VERSION 5.8 ;
BUSBITCHARS "[]" ;
DIVIDERCHAR "/" ;
UNITS
    DATABASE MICRONS 1000 ;
END UNITS

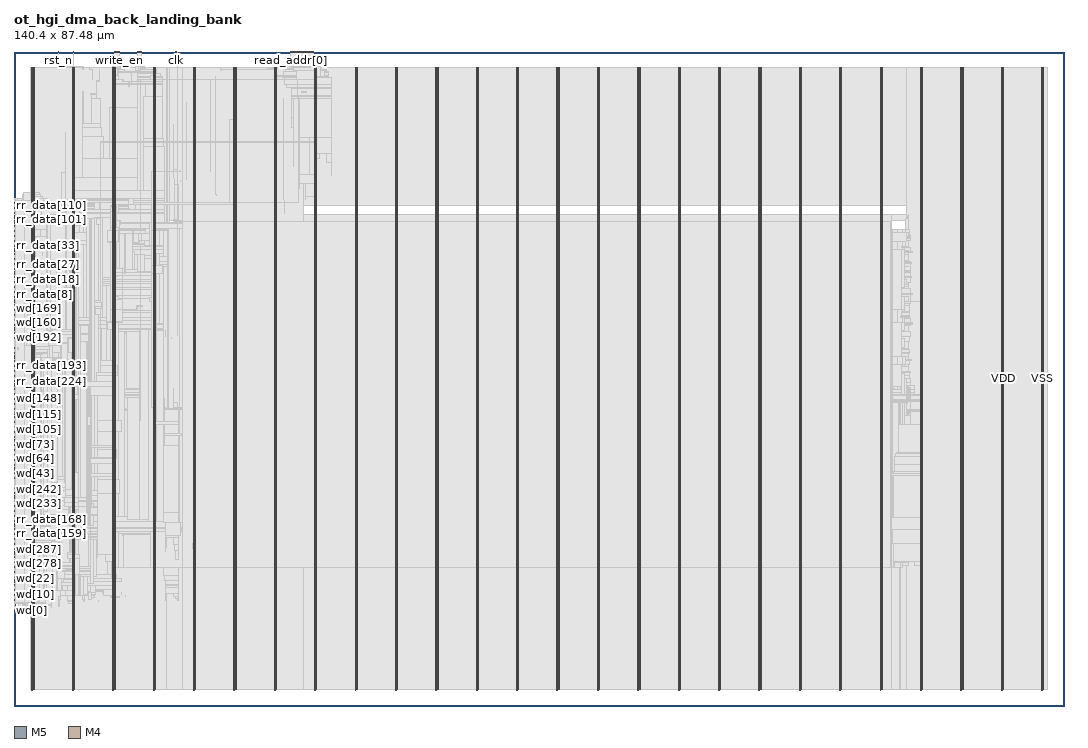
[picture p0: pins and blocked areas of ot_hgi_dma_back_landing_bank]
MACRO ot_hgi_dma_back_landing_bank
  FOREIGN ot_hgi_dma_back_landing_bank 0 0 ;
  CLASS BLOCK ;
  SIZE 140.4 BY 87.48 ;
  PIN clk
    DIRECTION INPUT ;
    USE SIGNAL ;
    PORT
      LAYER M5 ;
        RECT  21.648 87.396 21.672 87.48 ;
    END
  END clk
  PIN output_en
    DIRECTION INPUT ;
    USE SIGNAL ;
    PORT
      LAYER M5 ;
        RECT  40.08 87.396 40.104 87.48 ;
    END
  END output_en
  PIN read_addr[0]
    DIRECTION INPUT ;
    USE SIGNAL ;
    PORT
      LAYER M5 ;
        RECT  37.008 87.396 37.032 87.48 ;
    END
  END read_addr[0]
  PIN read_addr[10]
    DIRECTION INPUT ;
    USE SIGNAL ;
    PORT
      LAYER M5 ;
        RECT  37.968 87.396 37.992 87.48 ;
    END
  END read_addr[10]
  PIN read_addr[11]
    DIRECTION INPUT ;
    USE SIGNAL ;
    PORT
      LAYER M5 ;
        RECT  38.064 87.396 38.088 87.48 ;
    END
  END read_addr[11]
  PIN read_addr[12]
    DIRECTION INPUT ;
    USE SIGNAL ;
    PORT
      LAYER M5 ;
        RECT  38.16 87.396 38.184 87.48 ;
    END
  END read_addr[12]
  PIN read_addr[13]
    DIRECTION INPUT ;
    USE SIGNAL ;
    PORT
      LAYER M5 ;
        RECT  38.256 87.396 38.28 87.48 ;
    END
  END read_addr[13]
  PIN read_addr[14]
    DIRECTION INPUT ;
    USE SIGNAL ;
    PORT
      LAYER M5 ;
        RECT  38.352 87.396 38.376 87.48 ;
    END
  END read_addr[14]
  PIN read_addr[15]
    DIRECTION INPUT ;
    USE SIGNAL ;
    PORT
      LAYER M5 ;
        RECT  38.448 87.396 38.472 87.48 ;
    END
  END read_addr[15]
  PIN read_addr[16]
    DIRECTION INPUT ;
    USE SIGNAL ;
    PORT
      LAYER M5 ;
        RECT  38.544 87.396 38.568 87.48 ;
    END
  END read_addr[16]
  PIN read_addr[17]
    DIRECTION INPUT ;
    USE SIGNAL ;
    PORT
      LAYER M5 ;
        RECT  38.64 87.396 38.664 87.48 ;
    END
  END read_addr[17]
  PIN read_addr[18]
    DIRECTION INPUT ;
    USE SIGNAL ;
    PORT
      LAYER M5 ;
        RECT  38.736 87.396 38.76 87.48 ;
    END
  END read_addr[18]
  PIN read_addr[19]
    DIRECTION INPUT ;
    USE SIGNAL ;
    PORT
      LAYER M5 ;
        RECT  38.832 87.396 38.856 87.48 ;
    END
  END read_addr[19]
  PIN read_addr[1]
    DIRECTION INPUT ;
    USE SIGNAL ;
    PORT
      LAYER M5 ;
        RECT  37.104 87.396 37.128 87.48 ;
    END
  END read_addr[1]
  PIN read_addr[20]
    DIRECTION INPUT ;
    USE SIGNAL ;
    PORT
      LAYER M5 ;
        RECT  38.928 87.396 38.952 87.48 ;
    END
  END read_addr[20]
  PIN read_addr[21]
    DIRECTION INPUT ;
    USE SIGNAL ;
    PORT
      LAYER M5 ;
        RECT  39.024 87.396 39.048 87.48 ;
    END
  END read_addr[21]
  PIN read_addr[22]
    DIRECTION INPUT ;
    USE SIGNAL ;
    PORT
      LAYER M5 ;
        RECT  39.12 87.396 39.144 87.48 ;
    END
  END read_addr[22]
  PIN read_addr[23]
    DIRECTION INPUT ;
    USE SIGNAL ;
    PORT
      LAYER M5 ;
        RECT  39.216 87.396 39.24 87.48 ;
    END
  END read_addr[23]
  PIN read_addr[24]
    DIRECTION INPUT ;
    USE SIGNAL ;
    PORT
      LAYER M5 ;
        RECT  39.312 87.396 39.336 87.48 ;
    END
  END read_addr[24]
  PIN read_addr[25]
    DIRECTION INPUT ;
    USE SIGNAL ;
    PORT
      LAYER M5 ;
        RECT  39.408 87.396 39.432 87.48 ;
    END
  END read_addr[25]
  PIN read_addr[26]
    DIRECTION INPUT ;
    USE SIGNAL ;
    PORT
      LAYER M5 ;
        RECT  39.504 87.396 39.528 87.48 ;
    END
  END read_addr[26]
  PIN read_addr[27]
    DIRECTION INPUT ;
    USE SIGNAL ;
    PORT
      LAYER M5 ;
        RECT  39.6 87.396 39.624 87.48 ;
    END
  END read_addr[27]
  PIN read_addr[28]
    DIRECTION INPUT ;
    USE SIGNAL ;
    PORT
      LAYER M5 ;
        RECT  39.696 87.396 39.72 87.48 ;
    END
  END read_addr[28]
  PIN read_addr[29]
    DIRECTION INPUT ;
    USE SIGNAL ;
    PORT
      LAYER M5 ;
        RECT  39.792 87.396 39.816 87.48 ;
    END
  END read_addr[29]
  PIN read_addr[2]
    DIRECTION INPUT ;
    USE SIGNAL ;
    PORT
      LAYER M5 ;
        RECT  37.2 87.396 37.224 87.48 ;
    END
  END read_addr[2]
  PIN read_addr[30]
    DIRECTION INPUT ;
    USE SIGNAL ;
    PORT
      LAYER M5 ;
        RECT  39.888 87.396 39.912 87.48 ;
    END
  END read_addr[30]
  PIN read_addr[31]
    DIRECTION INPUT ;
    USE SIGNAL ;
    PORT
      LAYER M5 ;
        RECT  39.984 87.396 40.008 87.48 ;
    END
  END read_addr[31]
  PIN read_addr[3]
    DIRECTION INPUT ;
    USE SIGNAL ;
    PORT
      LAYER M5 ;
        RECT  37.296 87.396 37.32 87.48 ;
    END
  END read_addr[3]
  PIN read_addr[4]
    DIRECTION INPUT ;
    USE SIGNAL ;
    PORT
      LAYER M5 ;
        RECT  37.392 87.396 37.416 87.48 ;
    END
  END read_addr[4]
  PIN read_addr[5]
    DIRECTION INPUT ;
    USE SIGNAL ;
    PORT
      LAYER M5 ;
        RECT  37.488 87.396 37.512 87.48 ;
    END
  END read_addr[5]
  PIN read_addr[6]
    DIRECTION INPUT ;
    USE SIGNAL ;
    PORT
      LAYER M5 ;
        RECT  37.584 87.396 37.608 87.48 ;
    END
  END read_addr[6]
  PIN read_addr[7]
    DIRECTION INPUT ;
    USE SIGNAL ;
    PORT
      LAYER M5 ;
        RECT  37.68 87.396 37.704 87.48 ;
    END
  END read_addr[7]
  PIN read_addr[8]
    DIRECTION INPUT ;
    USE SIGNAL ;
    PORT
      LAYER M5 ;
        RECT  37.776 87.396 37.8 87.48 ;
    END
  END read_addr[8]
  PIN read_addr[9]
    DIRECTION INPUT ;
    USE SIGNAL ;
    PORT
      LAYER M5 ;
        RECT  37.872 87.396 37.896 87.48 ;
    END
  END read_addr[9]
  PIN read_en
    DIRECTION INPUT ;
    USE SIGNAL ;
    PORT
      LAYER M5 ;
        RECT  7.92 87.396 7.944 87.48 ;
    END
  END read_en
  PIN read_slot[0]
    DIRECTION INPUT ;
    USE SIGNAL ;
    PORT
      LAYER M5 ;
        RECT  13.392 87.396 13.416 87.48 ;
    END
  END read_slot[0]
  PIN read_slot[1]
    DIRECTION INPUT ;
    USE SIGNAL ;
    PORT
      LAYER M5 ;
        RECT  13.488 87.396 13.512 87.48 ;
    END
  END read_slot[1]
  PIN read_slot[2]
    DIRECTION INPUT ;
    USE SIGNAL ;
    PORT
      LAYER M5 ;
        RECT  13.584 87.396 13.608 87.48 ;
    END
  END read_slot[2]
  PIN read_slot[3]
    DIRECTION INPUT ;
    USE SIGNAL ;
    PORT
      LAYER M5 ;
        RECT  13.68 87.396 13.704 87.48 ;
    END
  END read_slot[3]
  PIN read_slot[4]
    DIRECTION INPUT ;
    USE SIGNAL ;
    PORT
      LAYER M5 ;
        RECT  13.776 87.396 13.8 87.48 ;
    END
  END read_slot[4]
  PIN read_slot[5]
    DIRECTION INPUT ;
    USE SIGNAL ;
    PORT
      LAYER M5 ;
        RECT  13.872 87.396 13.896 87.48 ;
    END
  END read_slot[5]
  PIN read_slot[6]
    DIRECTION INPUT ;
    USE SIGNAL ;
    PORT
      LAYER M5 ;
        RECT  13.968 87.396 13.992 87.48 ;
    END
  END read_slot[6]
  PIN rr_data[0]
    DIRECTION INPUT ;
    USE SIGNAL ;
    PORT
      LAYER M4 ;
        RECT  0 55.344 0.084 55.368 ;
    END
  END rr_data[0]
  PIN rr_data[100]
    DIRECTION INPUT ;
    USE SIGNAL ;
    PORT
      LAYER M4 ;
        RECT  0 64.944 0.084 64.968 ;
    END
  END rr_data[100]
  PIN rr_data[101]
    DIRECTION INPUT ;
    USE SIGNAL ;
    PORT
      LAYER M4 ;
        RECT  0 65.04 0.084 65.064 ;
    END
  END rr_data[101]
  PIN rr_data[102]
    DIRECTION INPUT ;
    USE SIGNAL ;
    PORT
      LAYER M4 ;
        RECT  0 65.136 0.084 65.16 ;
    END
  END rr_data[102]
  PIN rr_data[103]
    DIRECTION INPUT ;
    USE SIGNAL ;
    PORT
      LAYER M4 ;
        RECT  0 65.232 0.084 65.256 ;
    END
  END rr_data[103]
  PIN rr_data[104]
    DIRECTION INPUT ;
    USE SIGNAL ;
    PORT
      LAYER M4 ;
        RECT  0 65.328 0.084 65.352 ;
    END
  END rr_data[104]
  PIN rr_data[105]
    DIRECTION INPUT ;
    USE SIGNAL ;
    PORT
      LAYER M4 ;
        RECT  0 65.424 0.084 65.448 ;
    END
  END rr_data[105]
  PIN rr_data[106]
    DIRECTION INPUT ;
    USE SIGNAL ;
    PORT
      LAYER M4 ;
        RECT  0 65.52 0.084 65.544 ;
    END
  END rr_data[106]
  PIN rr_data[107]
    DIRECTION INPUT ;
    USE SIGNAL ;
    PORT
      LAYER M4 ;
        RECT  0 65.616 0.084 65.64 ;
    END
  END rr_data[107]
  PIN rr_data[108]
    DIRECTION INPUT ;
    USE SIGNAL ;
    PORT
      LAYER M4 ;
        RECT  0 65.712 0.084 65.736 ;
    END
  END rr_data[108]
  PIN rr_data[109]
    DIRECTION INPUT ;
    USE SIGNAL ;
    PORT
      LAYER M4 ;
        RECT  0 65.808 0.084 65.832 ;
    END
  END rr_data[109]
  PIN rr_data[10]
    DIRECTION INPUT ;
    USE SIGNAL ;
    PORT
      LAYER M4 ;
        RECT  0 56.304 0.084 56.328 ;
    END
  END rr_data[10]
  PIN rr_data[110]
    DIRECTION INPUT ;
    USE SIGNAL ;
    PORT
      LAYER M4 ;
        RECT  0 65.904 0.084 65.928 ;
    END
  END rr_data[110]
  PIN rr_data[111]
    DIRECTION INPUT ;
    USE SIGNAL ;
    PORT
      LAYER M4 ;
        RECT  0 66 0.084 66.024 ;
    END
  END rr_data[111]
  PIN rr_data[112]
    DIRECTION INPUT ;
    USE SIGNAL ;
    PORT
      LAYER M4 ;
        RECT  0 66.096 0.084 66.12 ;
    END
  END rr_data[112]
  PIN rr_data[113]
    DIRECTION INPUT ;
    USE SIGNAL ;
    PORT
      LAYER M4 ;
        RECT  0 66.192 0.084 66.216 ;
    END
  END rr_data[113]
  PIN rr_data[114]
    DIRECTION INPUT ;
    USE SIGNAL ;
    PORT
      LAYER M4 ;
        RECT  0 66.288 0.084 66.312 ;
    END
  END rr_data[114]
  PIN rr_data[115]
    DIRECTION INPUT ;
    USE SIGNAL ;
    PORT
      LAYER M4 ;
        RECT  0 66.384 0.084 66.408 ;
    END
  END rr_data[115]
  PIN rr_data[116]
    DIRECTION INPUT ;
    USE SIGNAL ;
    PORT
      LAYER M4 ;
        RECT  0 66.48 0.084 66.504 ;
    END
  END rr_data[116]
  PIN rr_data[117]
    DIRECTION INPUT ;
    USE SIGNAL ;
    PORT
      LAYER M4 ;
        RECT  0 66.576 0.084 66.6 ;
    END
  END rr_data[117]
  PIN rr_data[118]
    DIRECTION INPUT ;
    USE SIGNAL ;
    PORT
      LAYER M4 ;
        RECT  0 66.672 0.084 66.696 ;
    END
  END rr_data[118]
  PIN rr_data[119]
    DIRECTION INPUT ;
    USE SIGNAL ;
    PORT
      LAYER M4 ;
        RECT  0 66.768 0.084 66.792 ;
    END
  END rr_data[119]
  PIN rr_data[11]
    DIRECTION INPUT ;
    USE SIGNAL ;
    PORT
      LAYER M4 ;
        RECT  0 56.4 0.084 56.424 ;
    END
  END rr_data[11]
  PIN rr_data[120]
    DIRECTION INPUT ;
    USE SIGNAL ;
    PORT
      LAYER M4 ;
        RECT  0 66.864 0.084 66.888 ;
    END
  END rr_data[120]
  PIN rr_data[121]
    DIRECTION INPUT ;
    USE SIGNAL ;
    PORT
      LAYER M4 ;
        RECT  0 66.96 0.084 66.984 ;
    END
  END rr_data[121]
  PIN rr_data[122]
    DIRECTION INPUT ;
    USE SIGNAL ;
    PORT
      LAYER M4 ;
        RECT  0 67.056 0.084 67.08 ;
    END
  END rr_data[122]
  PIN rr_data[123]
    DIRECTION INPUT ;
    USE SIGNAL ;
    PORT
      LAYER M4 ;
        RECT  0 67.152 0.084 67.176 ;
    END
  END rr_data[123]
  PIN rr_data[124]
    DIRECTION INPUT ;
    USE SIGNAL ;
    PORT
      LAYER M4 ;
        RECT  0 67.248 0.084 67.272 ;
    END
  END rr_data[124]
  PIN rr_data[125]
    DIRECTION INPUT ;
    USE SIGNAL ;
    PORT
      LAYER M4 ;
        RECT  0 67.344 0.084 67.368 ;
    END
  END rr_data[125]
  PIN rr_data[126]
    DIRECTION INPUT ;
    USE SIGNAL ;
    PORT
      LAYER M4 ;
        RECT  0 67.44 0.084 67.464 ;
    END
  END rr_data[126]
  PIN rr_data[127]
    DIRECTION INPUT ;
    USE SIGNAL ;
    PORT
      LAYER M4 ;
        RECT  0 67.536 0.084 67.56 ;
    END
  END rr_data[127]
  PIN rr_data[128]
    DIRECTION INPUT ;
    USE SIGNAL ;
    PORT
      LAYER M4 ;
        RECT  0 20.016 0.084 20.04 ;
    END
  END rr_data[128]
  PIN rr_data[129]
    DIRECTION INPUT ;
    USE SIGNAL ;
    PORT
      LAYER M4 ;
        RECT  0 20.112 0.084 20.136 ;
    END
  END rr_data[129]
  PIN rr_data[12]
    DIRECTION INPUT ;
    USE SIGNAL ;
    PORT
      LAYER M4 ;
        RECT  0 56.496 0.084 56.52 ;
    END
  END rr_data[12]
  PIN rr_data[130]
    DIRECTION INPUT ;
    USE SIGNAL ;
    PORT
      LAYER M4 ;
        RECT  0 20.208 0.084 20.232 ;
    END
  END rr_data[130]
  PIN rr_data[131]
    DIRECTION INPUT ;
    USE SIGNAL ;
    PORT
      LAYER M4 ;
        RECT  0 20.304 0.084 20.328 ;
    END
  END rr_data[131]
  PIN rr_data[132]
    DIRECTION INPUT ;
    USE SIGNAL ;
    PORT
      LAYER M4 ;
        RECT  0 20.4 0.084 20.424 ;
    END
  END rr_data[132]
  PIN rr_data[133]
    DIRECTION INPUT ;
    USE SIGNAL ;
    PORT
      LAYER M4 ;
        RECT  0 20.496 0.084 20.52 ;
    END
  END rr_data[133]
  PIN rr_data[134]
    DIRECTION INPUT ;
    USE SIGNAL ;
    PORT
      LAYER M4 ;
        RECT  0 20.592 0.084 20.616 ;
    END
  END rr_data[134]
  PIN rr_data[135]
    DIRECTION INPUT ;
    USE SIGNAL ;
    PORT
      LAYER M4 ;
        RECT  0 20.688 0.084 20.712 ;
    END
  END rr_data[135]
  PIN rr_data[136]
    DIRECTION INPUT ;
    USE SIGNAL ;
    PORT
      LAYER M4 ;
        RECT  0 20.784 0.084 20.808 ;
    END
  END rr_data[136]
  PIN rr_data[137]
    DIRECTION INPUT ;
    USE SIGNAL ;
    PORT
      LAYER M4 ;
        RECT  0 20.88 0.084 20.904 ;
    END
  END rr_data[137]
  PIN rr_data[138]
    DIRECTION INPUT ;
    USE SIGNAL ;
    PORT
      LAYER M4 ;
        RECT  0 20.976 0.084 21 ;
    END
  END rr_data[138]
  PIN rr_data[139]
    DIRECTION INPUT ;
    USE SIGNAL ;
    PORT
      LAYER M4 ;
        RECT  0 21.072 0.084 21.096 ;
    END
  END rr_data[139]
  PIN rr_data[13]
    DIRECTION INPUT ;
    USE SIGNAL ;
    PORT
      LAYER M4 ;
        RECT  0 56.592 0.084 56.616 ;
    END
  END rr_data[13]
  PIN rr_data[140]
    DIRECTION INPUT ;
    USE SIGNAL ;
    PORT
      LAYER M4 ;
        RECT  0 21.168 0.084 21.192 ;
    END
  END rr_data[140]
  PIN rr_data[141]
    DIRECTION INPUT ;
    USE SIGNAL ;
    PORT
      LAYER M4 ;
        RECT  0 21.264 0.084 21.288 ;
    END
  END rr_data[141]
  PIN rr_data[142]
    DIRECTION INPUT ;
    USE SIGNAL ;
    PORT
      LAYER M4 ;
        RECT  0 21.36 0.084 21.384 ;
    END
  END rr_data[142]
  PIN rr_data[143]
    DIRECTION INPUT ;
    USE SIGNAL ;
    PORT
      LAYER M4 ;
        RECT  0 21.456 0.084 21.48 ;
    END
  END rr_data[143]
  PIN rr_data[144]
    DIRECTION INPUT ;
    USE SIGNAL ;
    PORT
      LAYER M4 ;
        RECT  0 21.552 0.084 21.576 ;
    END
  END rr_data[144]
  PIN rr_data[145]
    DIRECTION INPUT ;
    USE SIGNAL ;
    PORT
      LAYER M4 ;
        RECT  0 21.648 0.084 21.672 ;
    END
  END rr_data[145]
  PIN rr_data[146]
    DIRECTION INPUT ;
    USE SIGNAL ;
    PORT
      LAYER M4 ;
        RECT  0 21.744 0.084 21.768 ;
    END
  END rr_data[146]
  PIN rr_data[147]
    DIRECTION INPUT ;
    USE SIGNAL ;
    PORT
      LAYER M4 ;
        RECT  0 21.84 0.084 21.864 ;
    END
  END rr_data[147]
  PIN rr_data[148]
    DIRECTION INPUT ;
    USE SIGNAL ;
    PORT
      LAYER M4 ;
        RECT  0 21.936 0.084 21.96 ;
    END
  END rr_data[148]
  PIN rr_data[149]
    DIRECTION INPUT ;
    USE SIGNAL ;
    PORT
      LAYER M4 ;
        RECT  0 22.032 0.084 22.056 ;
    END
  END rr_data[149]
  PIN rr_data[14]
    DIRECTION INPUT ;
    USE SIGNAL ;
    PORT
      LAYER M4 ;
        RECT  0 56.688 0.084 56.712 ;
    END
  END rr_data[14]
  PIN rr_data[150]
    DIRECTION INPUT ;
    USE SIGNAL ;
    PORT
      LAYER M4 ;
        RECT  0 22.128 0.084 22.152 ;
    END
  END rr_data[150]
  PIN rr_data[151]
    DIRECTION INPUT ;
    USE SIGNAL ;
    PORT
      LAYER M4 ;
        RECT  0 22.224 0.084 22.248 ;
    END
  END rr_data[151]
  PIN rr_data[152]
    DIRECTION INPUT ;
    USE SIGNAL ;
    PORT
      LAYER M4 ;
        RECT  0 22.32 0.084 22.344 ;
    END
  END rr_data[152]
  PIN rr_data[153]
    DIRECTION INPUT ;
    USE SIGNAL ;
    PORT
      LAYER M4 ;
        RECT  0 22.416 0.084 22.44 ;
    END
  END rr_data[153]
  PIN rr_data[154]
    DIRECTION INPUT ;
    USE SIGNAL ;
    PORT
      LAYER M4 ;
        RECT  0 22.512 0.084 22.536 ;
    END
  END rr_data[154]
  PIN rr_data[155]
    DIRECTION INPUT ;
    USE SIGNAL ;
    PORT
      LAYER M4 ;
        RECT  0 22.608 0.084 22.632 ;
    END
  END rr_data[155]
  PIN rr_data[156]
    DIRECTION INPUT ;
    USE SIGNAL ;
    PORT
      LAYER M4 ;
        RECT  0 22.704 0.084 22.728 ;
    END
  END rr_data[156]
  PIN rr_data[157]
    DIRECTION INPUT ;
    USE SIGNAL ;
    PORT
      LAYER M4 ;
        RECT  0 22.8 0.084 22.824 ;
    END
  END rr_data[157]
  PIN rr_data[158]
    DIRECTION INPUT ;
    USE SIGNAL ;
    PORT
      LAYER M4 ;
        RECT  0 22.896 0.084 22.92 ;
    END
  END rr_data[158]
  PIN rr_data[159]
    DIRECTION INPUT ;
    USE SIGNAL ;
    PORT
      LAYER M4 ;
        RECT  0 22.992 0.084 23.016 ;
    END
  END rr_data[159]
  PIN rr_data[15]
    DIRECTION INPUT ;
    USE SIGNAL ;
    PORT
      LAYER M4 ;
        RECT  0 56.784 0.084 56.808 ;
    END
  END rr_data[15]
  PIN rr_data[160]
    DIRECTION INPUT ;
    USE SIGNAL ;
    PORT
      LAYER M4 ;
        RECT  0 23.088 0.084 23.112 ;
    END
  END rr_data[160]
  PIN rr_data[161]
    DIRECTION INPUT ;
    USE SIGNAL ;
    PORT
      LAYER M4 ;
        RECT  0 23.184 0.084 23.208 ;
    END
  END rr_data[161]
  PIN rr_data[162]
    DIRECTION INPUT ;
    USE SIGNAL ;
    PORT
      LAYER M4 ;
        RECT  0 23.28 0.084 23.304 ;
    END
  END rr_data[162]
  PIN rr_data[163]
    DIRECTION INPUT ;
    USE SIGNAL ;
    PORT
      LAYER M4 ;
        RECT  0 23.376 0.084 23.4 ;
    END
  END rr_data[163]
  PIN rr_data[164]
    DIRECTION INPUT ;
    USE SIGNAL ;
    PORT
      LAYER M4 ;
        RECT  0 23.472 0.084 23.496 ;
    END
  END rr_data[164]
  PIN rr_data[165]
    DIRECTION INPUT ;
    USE SIGNAL ;
    PORT
      LAYER M4 ;
        RECT  0 23.568 0.084 23.592 ;
    END
  END rr_data[165]
  PIN rr_data[166]
    DIRECTION INPUT ;
    USE SIGNAL ;
    PORT
      LAYER M4 ;
        RECT  0 23.664 0.084 23.688 ;
    END
  END rr_data[166]
  PIN rr_data[167]
    DIRECTION INPUT ;
    USE SIGNAL ;
    PORT
      LAYER M4 ;
        RECT  0 23.76 0.084 23.784 ;
    END
  END rr_data[167]
  PIN rr_data[168]
    DIRECTION INPUT ;
    USE SIGNAL ;
    PORT
      LAYER M4 ;
        RECT  0 23.856 0.084 23.88 ;
    END
  END rr_data[168]
  PIN rr_data[169]
    DIRECTION INPUT ;
    USE SIGNAL ;
    PORT
      LAYER M4 ;
        RECT  0 23.952 0.084 23.976 ;
    END
  END rr_data[169]
  PIN rr_data[16]
    DIRECTION INPUT ;
    USE SIGNAL ;
    PORT
      LAYER M4 ;
        RECT  0 56.88 0.084 56.904 ;
    END
  END rr_data[16]
  PIN rr_data[170]
    DIRECTION INPUT ;
    USE SIGNAL ;
    PORT
      LAYER M4 ;
        RECT  0 24.048 0.084 24.072 ;
    END
  END rr_data[170]
  PIN rr_data[171]
    DIRECTION INPUT ;
    USE SIGNAL ;
    PORT
      LAYER M4 ;
        RECT  0 24.144 0.084 24.168 ;
    END
  END rr_data[171]
  PIN rr_data[172]
    DIRECTION INPUT ;
    USE SIGNAL ;
    PORT
      LAYER M4 ;
        RECT  0 24.24 0.084 24.264 ;
    END
  END rr_data[172]
  PIN rr_data[173]
    DIRECTION INPUT ;
    USE SIGNAL ;
    PORT
      LAYER M4 ;
        RECT  0 24.336 0.084 24.36 ;
    END
  END rr_data[173]
  PIN rr_data[174]
    DIRECTION INPUT ;
    USE SIGNAL ;
    PORT
      LAYER M4 ;
        RECT  0 24.432 0.084 24.456 ;
    END
  END rr_data[174]
  PIN rr_data[175]
    DIRECTION INPUT ;
    USE SIGNAL ;
    PORT
      LAYER M4 ;
        RECT  0 24.528 0.084 24.552 ;
    END
  END rr_data[175]
  PIN rr_data[176]
    DIRECTION INPUT ;
    USE SIGNAL ;
    PORT
      LAYER M4 ;
        RECT  0 24.624 0.084 24.648 ;
    END
  END rr_data[176]
  PIN rr_data[177]
    DIRECTION INPUT ;
    USE SIGNAL ;
    PORT
      LAYER M4 ;
        RECT  0 24.72 0.084 24.744 ;
    END
  END rr_data[177]
  PIN rr_data[178]
    DIRECTION INPUT ;
    USE SIGNAL ;
    PORT
      LAYER M4 ;
        RECT  0 24.816 0.084 24.84 ;
    END
  END rr_data[178]
  PIN rr_data[179]
    DIRECTION INPUT ;
    USE SIGNAL ;
    PORT
      LAYER M4 ;
        RECT  0 24.912 0.084 24.936 ;
    END
  END rr_data[179]
  PIN rr_data[17]
    DIRECTION INPUT ;
    USE SIGNAL ;
    PORT
      LAYER M4 ;
        RECT  0 56.976 0.084 57 ;
    END
  END rr_data[17]
  PIN rr_data[180]
    DIRECTION INPUT ;
    USE SIGNAL ;
    PORT
      LAYER M4 ;
        RECT  0 25.008 0.084 25.032 ;
    END
  END rr_data[180]
  PIN rr_data[181]
    DIRECTION INPUT ;
    USE SIGNAL ;
    PORT
      LAYER M4 ;
        RECT  0 25.104 0.084 25.128 ;
    END
  END rr_data[181]
  PIN rr_data[182]
    DIRECTION INPUT ;
    USE SIGNAL ;
    PORT
      LAYER M4 ;
        RECT  0 25.2 0.084 25.224 ;
    END
  END rr_data[182]
  PIN rr_data[183]
    DIRECTION INPUT ;
    USE SIGNAL ;
    PORT
      LAYER M4 ;
        RECT  0 25.296 0.084 25.32 ;
    END
  END rr_data[183]
  PIN rr_data[184]
    DIRECTION INPUT ;
    USE SIGNAL ;
    PORT
      LAYER M4 ;
        RECT  0 25.392 0.084 25.416 ;
    END
  END rr_data[184]
  PIN rr_data[185]
    DIRECTION INPUT ;
    USE SIGNAL ;
    PORT
      LAYER M4 ;
        RECT  0 25.488 0.084 25.512 ;
    END
  END rr_data[185]
  PIN rr_data[186]
    DIRECTION INPUT ;
    USE SIGNAL ;
    PORT
      LAYER M4 ;
        RECT  0 25.584 0.084 25.608 ;
    END
  END rr_data[186]
  PIN rr_data[187]
    DIRECTION INPUT ;
    USE SIGNAL ;
    PORT
      LAYER M4 ;
        RECT  0 25.68 0.084 25.704 ;
    END
  END rr_data[187]
  PIN rr_data[188]
    DIRECTION INPUT ;
    USE SIGNAL ;
    PORT
      LAYER M4 ;
        RECT  0 25.776 0.084 25.8 ;
    END
  END rr_data[188]
  PIN rr_data[189]
    DIRECTION INPUT ;
    USE SIGNAL ;
    PORT
      LAYER M4 ;
        RECT  0 25.872 0.084 25.896 ;
    END
  END rr_data[189]
  PIN rr_data[18]
    DIRECTION INPUT ;
    USE SIGNAL ;
    PORT
      LAYER M4 ;
        RECT  0 57.072 0.084 57.096 ;
    END
  END rr_data[18]
  PIN rr_data[190]
    DIRECTION INPUT ;
    USE SIGNAL ;
    PORT
      LAYER M4 ;
        RECT  0 25.968 0.084 25.992 ;
    END
  END rr_data[190]
  PIN rr_data[191]
    DIRECTION INPUT ;
    USE SIGNAL ;
    PORT
      LAYER M4 ;
        RECT  0 26.064 0.084 26.088 ;
    END
  END rr_data[191]
  PIN rr_data[192]
    DIRECTION INPUT ;
    USE SIGNAL ;
    PORT
      LAYER M4 ;
        RECT  0 45.36 0.084 45.384 ;
    END
  END rr_data[192]
  PIN rr_data[193]
    DIRECTION INPUT ;
    USE SIGNAL ;
    PORT
      LAYER M4 ;
        RECT  0 45.456 0.084 45.48 ;
    END
  END rr_data[193]
  PIN rr_data[194]
    DIRECTION INPUT ;
    USE SIGNAL ;
    PORT
      LAYER M4 ;
        RECT  0 45.552 0.084 45.576 ;
    END
  END rr_data[194]
  PIN rr_data[195]
    DIRECTION INPUT ;
    USE SIGNAL ;
    PORT
      LAYER M4 ;
        RECT  0 45.648 0.084 45.672 ;
    END
  END rr_data[195]
  PIN rr_data[196]
    DIRECTION INPUT ;
    USE SIGNAL ;
    PORT
      LAYER M4 ;
        RECT  0 45.744 0.084 45.768 ;
    END
  END rr_data[196]
  PIN rr_data[197]
    DIRECTION INPUT ;
    USE SIGNAL ;
    PORT
      LAYER M4 ;
        RECT  0 45.84 0.084 45.864 ;
    END
  END rr_data[197]
  PIN rr_data[198]
    DIRECTION INPUT ;
    USE SIGNAL ;
    PORT
      LAYER M4 ;
        RECT  0 45.936 0.084 45.96 ;
    END
  END rr_data[198]
  PIN rr_data[199]
    DIRECTION INPUT ;
    USE SIGNAL ;
    PORT
      LAYER M4 ;
        RECT  0 46.032 0.084 46.056 ;
    END
  END rr_data[199]
  PIN rr_data[19]
    DIRECTION INPUT ;
    USE SIGNAL ;
    PORT
      LAYER M4 ;
        RECT  0 57.168 0.084 57.192 ;
    END
  END rr_data[19]
  PIN rr_data[1]
    DIRECTION INPUT ;
    USE SIGNAL ;
    PORT
      LAYER M4 ;
        RECT  0 55.44 0.084 55.464 ;
    END
  END rr_data[1]
  PIN rr_data[200]
    DIRECTION INPUT ;
    USE SIGNAL ;
    PORT
      LAYER M4 ;
        RECT  0 46.128 0.084 46.152 ;
    END
  END rr_data[200]
  PIN rr_data[201]
    DIRECTION INPUT ;
    USE SIGNAL ;
    PORT
      LAYER M4 ;
        RECT  0 46.224 0.084 46.248 ;
    END
  END rr_data[201]
  PIN rr_data[202]
    DIRECTION INPUT ;
    USE SIGNAL ;
    PORT
      LAYER M4 ;
        RECT  0 46.32 0.084 46.344 ;
    END
  END rr_data[202]
  PIN rr_data[203]
    DIRECTION INPUT ;
    USE SIGNAL ;
    PORT
      LAYER M4 ;
        RECT  0 46.416 0.084 46.44 ;
    END
  END rr_data[203]
  PIN rr_data[204]
    DIRECTION INPUT ;
    USE SIGNAL ;
    PORT
      LAYER M4 ;
        RECT  0 46.512 0.084 46.536 ;
    END
  END rr_data[204]
  PIN rr_data[205]
    DIRECTION INPUT ;
    USE SIGNAL ;
    PORT
      LAYER M4 ;
        RECT  0 46.608 0.084 46.632 ;
    END
  END rr_data[205]
  PIN rr_data[206]
    DIRECTION INPUT ;
    USE SIGNAL ;
    PORT
      LAYER M4 ;
        RECT  0 46.704 0.084 46.728 ;
    END
  END rr_data[206]
  PIN rr_data[207]
    DIRECTION INPUT ;
    USE SIGNAL ;
    PORT
      LAYER M4 ;
        RECT  0 46.8 0.084 46.824 ;
    END
  END rr_data[207]
  PIN rr_data[208]
    DIRECTION INPUT ;
    USE SIGNAL ;
    PORT
      LAYER M4 ;
        RECT  0 46.896 0.084 46.92 ;
    END
  END rr_data[208]
  PIN rr_data[209]
    DIRECTION INPUT ;
    USE SIGNAL ;
    PORT
      LAYER M4 ;
        RECT  0 46.992 0.084 47.016 ;
    END
  END rr_data[209]
  PIN rr_data[20]
    DIRECTION INPUT ;
    USE SIGNAL ;
    PORT
      LAYER M4 ;
        RECT  0 57.264 0.084 57.288 ;
    END
  END rr_data[20]
  PIN rr_data[210]
    DIRECTION INPUT ;
    USE SIGNAL ;
    PORT
      LAYER M4 ;
        RECT  0 47.088 0.084 47.112 ;
    END
  END rr_data[210]
  PIN rr_data[211]
    DIRECTION INPUT ;
    USE SIGNAL ;
    PORT
      LAYER M4 ;
        RECT  0 47.184 0.084 47.208 ;
    END
  END rr_data[211]
  PIN rr_data[212]
    DIRECTION INPUT ;
    USE SIGNAL ;
    PORT
      LAYER M4 ;
        RECT  0 47.28 0.084 47.304 ;
    END
  END rr_data[212]
  PIN rr_data[213]
    DIRECTION INPUT ;
    USE SIGNAL ;
    PORT
      LAYER M4 ;
        RECT  0 47.376 0.084 47.4 ;
    END
  END rr_data[213]
  PIN rr_data[214]
    DIRECTION INPUT ;
    USE SIGNAL ;
    PORT
      LAYER M4 ;
        RECT  0 47.472 0.084 47.496 ;
    END
  END rr_data[214]
  PIN rr_data[215]
    DIRECTION INPUT ;
    USE SIGNAL ;
    PORT
      LAYER M4 ;
        RECT  0 47.568 0.084 47.592 ;
    END
  END rr_data[215]
  PIN rr_data[216]
    DIRECTION INPUT ;
    USE SIGNAL ;
    PORT
      LAYER M4 ;
        RECT  0 47.664 0.084 47.688 ;
    END
  END rr_data[216]
  PIN rr_data[217]
    DIRECTION INPUT ;
    USE SIGNAL ;
    PORT
      LAYER M4 ;
        RECT  0 47.76 0.084 47.784 ;
    END
  END rr_data[217]
  PIN rr_data[218]
    DIRECTION INPUT ;
    USE SIGNAL ;
    PORT
      LAYER M4 ;
        RECT  0 47.856 0.084 47.88 ;
    END
  END rr_data[218]
  PIN rr_data[219]
    DIRECTION INPUT ;
    USE SIGNAL ;
    PORT
      LAYER M4 ;
        RECT  0 47.952 0.084 47.976 ;
    END
  END rr_data[219]
  PIN rr_data[21]
    DIRECTION INPUT ;
    USE SIGNAL ;
    PORT
      LAYER M4 ;
        RECT  0 57.36 0.084 57.384 ;
    END
  END rr_data[21]
  PIN rr_data[220]
    DIRECTION INPUT ;
    USE SIGNAL ;
    PORT
      LAYER M4 ;
        RECT  0 48.048 0.084 48.072 ;
    END
  END rr_data[220]
  PIN rr_data[221]
    DIRECTION INPUT ;
    USE SIGNAL ;
    PORT
      LAYER M4 ;
        RECT  0 48.144 0.084 48.168 ;
    END
  END rr_data[221]
  PIN rr_data[222]
    DIRECTION INPUT ;
    USE SIGNAL ;
    PORT
      LAYER M4 ;
        RECT  0 48.24 0.084 48.264 ;
    END
  END rr_data[222]
  PIN rr_data[223]
    DIRECTION INPUT ;
    USE SIGNAL ;
    PORT
      LAYER M4 ;
        RECT  0 48.336 0.084 48.36 ;
    END
  END rr_data[223]
  PIN rr_data[224]
    DIRECTION INPUT ;
    USE SIGNAL ;
    PORT
      LAYER M4 ;
        RECT  0 42.288 0.084 42.312 ;
    END
  END rr_data[224]
  PIN rr_data[225]
    DIRECTION INPUT ;
    USE SIGNAL ;
    PORT
      LAYER M4 ;
        RECT  0 42.384 0.084 42.408 ;
    END
  END rr_data[225]
  PIN rr_data[226]
    DIRECTION INPUT ;
    USE SIGNAL ;
    PORT
      LAYER M4 ;
        RECT  0 42.48 0.084 42.504 ;
    END
  END rr_data[226]
  PIN rr_data[227]
    DIRECTION INPUT ;
    USE SIGNAL ;
    PORT
      LAYER M4 ;
        RECT  0 42.576 0.084 42.6 ;
    END
  END rr_data[227]
  PIN rr_data[228]
    DIRECTION INPUT ;
    USE SIGNAL ;
    PORT
      LAYER M4 ;
        RECT  0 42.672 0.084 42.696 ;
    END
  END rr_data[228]
  PIN rr_data[229]
    DIRECTION INPUT ;
    USE SIGNAL ;
    PORT
      LAYER M4 ;
        RECT  0 42.768 0.084 42.792 ;
    END
  END rr_data[229]
  PIN rr_data[22]
    DIRECTION INPUT ;
    USE SIGNAL ;
    PORT
      LAYER M4 ;
        RECT  0 57.456 0.084 57.48 ;
    END
  END rr_data[22]
  PIN rr_data[230]
    DIRECTION INPUT ;
    USE SIGNAL ;
    PORT
      LAYER M4 ;
        RECT  0 42.864 0.084 42.888 ;
    END
  END rr_data[230]
  PIN rr_data[231]
    DIRECTION INPUT ;
    USE SIGNAL ;
    PORT
      LAYER M4 ;
        RECT  0 42.96 0.084 42.984 ;
    END
  END rr_data[231]
  PIN rr_data[232]
    DIRECTION INPUT ;
    USE SIGNAL ;
    PORT
      LAYER M4 ;
        RECT  0 43.056 0.084 43.08 ;
    END
  END rr_data[232]
  PIN rr_data[233]
    DIRECTION INPUT ;
    USE SIGNAL ;
    PORT
      LAYER M4 ;
        RECT  0 43.152 0.084 43.176 ;
    END
  END rr_data[233]
  PIN rr_data[234]
    DIRECTION INPUT ;
    USE SIGNAL ;
    PORT
      LAYER M4 ;
        RECT  0 43.248 0.084 43.272 ;
    END
  END rr_data[234]
  PIN rr_data[235]
    DIRECTION INPUT ;
    USE SIGNAL ;
    PORT
      LAYER M4 ;
        RECT  0 43.344 0.084 43.368 ;
    END
  END rr_data[235]
  PIN rr_data[236]
    DIRECTION INPUT ;
    USE SIGNAL ;
    PORT
      LAYER M4 ;
        RECT  0 43.44 0.084 43.464 ;
    END
  END rr_data[236]
  PIN rr_data[237]
    DIRECTION INPUT ;
    USE SIGNAL ;
    PORT
      LAYER M4 ;
        RECT  0 43.536 0.084 43.56 ;
    END
  END rr_data[237]
  PIN rr_data[238]
    DIRECTION INPUT ;
    USE SIGNAL ;
    PORT
      LAYER M4 ;
        RECT  0 43.632 0.084 43.656 ;
    END
  END rr_data[238]
  PIN rr_data[239]
    DIRECTION INPUT ;
    USE SIGNAL ;
    PORT
      LAYER M4 ;
        RECT  0 43.728 0.084 43.752 ;
    END
  END rr_data[239]
  PIN rr_data[23]
    DIRECTION INPUT ;
    USE SIGNAL ;
    PORT
      LAYER M4 ;
        RECT  0 57.552 0.084 57.576 ;
    END
  END rr_data[23]
  PIN rr_data[240]
    DIRECTION INPUT ;
    USE SIGNAL ;
    PORT
      LAYER M4 ;
        RECT  0 43.824 0.084 43.848 ;
    END
  END rr_data[240]
  PIN rr_data[241]
    DIRECTION INPUT ;
    USE SIGNAL ;
    PORT
      LAYER M4 ;
        RECT  0 43.92 0.084 43.944 ;
    END
  END rr_data[241]
  PIN rr_data[242]
    DIRECTION INPUT ;
    USE SIGNAL ;
    PORT
      LAYER M4 ;
        RECT  0 44.016 0.084 44.04 ;
    END
  END rr_data[242]
  PIN rr_data[243]
    DIRECTION INPUT ;
    USE SIGNAL ;
    PORT
      LAYER M4 ;
        RECT  0 44.112 0.084 44.136 ;
    END
  END rr_data[243]
  PIN rr_data[244]
    DIRECTION INPUT ;
    USE SIGNAL ;
    PORT
      LAYER M4 ;
        RECT  0 44.208 0.084 44.232 ;
    END
  END rr_data[244]
  PIN rr_data[245]
    DIRECTION INPUT ;
    USE SIGNAL ;
    PORT
      LAYER M4 ;
        RECT  0 44.304 0.084 44.328 ;
    END
  END rr_data[245]
  PIN rr_data[246]
    DIRECTION INPUT ;
    USE SIGNAL ;
    PORT
      LAYER M4 ;
        RECT  0 44.4 0.084 44.424 ;
    END
  END rr_data[246]
  PIN rr_data[247]
    DIRECTION INPUT ;
    USE SIGNAL ;
    PORT
      LAYER M4 ;
        RECT  0 44.496 0.084 44.52 ;
    END
  END rr_data[247]
  PIN rr_data[248]
    DIRECTION INPUT ;
    USE SIGNAL ;
    PORT
      LAYER M4 ;
        RECT  0 44.592 0.084 44.616 ;
    END
  END rr_data[248]
  PIN rr_data[249]
    DIRECTION INPUT ;
    USE SIGNAL ;
    PORT
      LAYER M4 ;
        RECT  0 44.688 0.084 44.712 ;
    END
  END rr_data[249]
  PIN rr_data[24]
    DIRECTION INPUT ;
    USE SIGNAL ;
    PORT
      LAYER M4 ;
        RECT  0 57.648 0.084 57.672 ;
    END
  END rr_data[24]
  PIN rr_data[250]
    DIRECTION INPUT ;
    USE SIGNAL ;
    PORT
      LAYER M4 ;
        RECT  0 44.784 0.084 44.808 ;
    END
  END rr_data[250]
  PIN rr_data[251]
    DIRECTION INPUT ;
    USE SIGNAL ;
    PORT
      LAYER M4 ;
        RECT  0 44.88 0.084 44.904 ;
    END
  END rr_data[251]
  PIN rr_data[252]
    DIRECTION INPUT ;
    USE SIGNAL ;
    PORT
      LAYER M4 ;
        RECT  0 44.976 0.084 45 ;
    END
  END rr_data[252]
  PIN rr_data[253]
    DIRECTION INPUT ;
    USE SIGNAL ;
    PORT
      LAYER M4 ;
        RECT  0 45.072 0.084 45.096 ;
    END
  END rr_data[253]
  PIN rr_data[254]
    DIRECTION INPUT ;
    USE SIGNAL ;
    PORT
      LAYER M4 ;
        RECT  0 45.168 0.084 45.192 ;
    END
  END rr_data[254]
  PIN rr_data[255]
    DIRECTION INPUT ;
    USE SIGNAL ;
    PORT
      LAYER M4 ;
        RECT  0 45.264 0.084 45.288 ;
    END
  END rr_data[255]
  PIN rr_data[25]
    DIRECTION INPUT ;
    USE SIGNAL ;
    PORT
      LAYER M4 ;
        RECT  0 57.744 0.084 57.768 ;
    END
  END rr_data[25]
  PIN rr_data[26]
    DIRECTION INPUT ;
    USE SIGNAL ;
    PORT
      LAYER M4 ;
        RECT  0 57.84 0.084 57.864 ;
    END
  END rr_data[26]
  PIN rr_data[27]
    DIRECTION INPUT ;
    USE SIGNAL ;
    PORT
      LAYER M4 ;
        RECT  0 57.936 0.084 57.96 ;
    END
  END rr_data[27]
  PIN rr_data[28]
    DIRECTION INPUT ;
    USE SIGNAL ;
    PORT
      LAYER M4 ;
        RECT  0 58.032 0.084 58.056 ;
    END
  END rr_data[28]
  PIN rr_data[29]
    DIRECTION INPUT ;
    USE SIGNAL ;
    PORT
      LAYER M4 ;
        RECT  0 58.128 0.084 58.152 ;
    END
  END rr_data[29]
  PIN rr_data[2]
    DIRECTION INPUT ;
    USE SIGNAL ;
    PORT
      LAYER M4 ;
        RECT  0 55.536 0.084 55.56 ;
    END
  END rr_data[2]
  PIN rr_data[30]
    DIRECTION INPUT ;
    USE SIGNAL ;
    PORT
      LAYER M4 ;
        RECT  0 58.224 0.084 58.248 ;
    END
  END rr_data[30]
  PIN rr_data[31]
    DIRECTION INPUT ;
    USE SIGNAL ;
    PORT
      LAYER M4 ;
        RECT  0 58.32 0.084 58.344 ;
    END
  END rr_data[31]
  PIN rr_data[32]
    DIRECTION INPUT ;
    USE SIGNAL ;
    PORT
      LAYER M4 ;
        RECT  0 61.488 0.084 61.512 ;
    END
  END rr_data[32]
  PIN rr_data[33]
    DIRECTION INPUT ;
    USE SIGNAL ;
    PORT
      LAYER M4 ;
        RECT  0 61.584 0.084 61.608 ;
    END
  END rr_data[33]
  PIN rr_data[34]
    DIRECTION INPUT ;
    USE SIGNAL ;
    PORT
      LAYER M4 ;
        RECT  0 61.68 0.084 61.704 ;
    END
  END rr_data[34]
  PIN rr_data[35]
    DIRECTION INPUT ;
    USE SIGNAL ;
    PORT
      LAYER M4 ;
        RECT  0 61.776 0.084 61.8 ;
    END
  END rr_data[35]
  PIN rr_data[36]
    DIRECTION INPUT ;
    USE SIGNAL ;
    PORT
      LAYER M4 ;
        RECT  0 61.872 0.084 61.896 ;
    END
  END rr_data[36]
  PIN rr_data[37]
    DIRECTION INPUT ;
    USE SIGNAL ;
    PORT
      LAYER M4 ;
        RECT  0 61.968 0.084 61.992 ;
    END
  END rr_data[37]
  PIN rr_data[38]
    DIRECTION INPUT ;
    USE SIGNAL ;
    PORT
      LAYER M4 ;
        RECT  0 62.064 0.084 62.088 ;
    END
  END rr_data[38]
  PIN rr_data[39]
    DIRECTION INPUT ;
    USE SIGNAL ;
    PORT
      LAYER M4 ;
        RECT  0 62.16 0.084 62.184 ;
    END
  END rr_data[39]
  PIN rr_data[3]
    DIRECTION INPUT ;
    USE SIGNAL ;
    PORT
      LAYER M4 ;
        RECT  0 55.632 0.084 55.656 ;
    END
  END rr_data[3]
  PIN rr_data[40]
    DIRECTION INPUT ;
    USE SIGNAL ;
    PORT
      LAYER M4 ;
        RECT  0 62.256 0.084 62.28 ;
    END
  END rr_data[40]
  PIN rr_data[41]
    DIRECTION INPUT ;
    USE SIGNAL ;
    PORT
      LAYER M4 ;
        RECT  0 62.352 0.084 62.376 ;
    END
  END rr_data[41]
  PIN rr_data[42]
    DIRECTION INPUT ;
    USE SIGNAL ;
    PORT
      LAYER M4 ;
        RECT  0 62.448 0.084 62.472 ;
    END
  END rr_data[42]
  PIN rr_data[43]
    DIRECTION INPUT ;
    USE SIGNAL ;
    PORT
      LAYER M4 ;
        RECT  0 62.544 0.084 62.568 ;
    END
  END rr_data[43]
  PIN rr_data[44]
    DIRECTION INPUT ;
    USE SIGNAL ;
    PORT
      LAYER M4 ;
        RECT  0 62.64 0.084 62.664 ;
    END
  END rr_data[44]
  PIN rr_data[45]
    DIRECTION INPUT ;
    USE SIGNAL ;
    PORT
      LAYER M4 ;
        RECT  0 62.736 0.084 62.76 ;
    END
  END rr_data[45]
  PIN rr_data[46]
    DIRECTION INPUT ;
    USE SIGNAL ;
    PORT
      LAYER M4 ;
        RECT  0 62.832 0.084 62.856 ;
    END
  END rr_data[46]
  PIN rr_data[47]
    DIRECTION INPUT ;
    USE SIGNAL ;
    PORT
      LAYER M4 ;
        RECT  0 62.928 0.084 62.952 ;
    END
  END rr_data[47]
  PIN rr_data[48]
    DIRECTION INPUT ;
    USE SIGNAL ;
    PORT
      LAYER M4 ;
        RECT  0 63.024 0.084 63.048 ;
    END
  END rr_data[48]
  PIN rr_data[49]
    DIRECTION INPUT ;
    USE SIGNAL ;
    PORT
      LAYER M4 ;
        RECT  0 63.12 0.084 63.144 ;
    END
  END rr_data[49]
  PIN rr_data[4]
    DIRECTION INPUT ;
    USE SIGNAL ;
    PORT
      LAYER M4 ;
        RECT  0 55.728 0.084 55.752 ;
    END
  END rr_data[4]
  PIN rr_data[50]
    DIRECTION INPUT ;
    USE SIGNAL ;
    PORT
      LAYER M4 ;
        RECT  0 63.216 0.084 63.24 ;
    END
  END rr_data[50]
  PIN rr_data[51]
    DIRECTION INPUT ;
    USE SIGNAL ;
    PORT
      LAYER M4 ;
        RECT  0 63.312 0.084 63.336 ;
    END
  END rr_data[51]
  PIN rr_data[52]
    DIRECTION INPUT ;
    USE SIGNAL ;
    PORT
      LAYER M4 ;
        RECT  0 63.408 0.084 63.432 ;
    END
  END rr_data[52]
  PIN rr_data[53]
    DIRECTION INPUT ;
    USE SIGNAL ;
    PORT
      LAYER M4 ;
        RECT  0 63.504 0.084 63.528 ;
    END
  END rr_data[53]
  PIN rr_data[54]
    DIRECTION INPUT ;
    USE SIGNAL ;
    PORT
      LAYER M4 ;
        RECT  0 63.6 0.084 63.624 ;
    END
  END rr_data[54]
  PIN rr_data[55]
    DIRECTION INPUT ;
    USE SIGNAL ;
    PORT
      LAYER M4 ;
        RECT  0 63.696 0.084 63.72 ;
    END
  END rr_data[55]
  PIN rr_data[56]
    DIRECTION INPUT ;
    USE SIGNAL ;
    PORT
      LAYER M4 ;
        RECT  0 63.792 0.084 63.816 ;
    END
  END rr_data[56]
  PIN rr_data[57]
    DIRECTION INPUT ;
    USE SIGNAL ;
    PORT
      LAYER M4 ;
        RECT  0 63.888 0.084 63.912 ;
    END
  END rr_data[57]
  PIN rr_data[58]
    DIRECTION INPUT ;
    USE SIGNAL ;
    PORT
      LAYER M4 ;
        RECT  0 63.984 0.084 64.008 ;
    END
  END rr_data[58]
  PIN rr_data[59]
    DIRECTION INPUT ;
    USE SIGNAL ;
    PORT
      LAYER M4 ;
        RECT  0 64.08 0.084 64.104 ;
    END
  END rr_data[59]
  PIN rr_data[5]
    DIRECTION INPUT ;
    USE SIGNAL ;
    PORT
      LAYER M4 ;
        RECT  0 55.824 0.084 55.848 ;
    END
  END rr_data[5]
  PIN rr_data[60]
    DIRECTION INPUT ;
    USE SIGNAL ;
    PORT
      LAYER M4 ;
        RECT  0 64.176 0.084 64.2 ;
    END
  END rr_data[60]
  PIN rr_data[61]
    DIRECTION INPUT ;
    USE SIGNAL ;
    PORT
      LAYER M4 ;
        RECT  0 64.272 0.084 64.296 ;
    END
  END rr_data[61]
  PIN rr_data[62]
    DIRECTION INPUT ;
    USE SIGNAL ;
    PORT
      LAYER M4 ;
        RECT  0 64.368 0.084 64.392 ;
    END
  END rr_data[62]
  PIN rr_data[63]
    DIRECTION INPUT ;
    USE SIGNAL ;
    PORT
      LAYER M4 ;
        RECT  0 64.464 0.084 64.488 ;
    END
  END rr_data[63]
  PIN rr_data[64]
    DIRECTION INPUT ;
    USE SIGNAL ;
    PORT
      LAYER M4 ;
        RECT  0 58.416 0.084 58.44 ;
    END
  END rr_data[64]
  PIN rr_data[65]
    DIRECTION INPUT ;
    USE SIGNAL ;
    PORT
      LAYER M4 ;
        RECT  0 58.512 0.084 58.536 ;
    END
  END rr_data[65]
  PIN rr_data[66]
    DIRECTION INPUT ;
    USE SIGNAL ;
    PORT
      LAYER M4 ;
        RECT  0 58.608 0.084 58.632 ;
    END
  END rr_data[66]
  PIN rr_data[67]
    DIRECTION INPUT ;
    USE SIGNAL ;
    PORT
      LAYER M4 ;
        RECT  0 58.704 0.084 58.728 ;
    END
  END rr_data[67]
  PIN rr_data[68]
    DIRECTION INPUT ;
    USE SIGNAL ;
    PORT
      LAYER M4 ;
        RECT  0 58.8 0.084 58.824 ;
    END
  END rr_data[68]
  PIN rr_data[69]
    DIRECTION INPUT ;
    USE SIGNAL ;
    PORT
      LAYER M4 ;
        RECT  0 58.896 0.084 58.92 ;
    END
  END rr_data[69]
  PIN rr_data[6]
    DIRECTION INPUT ;
    USE SIGNAL ;
    PORT
      LAYER M4 ;
        RECT  0 55.92 0.084 55.944 ;
    END
  END rr_data[6]
  PIN rr_data[70]
    DIRECTION INPUT ;
    USE SIGNAL ;
    PORT
      LAYER M4 ;
        RECT  0 58.992 0.084 59.016 ;
    END
  END rr_data[70]
  PIN rr_data[71]
    DIRECTION INPUT ;
    USE SIGNAL ;
    PORT
      LAYER M4 ;
        RECT  0 59.088 0.084 59.112 ;
    END
  END rr_data[71]
  PIN rr_data[72]
    DIRECTION INPUT ;
    USE SIGNAL ;
    PORT
      LAYER M4 ;
        RECT  0 59.184 0.084 59.208 ;
    END
  END rr_data[72]
  PIN rr_data[73]
    DIRECTION INPUT ;
    USE SIGNAL ;
    PORT
      LAYER M4 ;
        RECT  0 59.28 0.084 59.304 ;
    END
  END rr_data[73]
  PIN rr_data[74]
    DIRECTION INPUT ;
    USE SIGNAL ;
    PORT
      LAYER M4 ;
        RECT  0 59.376 0.084 59.4 ;
    END
  END rr_data[74]
  PIN rr_data[75]
    DIRECTION INPUT ;
    USE SIGNAL ;
    PORT
      LAYER M4 ;
        RECT  0 59.472 0.084 59.496 ;
    END
  END rr_data[75]
  PIN rr_data[76]
    DIRECTION INPUT ;
    USE SIGNAL ;
    PORT
      LAYER M4 ;
        RECT  0 59.568 0.084 59.592 ;
    END
  END rr_data[76]
  PIN rr_data[77]
    DIRECTION INPUT ;
    USE SIGNAL ;
    PORT
      LAYER M4 ;
        RECT  0 59.664 0.084 59.688 ;
    END
  END rr_data[77]
  PIN rr_data[78]
    DIRECTION INPUT ;
    USE SIGNAL ;
    PORT
      LAYER M4 ;
        RECT  0 59.76 0.084 59.784 ;
    END
  END rr_data[78]
  PIN rr_data[79]
    DIRECTION INPUT ;
    USE SIGNAL ;
    PORT
      LAYER M4 ;
        RECT  0 59.856 0.084 59.88 ;
    END
  END rr_data[79]
  PIN rr_data[7]
    DIRECTION INPUT ;
    USE SIGNAL ;
    PORT
      LAYER M4 ;
        RECT  0 56.016 0.084 56.04 ;
    END
  END rr_data[7]
  PIN rr_data[80]
    DIRECTION INPUT ;
    USE SIGNAL ;
    PORT
      LAYER M4 ;
        RECT  0 59.952 0.084 59.976 ;
    END
  END rr_data[80]
  PIN rr_data[81]
    DIRECTION INPUT ;
    USE SIGNAL ;
    PORT
      LAYER M4 ;
        RECT  0 60.048 0.084 60.072 ;
    END
  END rr_data[81]
  PIN rr_data[82]
    DIRECTION INPUT ;
    USE SIGNAL ;
    PORT
      LAYER M4 ;
        RECT  0 60.144 0.084 60.168 ;
    END
  END rr_data[82]
  PIN rr_data[83]
    DIRECTION INPUT ;
    USE SIGNAL ;
    PORT
      LAYER M4 ;
        RECT  0 60.24 0.084 60.264 ;
    END
  END rr_data[83]
  PIN rr_data[84]
    DIRECTION INPUT ;
    USE SIGNAL ;
    PORT
      LAYER M4 ;
        RECT  0 60.336 0.084 60.36 ;
    END
  END rr_data[84]
  PIN rr_data[85]
    DIRECTION INPUT ;
    USE SIGNAL ;
    PORT
      LAYER M4 ;
        RECT  0 60.432 0.084 60.456 ;
    END
  END rr_data[85]
  PIN rr_data[86]
    DIRECTION INPUT ;
    USE SIGNAL ;
    PORT
      LAYER M4 ;
        RECT  0 60.528 0.084 60.552 ;
    END
  END rr_data[86]
  PIN rr_data[87]
    DIRECTION INPUT ;
    USE SIGNAL ;
    PORT
      LAYER M4 ;
        RECT  0 60.624 0.084 60.648 ;
    END
  END rr_data[87]
  PIN rr_data[88]
    DIRECTION INPUT ;
    USE SIGNAL ;
    PORT
      LAYER M4 ;
        RECT  0 60.72 0.084 60.744 ;
    END
  END rr_data[88]
  PIN rr_data[89]
    DIRECTION INPUT ;
    USE SIGNAL ;
    PORT
      LAYER M4 ;
        RECT  0 60.816 0.084 60.84 ;
    END
  END rr_data[89]
  PIN rr_data[8]
    DIRECTION INPUT ;
    USE SIGNAL ;
    PORT
      LAYER M4 ;
        RECT  0 56.112 0.084 56.136 ;
    END
  END rr_data[8]
  PIN rr_data[90]
    DIRECTION INPUT ;
    USE SIGNAL ;
    PORT
      LAYER M4 ;
        RECT  0 60.912 0.084 60.936 ;
    END
  END rr_data[90]
  PIN rr_data[91]
    DIRECTION INPUT ;
    USE SIGNAL ;
    PORT
      LAYER M4 ;
        RECT  0 61.008 0.084 61.032 ;
    END
  END rr_data[91]
  PIN rr_data[92]
    DIRECTION INPUT ;
    USE SIGNAL ;
    PORT
      LAYER M4 ;
        RECT  0 61.104 0.084 61.128 ;
    END
  END rr_data[92]
  PIN rr_data[93]
    DIRECTION INPUT ;
    USE SIGNAL ;
    PORT
      LAYER M4 ;
        RECT  0 61.2 0.084 61.224 ;
    END
  END rr_data[93]
  PIN rr_data[94]
    DIRECTION INPUT ;
    USE SIGNAL ;
    PORT
      LAYER M4 ;
        RECT  0 61.296 0.084 61.32 ;
    END
  END rr_data[94]
  PIN rr_data[95]
    DIRECTION INPUT ;
    USE SIGNAL ;
    PORT
      LAYER M4 ;
        RECT  0 61.392 0.084 61.416 ;
    END
  END rr_data[95]
  PIN rr_data[96]
    DIRECTION INPUT ;
    USE SIGNAL ;
    PORT
      LAYER M4 ;
        RECT  0 64.56 0.084 64.584 ;
    END
  END rr_data[96]
  PIN rr_data[97]
    DIRECTION INPUT ;
    USE SIGNAL ;
    PORT
      LAYER M4 ;
        RECT  0 64.656 0.084 64.68 ;
    END
  END rr_data[97]
  PIN rr_data[98]
    DIRECTION INPUT ;
    USE SIGNAL ;
    PORT
      LAYER M4 ;
        RECT  0 64.752 0.084 64.776 ;
    END
  END rr_data[98]
  PIN rr_data[99]
    DIRECTION INPUT ;
    USE SIGNAL ;
    PORT
      LAYER M4 ;
        RECT  0 64.848 0.084 64.872 ;
    END
  END rr_data[99]
  PIN rr_data[9]
    DIRECTION INPUT ;
    USE SIGNAL ;
    PORT
      LAYER M4 ;
        RECT  0 56.208 0.084 56.232 ;
    END
  END rr_data[9]
  PIN rst_n
    DIRECTION INPUT ;
    USE SIGNAL ;
    PORT
      LAYER M5 ;
        RECT  5.904 87.396 5.928 87.48 ;
    END
  END rst_n
  PIN wd[0]
    DIRECTION OUTPUT ;
    USE SIGNAL ;
    PORT
      LAYER M4 ;
        RECT  0 13.872 0.084 13.896 ;
    END
  END wd[0]
  PIN wd[100]
    DIRECTION OUTPUT ;
    USE SIGNAL ;
    PORT
      LAYER M4 ;
        RECT  0 36.528 0.084 36.552 ;
    END
  END wd[100]
  PIN wd[101]
    DIRECTION OUTPUT ;
    USE SIGNAL ;
    PORT
      LAYER M4 ;
        RECT  0 36.624 0.084 36.648 ;
    END
  END wd[101]
  PIN wd[102]
    DIRECTION OUTPUT ;
    USE SIGNAL ;
    PORT
      LAYER M4 ;
        RECT  0 36.72 0.084 36.744 ;
    END
  END wd[102]
  PIN wd[103]
    DIRECTION OUTPUT ;
    USE SIGNAL ;
    PORT
      LAYER M4 ;
        RECT  0 36.816 0.084 36.84 ;
    END
  END wd[103]
  PIN wd[104]
    DIRECTION OUTPUT ;
    USE SIGNAL ;
    PORT
      LAYER M4 ;
        RECT  0 36.912 0.084 36.936 ;
    END
  END wd[104]
  PIN wd[105]
    DIRECTION OUTPUT ;
    USE SIGNAL ;
    PORT
      LAYER M4 ;
        RECT  0 37.008 0.084 37.032 ;
    END
  END wd[105]
  PIN wd[106]
    DIRECTION OUTPUT ;
    USE SIGNAL ;
    PORT
      LAYER M4 ;
        RECT  0 37.104 0.084 37.128 ;
    END
  END wd[106]
  PIN wd[107]
    DIRECTION OUTPUT ;
    USE SIGNAL ;
    PORT
      LAYER M4 ;
        RECT  0 37.2 0.084 37.224 ;
    END
  END wd[107]
  PIN wd[108]
    DIRECTION OUTPUT ;
    USE SIGNAL ;
    PORT
      LAYER M4 ;
        RECT  0 37.296 0.084 37.32 ;
    END
  END wd[108]
  PIN wd[109]
    DIRECTION OUTPUT ;
    USE SIGNAL ;
    PORT
      LAYER M4 ;
        RECT  0 37.392 0.084 37.416 ;
    END
  END wd[109]
  PIN wd[10]
    DIRECTION OUTPUT ;
    USE SIGNAL ;
    PORT
      LAYER M4 ;
        RECT  0 14.832 0.084 14.856 ;
    END
  END wd[10]
  PIN wd[110]
    DIRECTION OUTPUT ;
    USE SIGNAL ;
    PORT
      LAYER M4 ;
        RECT  0 37.488 0.084 37.512 ;
    END
  END wd[110]
  PIN wd[111]
    DIRECTION OUTPUT ;
    USE SIGNAL ;
    PORT
      LAYER M4 ;
        RECT  0 37.584 0.084 37.608 ;
    END
  END wd[111]
  PIN wd[112]
    DIRECTION OUTPUT ;
    USE SIGNAL ;
    PORT
      LAYER M4 ;
        RECT  0 37.68 0.084 37.704 ;
    END
  END wd[112]
  PIN wd[113]
    DIRECTION OUTPUT ;
    USE SIGNAL ;
    PORT
      LAYER M4 ;
        RECT  0 37.776 0.084 37.8 ;
    END
  END wd[113]
  PIN wd[114]
    DIRECTION OUTPUT ;
    USE SIGNAL ;
    PORT
      LAYER M4 ;
        RECT  0 37.872 0.084 37.896 ;
    END
  END wd[114]
  PIN wd[115]
    DIRECTION OUTPUT ;
    USE SIGNAL ;
    PORT
      LAYER M4 ;
        RECT  0 37.968 0.084 37.992 ;
    END
  END wd[115]
  PIN wd[116]
    DIRECTION OUTPUT ;
    USE SIGNAL ;
    PORT
      LAYER M4 ;
        RECT  0 38.064 0.084 38.088 ;
    END
  END wd[116]
  PIN wd[117]
    DIRECTION OUTPUT ;
    USE SIGNAL ;
    PORT
      LAYER M4 ;
        RECT  0 38.16 0.084 38.184 ;
    END
  END wd[117]
  PIN wd[118]
    DIRECTION OUTPUT ;
    USE SIGNAL ;
    PORT
      LAYER M4 ;
        RECT  0 38.256 0.084 38.28 ;
    END
  END wd[118]
  PIN wd[119]
    DIRECTION OUTPUT ;
    USE SIGNAL ;
    PORT
      LAYER M4 ;
        RECT  0 38.352 0.084 38.376 ;
    END
  END wd[119]
  PIN wd[11]
    DIRECTION OUTPUT ;
    USE SIGNAL ;
    PORT
      LAYER M4 ;
        RECT  0 14.928 0.084 14.952 ;
    END
  END wd[11]
  PIN wd[120]
    DIRECTION OUTPUT ;
    USE SIGNAL ;
    PORT
      LAYER M4 ;
        RECT  0 38.448 0.084 38.472 ;
    END
  END wd[120]
  PIN wd[121]
    DIRECTION OUTPUT ;
    USE SIGNAL ;
    PORT
      LAYER M4 ;
        RECT  0 38.544 0.084 38.568 ;
    END
  END wd[121]
  PIN wd[122]
    DIRECTION OUTPUT ;
    USE SIGNAL ;
    PORT
      LAYER M4 ;
        RECT  0 38.64 0.084 38.664 ;
    END
  END wd[122]
  PIN wd[123]
    DIRECTION OUTPUT ;
    USE SIGNAL ;
    PORT
      LAYER M4 ;
        RECT  0 38.736 0.084 38.76 ;
    END
  END wd[123]
  PIN wd[124]
    DIRECTION OUTPUT ;
    USE SIGNAL ;
    PORT
      LAYER M4 ;
        RECT  0 38.832 0.084 38.856 ;
    END
  END wd[124]
  PIN wd[125]
    DIRECTION OUTPUT ;
    USE SIGNAL ;
    PORT
      LAYER M4 ;
        RECT  0 38.928 0.084 38.952 ;
    END
  END wd[125]
  PIN wd[126]
    DIRECTION OUTPUT ;
    USE SIGNAL ;
    PORT
      LAYER M4 ;
        RECT  0 39.024 0.084 39.048 ;
    END
  END wd[126]
  PIN wd[127]
    DIRECTION OUTPUT ;
    USE SIGNAL ;
    PORT
      LAYER M4 ;
        RECT  0 39.12 0.084 39.144 ;
    END
  END wd[127]
  PIN wd[128]
    DIRECTION OUTPUT ;
    USE SIGNAL ;
    PORT
      LAYER M4 ;
        RECT  0 39.216 0.084 39.24 ;
    END
  END wd[128]
  PIN wd[129]
    DIRECTION OUTPUT ;
    USE SIGNAL ;
    PORT
      LAYER M4 ;
        RECT  0 39.312 0.084 39.336 ;
    END
  END wd[129]
  PIN wd[12]
    DIRECTION OUTPUT ;
    USE SIGNAL ;
    PORT
      LAYER M4 ;
        RECT  0 15.024 0.084 15.048 ;
    END
  END wd[12]
  PIN wd[130]
    DIRECTION OUTPUT ;
    USE SIGNAL ;
    PORT
      LAYER M4 ;
        RECT  0 39.408 0.084 39.432 ;
    END
  END wd[130]
  PIN wd[131]
    DIRECTION OUTPUT ;
    USE SIGNAL ;
    PORT
      LAYER M4 ;
        RECT  0 39.504 0.084 39.528 ;
    END
  END wd[131]
  PIN wd[132]
    DIRECTION OUTPUT ;
    USE SIGNAL ;
    PORT
      LAYER M4 ;
        RECT  0 39.6 0.084 39.624 ;
    END
  END wd[132]
  PIN wd[133]
    DIRECTION OUTPUT ;
    USE SIGNAL ;
    PORT
      LAYER M4 ;
        RECT  0 39.696 0.084 39.72 ;
    END
  END wd[133]
  PIN wd[134]
    DIRECTION OUTPUT ;
    USE SIGNAL ;
    PORT
      LAYER M4 ;
        RECT  0 39.792 0.084 39.816 ;
    END
  END wd[134]
  PIN wd[135]
    DIRECTION OUTPUT ;
    USE SIGNAL ;
    PORT
      LAYER M4 ;
        RECT  0 39.888 0.084 39.912 ;
    END
  END wd[135]
  PIN wd[136]
    DIRECTION OUTPUT ;
    USE SIGNAL ;
    PORT
      LAYER M4 ;
        RECT  0 39.984 0.084 40.008 ;
    END
  END wd[136]
  PIN wd[137]
    DIRECTION OUTPUT ;
    USE SIGNAL ;
    PORT
      LAYER M4 ;
        RECT  0 40.08 0.084 40.104 ;
    END
  END wd[137]
  PIN wd[138]
    DIRECTION OUTPUT ;
    USE SIGNAL ;
    PORT
      LAYER M4 ;
        RECT  0 40.176 0.084 40.2 ;
    END
  END wd[138]
  PIN wd[139]
    DIRECTION OUTPUT ;
    USE SIGNAL ;
    PORT
      LAYER M4 ;
        RECT  0 40.272 0.084 40.296 ;
    END
  END wd[139]
  PIN wd[13]
    DIRECTION OUTPUT ;
    USE SIGNAL ;
    PORT
      LAYER M4 ;
        RECT  0 15.12 0.084 15.144 ;
    END
  END wd[13]
  PIN wd[140]
    DIRECTION OUTPUT ;
    USE SIGNAL ;
    PORT
      LAYER M4 ;
        RECT  0 40.368 0.084 40.392 ;
    END
  END wd[140]
  PIN wd[141]
    DIRECTION OUTPUT ;
    USE SIGNAL ;
    PORT
      LAYER M4 ;
        RECT  0 40.464 0.084 40.488 ;
    END
  END wd[141]
  PIN wd[142]
    DIRECTION OUTPUT ;
    USE SIGNAL ;
    PORT
      LAYER M4 ;
        RECT  0 40.56 0.084 40.584 ;
    END
  END wd[142]
  PIN wd[143]
    DIRECTION OUTPUT ;
    USE SIGNAL ;
    PORT
      LAYER M4 ;
        RECT  0 40.656 0.084 40.68 ;
    END
  END wd[143]
  PIN wd[144]
    DIRECTION OUTPUT ;
    USE SIGNAL ;
    PORT
      LAYER M4 ;
        RECT  0 40.752 0.084 40.776 ;
    END
  END wd[144]
  PIN wd[145]
    DIRECTION OUTPUT ;
    USE SIGNAL ;
    PORT
      LAYER M4 ;
        RECT  0 40.848 0.084 40.872 ;
    END
  END wd[145]
  PIN wd[146]
    DIRECTION OUTPUT ;
    USE SIGNAL ;
    PORT
      LAYER M4 ;
        RECT  0 40.944 0.084 40.968 ;
    END
  END wd[146]
  PIN wd[147]
    DIRECTION OUTPUT ;
    USE SIGNAL ;
    PORT
      LAYER M4 ;
        RECT  0 41.04 0.084 41.064 ;
    END
  END wd[147]
  PIN wd[148]
    DIRECTION OUTPUT ;
    USE SIGNAL ;
    PORT
      LAYER M4 ;
        RECT  0 41.136 0.084 41.16 ;
    END
  END wd[148]
  PIN wd[149]
    DIRECTION OUTPUT ;
    USE SIGNAL ;
    PORT
      LAYER M4 ;
        RECT  0 41.232 0.084 41.256 ;
    END
  END wd[149]
  PIN wd[14]
    DIRECTION OUTPUT ;
    USE SIGNAL ;
    PORT
      LAYER M4 ;
        RECT  0 15.216 0.084 15.24 ;
    END
  END wd[14]
  PIN wd[150]
    DIRECTION OUTPUT ;
    USE SIGNAL ;
    PORT
      LAYER M4 ;
        RECT  0 41.328 0.084 41.352 ;
    END
  END wd[150]
  PIN wd[151]
    DIRECTION OUTPUT ;
    USE SIGNAL ;
    PORT
      LAYER M4 ;
        RECT  0 41.424 0.084 41.448 ;
    END
  END wd[151]
  PIN wd[152]
    DIRECTION OUTPUT ;
    USE SIGNAL ;
    PORT
      LAYER M4 ;
        RECT  0 41.52 0.084 41.544 ;
    END
  END wd[152]
  PIN wd[153]
    DIRECTION OUTPUT ;
    USE SIGNAL ;
    PORT
      LAYER M4 ;
        RECT  0 41.616 0.084 41.64 ;
    END
  END wd[153]
  PIN wd[154]
    DIRECTION OUTPUT ;
    USE SIGNAL ;
    PORT
      LAYER M4 ;
        RECT  0 41.712 0.084 41.736 ;
    END
  END wd[154]
  PIN wd[155]
    DIRECTION OUTPUT ;
    USE SIGNAL ;
    PORT
      LAYER M4 ;
        RECT  0 41.808 0.084 41.832 ;
    END
  END wd[155]
  PIN wd[156]
    DIRECTION OUTPUT ;
    USE SIGNAL ;
    PORT
      LAYER M4 ;
        RECT  0 41.904 0.084 41.928 ;
    END
  END wd[156]
  PIN wd[157]
    DIRECTION OUTPUT ;
    USE SIGNAL ;
    PORT
      LAYER M4 ;
        RECT  0 42 0.084 42.024 ;
    END
  END wd[157]
  PIN wd[158]
    DIRECTION OUTPUT ;
    USE SIGNAL ;
    PORT
      LAYER M4 ;
        RECT  0 42.096 0.084 42.12 ;
    END
  END wd[158]
  PIN wd[159]
    DIRECTION OUTPUT ;
    USE SIGNAL ;
    PORT
      LAYER M4 ;
        RECT  0 42.192 0.084 42.216 ;
    END
  END wd[159]
  PIN wd[15]
    DIRECTION OUTPUT ;
    USE SIGNAL ;
    PORT
      LAYER M4 ;
        RECT  0 15.312 0.084 15.336 ;
    END
  END wd[15]
  PIN wd[160]
    DIRECTION OUTPUT ;
    USE SIGNAL ;
    PORT
      LAYER M4 ;
        RECT  0 52.272 0.084 52.296 ;
    END
  END wd[160]
  PIN wd[161]
    DIRECTION OUTPUT ;
    USE SIGNAL ;
    PORT
      LAYER M4 ;
        RECT  0 52.368 0.084 52.392 ;
    END
  END wd[161]
  PIN wd[162]
    DIRECTION OUTPUT ;
    USE SIGNAL ;
    PORT
      LAYER M4 ;
        RECT  0 52.464 0.084 52.488 ;
    END
  END wd[162]
  PIN wd[163]
    DIRECTION OUTPUT ;
    USE SIGNAL ;
    PORT
      LAYER M4 ;
        RECT  0 52.56 0.084 52.584 ;
    END
  END wd[163]
  PIN wd[164]
    DIRECTION OUTPUT ;
    USE SIGNAL ;
    PORT
      LAYER M4 ;
        RECT  0 52.656 0.084 52.68 ;
    END
  END wd[164]
  PIN wd[165]
    DIRECTION OUTPUT ;
    USE SIGNAL ;
    PORT
      LAYER M4 ;
        RECT  0 52.752 0.084 52.776 ;
    END
  END wd[165]
  PIN wd[166]
    DIRECTION OUTPUT ;
    USE SIGNAL ;
    PORT
      LAYER M4 ;
        RECT  0 52.848 0.084 52.872 ;
    END
  END wd[166]
  PIN wd[167]
    DIRECTION OUTPUT ;
    USE SIGNAL ;
    PORT
      LAYER M4 ;
        RECT  0 52.944 0.084 52.968 ;
    END
  END wd[167]
  PIN wd[168]
    DIRECTION OUTPUT ;
    USE SIGNAL ;
    PORT
      LAYER M4 ;
        RECT  0 53.04 0.084 53.064 ;
    END
  END wd[168]
  PIN wd[169]
    DIRECTION OUTPUT ;
    USE SIGNAL ;
    PORT
      LAYER M4 ;
        RECT  0 53.136 0.084 53.16 ;
    END
  END wd[169]
  PIN wd[16]
    DIRECTION OUTPUT ;
    USE SIGNAL ;
    PORT
      LAYER M4 ;
        RECT  0 15.408 0.084 15.432 ;
    END
  END wd[16]
  PIN wd[170]
    DIRECTION OUTPUT ;
    USE SIGNAL ;
    PORT
      LAYER M4 ;
        RECT  0 53.232 0.084 53.256 ;
    END
  END wd[170]
  PIN wd[171]
    DIRECTION OUTPUT ;
    USE SIGNAL ;
    PORT
      LAYER M4 ;
        RECT  0 53.328 0.084 53.352 ;
    END
  END wd[171]
  PIN wd[172]
    DIRECTION OUTPUT ;
    USE SIGNAL ;
    PORT
      LAYER M4 ;
        RECT  0 53.424 0.084 53.448 ;
    END
  END wd[172]
  PIN wd[173]
    DIRECTION OUTPUT ;
    USE SIGNAL ;
    PORT
      LAYER M4 ;
        RECT  0 53.52 0.084 53.544 ;
    END
  END wd[173]
  PIN wd[174]
    DIRECTION OUTPUT ;
    USE SIGNAL ;
    PORT
      LAYER M4 ;
        RECT  0 53.616 0.084 53.64 ;
    END
  END wd[174]
  PIN wd[175]
    DIRECTION OUTPUT ;
    USE SIGNAL ;
    PORT
      LAYER M4 ;
        RECT  0 53.712 0.084 53.736 ;
    END
  END wd[175]
  PIN wd[176]
    DIRECTION OUTPUT ;
    USE SIGNAL ;
    PORT
      LAYER M4 ;
        RECT  0 53.808 0.084 53.832 ;
    END
  END wd[176]
  PIN wd[177]
    DIRECTION OUTPUT ;
    USE SIGNAL ;
    PORT
      LAYER M4 ;
        RECT  0 53.904 0.084 53.928 ;
    END
  END wd[177]
  PIN wd[178]
    DIRECTION OUTPUT ;
    USE SIGNAL ;
    PORT
      LAYER M4 ;
        RECT  0 54 0.084 54.024 ;
    END
  END wd[178]
  PIN wd[179]
    DIRECTION OUTPUT ;
    USE SIGNAL ;
    PORT
      LAYER M4 ;
        RECT  0 54.096 0.084 54.12 ;
    END
  END wd[179]
  PIN wd[17]
    DIRECTION OUTPUT ;
    USE SIGNAL ;
    PORT
      LAYER M4 ;
        RECT  0 15.504 0.084 15.528 ;
    END
  END wd[17]
  PIN wd[180]
    DIRECTION OUTPUT ;
    USE SIGNAL ;
    PORT
      LAYER M4 ;
        RECT  0 54.192 0.084 54.216 ;
    END
  END wd[180]
  PIN wd[181]
    DIRECTION OUTPUT ;
    USE SIGNAL ;
    PORT
      LAYER M4 ;
        RECT  0 54.288 0.084 54.312 ;
    END
  END wd[181]
  PIN wd[182]
    DIRECTION OUTPUT ;
    USE SIGNAL ;
    PORT
      LAYER M4 ;
        RECT  0 54.384 0.084 54.408 ;
    END
  END wd[182]
  PIN wd[183]
    DIRECTION OUTPUT ;
    USE SIGNAL ;
    PORT
      LAYER M4 ;
        RECT  0 54.48 0.084 54.504 ;
    END
  END wd[183]
  PIN wd[184]
    DIRECTION OUTPUT ;
    USE SIGNAL ;
    PORT
      LAYER M4 ;
        RECT  0 54.576 0.084 54.6 ;
    END
  END wd[184]
  PIN wd[185]
    DIRECTION OUTPUT ;
    USE SIGNAL ;
    PORT
      LAYER M4 ;
        RECT  0 54.672 0.084 54.696 ;
    END
  END wd[185]
  PIN wd[186]
    DIRECTION OUTPUT ;
    USE SIGNAL ;
    PORT
      LAYER M4 ;
        RECT  0 54.768 0.084 54.792 ;
    END
  END wd[186]
  PIN wd[187]
    DIRECTION OUTPUT ;
    USE SIGNAL ;
    PORT
      LAYER M4 ;
        RECT  0 54.864 0.084 54.888 ;
    END
  END wd[187]
  PIN wd[188]
    DIRECTION OUTPUT ;
    USE SIGNAL ;
    PORT
      LAYER M4 ;
        RECT  0 54.96 0.084 54.984 ;
    END
  END wd[188]
  PIN wd[189]
    DIRECTION OUTPUT ;
    USE SIGNAL ;
    PORT
      LAYER M4 ;
        RECT  0 55.056 0.084 55.08 ;
    END
  END wd[189]
  PIN wd[18]
    DIRECTION OUTPUT ;
    USE SIGNAL ;
    PORT
      LAYER M4 ;
        RECT  0 15.6 0.084 15.624 ;
    END
  END wd[18]
  PIN wd[190]
    DIRECTION OUTPUT ;
    USE SIGNAL ;
    PORT
      LAYER M4 ;
        RECT  0 55.152 0.084 55.176 ;
    END
  END wd[190]
  PIN wd[191]
    DIRECTION OUTPUT ;
    USE SIGNAL ;
    PORT
      LAYER M4 ;
        RECT  0 55.248 0.084 55.272 ;
    END
  END wd[191]
  PIN wd[192]
    DIRECTION OUTPUT ;
    USE SIGNAL ;
    PORT
      LAYER M4 ;
        RECT  0 49.2 0.084 49.224 ;
    END
  END wd[192]
  PIN wd[193]
    DIRECTION OUTPUT ;
    USE SIGNAL ;
    PORT
      LAYER M4 ;
        RECT  0 49.296 0.084 49.32 ;
    END
  END wd[193]
  PIN wd[194]
    DIRECTION OUTPUT ;
    USE SIGNAL ;
    PORT
      LAYER M4 ;
        RECT  0 49.392 0.084 49.416 ;
    END
  END wd[194]
  PIN wd[195]
    DIRECTION OUTPUT ;
    USE SIGNAL ;
    PORT
      LAYER M4 ;
        RECT  0 49.488 0.084 49.512 ;
    END
  END wd[195]
  PIN wd[196]
    DIRECTION OUTPUT ;
    USE SIGNAL ;
    PORT
      LAYER M4 ;
        RECT  0 49.584 0.084 49.608 ;
    END
  END wd[196]
  PIN wd[197]
    DIRECTION OUTPUT ;
    USE SIGNAL ;
    PORT
      LAYER M4 ;
        RECT  0 49.68 0.084 49.704 ;
    END
  END wd[197]
  PIN wd[198]
    DIRECTION OUTPUT ;
    USE SIGNAL ;
    PORT
      LAYER M4 ;
        RECT  0 49.776 0.084 49.8 ;
    END
  END wd[198]
  PIN wd[199]
    DIRECTION OUTPUT ;
    USE SIGNAL ;
    PORT
      LAYER M4 ;
        RECT  0 49.872 0.084 49.896 ;
    END
  END wd[199]
  PIN wd[19]
    DIRECTION OUTPUT ;
    USE SIGNAL ;
    PORT
      LAYER M4 ;
        RECT  0 15.696 0.084 15.72 ;
    END
  END wd[19]
  PIN wd[1]
    DIRECTION OUTPUT ;
    USE SIGNAL ;
    PORT
      LAYER M4 ;
        RECT  0 13.968 0.084 13.992 ;
    END
  END wd[1]
  PIN wd[200]
    DIRECTION OUTPUT ;
    USE SIGNAL ;
    PORT
      LAYER M4 ;
        RECT  0 49.968 0.084 49.992 ;
    END
  END wd[200]
  PIN wd[201]
    DIRECTION OUTPUT ;
    USE SIGNAL ;
    PORT
      LAYER M4 ;
        RECT  0 50.064 0.084 50.088 ;
    END
  END wd[201]
  PIN wd[202]
    DIRECTION OUTPUT ;
    USE SIGNAL ;
    PORT
      LAYER M4 ;
        RECT  0 50.16 0.084 50.184 ;
    END
  END wd[202]
  PIN wd[203]
    DIRECTION OUTPUT ;
    USE SIGNAL ;
    PORT
      LAYER M4 ;
        RECT  0 50.256 0.084 50.28 ;
    END
  END wd[203]
  PIN wd[204]
    DIRECTION OUTPUT ;
    USE SIGNAL ;
    PORT
      LAYER M4 ;
        RECT  0 50.352 0.084 50.376 ;
    END
  END wd[204]
  PIN wd[205]
    DIRECTION OUTPUT ;
    USE SIGNAL ;
    PORT
      LAYER M4 ;
        RECT  0 50.448 0.084 50.472 ;
    END
  END wd[205]
  PIN wd[206]
    DIRECTION OUTPUT ;
    USE SIGNAL ;
    PORT
      LAYER M4 ;
        RECT  0 50.544 0.084 50.568 ;
    END
  END wd[206]
  PIN wd[207]
    DIRECTION OUTPUT ;
    USE SIGNAL ;
    PORT
      LAYER M4 ;
        RECT  0 50.64 0.084 50.664 ;
    END
  END wd[207]
  PIN wd[208]
    DIRECTION OUTPUT ;
    USE SIGNAL ;
    PORT
      LAYER M4 ;
        RECT  0 50.736 0.084 50.76 ;
    END
  END wd[208]
  PIN wd[209]
    DIRECTION OUTPUT ;
    USE SIGNAL ;
    PORT
      LAYER M4 ;
        RECT  0 50.832 0.084 50.856 ;
    END
  END wd[209]
  PIN wd[20]
    DIRECTION OUTPUT ;
    USE SIGNAL ;
    PORT
      LAYER M4 ;
        RECT  0 15.792 0.084 15.816 ;
    END
  END wd[20]
  PIN wd[210]
    DIRECTION OUTPUT ;
    USE SIGNAL ;
    PORT
      LAYER M4 ;
        RECT  0 50.928 0.084 50.952 ;
    END
  END wd[210]
  PIN wd[211]
    DIRECTION OUTPUT ;
    USE SIGNAL ;
    PORT
      LAYER M4 ;
        RECT  0 51.024 0.084 51.048 ;
    END
  END wd[211]
  PIN wd[212]
    DIRECTION OUTPUT ;
    USE SIGNAL ;
    PORT
      LAYER M4 ;
        RECT  0 51.12 0.084 51.144 ;
    END
  END wd[212]
  PIN wd[213]
    DIRECTION OUTPUT ;
    USE SIGNAL ;
    PORT
      LAYER M4 ;
        RECT  0 51.216 0.084 51.24 ;
    END
  END wd[213]
  PIN wd[214]
    DIRECTION OUTPUT ;
    USE SIGNAL ;
    PORT
      LAYER M4 ;
        RECT  0 51.312 0.084 51.336 ;
    END
  END wd[214]
  PIN wd[215]
    DIRECTION OUTPUT ;
    USE SIGNAL ;
    PORT
      LAYER M4 ;
        RECT  0 51.408 0.084 51.432 ;
    END
  END wd[215]
  PIN wd[216]
    DIRECTION OUTPUT ;
    USE SIGNAL ;
    PORT
      LAYER M4 ;
        RECT  0 51.504 0.084 51.528 ;
    END
  END wd[216]
  PIN wd[217]
    DIRECTION OUTPUT ;
    USE SIGNAL ;
    PORT
      LAYER M4 ;
        RECT  0 51.6 0.084 51.624 ;
    END
  END wd[217]
  PIN wd[218]
    DIRECTION OUTPUT ;
    USE SIGNAL ;
    PORT
      LAYER M4 ;
        RECT  0 51.696 0.084 51.72 ;
    END
  END wd[218]
  PIN wd[219]
    DIRECTION OUTPUT ;
    USE SIGNAL ;
    PORT
      LAYER M4 ;
        RECT  0 51.792 0.084 51.816 ;
    END
  END wd[219]
  PIN wd[21]
    DIRECTION OUTPUT ;
    USE SIGNAL ;
    PORT
      LAYER M4 ;
        RECT  0 15.888 0.084 15.912 ;
    END
  END wd[21]
  PIN wd[220]
    DIRECTION OUTPUT ;
    USE SIGNAL ;
    PORT
      LAYER M4 ;
        RECT  0 51.888 0.084 51.912 ;
    END
  END wd[220]
  PIN wd[221]
    DIRECTION OUTPUT ;
    USE SIGNAL ;
    PORT
      LAYER M4 ;
        RECT  0 51.984 0.084 52.008 ;
    END
  END wd[221]
  PIN wd[222]
    DIRECTION OUTPUT ;
    USE SIGNAL ;
    PORT
      LAYER M4 ;
        RECT  0 52.08 0.084 52.104 ;
    END
  END wd[222]
  PIN wd[223]
    DIRECTION OUTPUT ;
    USE SIGNAL ;
    PORT
      LAYER M4 ;
        RECT  0 52.176 0.084 52.2 ;
    END
  END wd[223]
  PIN wd[224]
    DIRECTION OUTPUT ;
    USE SIGNAL ;
    PORT
      LAYER M4 ;
        RECT  0 26.16 0.084 26.184 ;
    END
  END wd[224]
  PIN wd[225]
    DIRECTION OUTPUT ;
    USE SIGNAL ;
    PORT
      LAYER M4 ;
        RECT  0 26.256 0.084 26.28 ;
    END
  END wd[225]
  PIN wd[226]
    DIRECTION OUTPUT ;
    USE SIGNAL ;
    PORT
      LAYER M4 ;
        RECT  0 26.352 0.084 26.376 ;
    END
  END wd[226]
  PIN wd[227]
    DIRECTION OUTPUT ;
    USE SIGNAL ;
    PORT
      LAYER M4 ;
        RECT  0 26.448 0.084 26.472 ;
    END
  END wd[227]
  PIN wd[228]
    DIRECTION OUTPUT ;
    USE SIGNAL ;
    PORT
      LAYER M4 ;
        RECT  0 26.544 0.084 26.568 ;
    END
  END wd[228]
  PIN wd[229]
    DIRECTION OUTPUT ;
    USE SIGNAL ;
    PORT
      LAYER M4 ;
        RECT  0 26.64 0.084 26.664 ;
    END
  END wd[229]
  PIN wd[22]
    DIRECTION OUTPUT ;
    USE SIGNAL ;
    PORT
      LAYER M4 ;
        RECT  0 15.984 0.084 16.008 ;
    END
  END wd[22]
  PIN wd[230]
    DIRECTION OUTPUT ;
    USE SIGNAL ;
    PORT
      LAYER M4 ;
        RECT  0 26.736 0.084 26.76 ;
    END
  END wd[230]
  PIN wd[231]
    DIRECTION OUTPUT ;
    USE SIGNAL ;
    PORT
      LAYER M4 ;
        RECT  0 26.832 0.084 26.856 ;
    END
  END wd[231]
  PIN wd[232]
    DIRECTION OUTPUT ;
    USE SIGNAL ;
    PORT
      LAYER M4 ;
        RECT  0 26.928 0.084 26.952 ;
    END
  END wd[232]
  PIN wd[233]
    DIRECTION OUTPUT ;
    USE SIGNAL ;
    PORT
      LAYER M4 ;
        RECT  0 27.024 0.084 27.048 ;
    END
  END wd[233]
  PIN wd[234]
    DIRECTION OUTPUT ;
    USE SIGNAL ;
    PORT
      LAYER M4 ;
        RECT  0 27.12 0.084 27.144 ;
    END
  END wd[234]
  PIN wd[235]
    DIRECTION OUTPUT ;
    USE SIGNAL ;
    PORT
      LAYER M4 ;
        RECT  0 27.216 0.084 27.24 ;
    END
  END wd[235]
  PIN wd[236]
    DIRECTION OUTPUT ;
    USE SIGNAL ;
    PORT
      LAYER M4 ;
        RECT  0 27.312 0.084 27.336 ;
    END
  END wd[236]
  PIN wd[237]
    DIRECTION OUTPUT ;
    USE SIGNAL ;
    PORT
      LAYER M4 ;
        RECT  0 27.408 0.084 27.432 ;
    END
  END wd[237]
  PIN wd[238]
    DIRECTION OUTPUT ;
    USE SIGNAL ;
    PORT
      LAYER M4 ;
        RECT  0 27.504 0.084 27.528 ;
    END
  END wd[238]
  PIN wd[239]
    DIRECTION OUTPUT ;
    USE SIGNAL ;
    PORT
      LAYER M4 ;
        RECT  0 27.6 0.084 27.624 ;
    END
  END wd[239]
  PIN wd[23]
    DIRECTION OUTPUT ;
    USE SIGNAL ;
    PORT
      LAYER M4 ;
        RECT  0 16.08 0.084 16.104 ;
    END
  END wd[23]
  PIN wd[240]
    DIRECTION OUTPUT ;
    USE SIGNAL ;
    PORT
      LAYER M4 ;
        RECT  0 27.696 0.084 27.72 ;
    END
  END wd[240]
  PIN wd[241]
    DIRECTION OUTPUT ;
    USE SIGNAL ;
    PORT
      LAYER M4 ;
        RECT  0 27.792 0.084 27.816 ;
    END
  END wd[241]
  PIN wd[242]
    DIRECTION OUTPUT ;
    USE SIGNAL ;
    PORT
      LAYER M4 ;
        RECT  0 27.888 0.084 27.912 ;
    END
  END wd[242]
  PIN wd[243]
    DIRECTION OUTPUT ;
    USE SIGNAL ;
    PORT
      LAYER M4 ;
        RECT  0 27.984 0.084 28.008 ;
    END
  END wd[243]
  PIN wd[244]
    DIRECTION OUTPUT ;
    USE SIGNAL ;
    PORT
      LAYER M4 ;
        RECT  0 28.08 0.084 28.104 ;
    END
  END wd[244]
  PIN wd[245]
    DIRECTION OUTPUT ;
    USE SIGNAL ;
    PORT
      LAYER M4 ;
        RECT  0 28.176 0.084 28.2 ;
    END
  END wd[245]
  PIN wd[246]
    DIRECTION OUTPUT ;
    USE SIGNAL ;
    PORT
      LAYER M4 ;
        RECT  0 28.272 0.084 28.296 ;
    END
  END wd[246]
  PIN wd[247]
    DIRECTION OUTPUT ;
    USE SIGNAL ;
    PORT
      LAYER M4 ;
        RECT  0 28.368 0.084 28.392 ;
    END
  END wd[247]
  PIN wd[248]
    DIRECTION OUTPUT ;
    USE SIGNAL ;
    PORT
      LAYER M4 ;
        RECT  0 28.464 0.084 28.488 ;
    END
  END wd[248]
  PIN wd[249]
    DIRECTION OUTPUT ;
    USE SIGNAL ;
    PORT
      LAYER M4 ;
        RECT  0 28.56 0.084 28.584 ;
    END
  END wd[249]
  PIN wd[24]
    DIRECTION OUTPUT ;
    USE SIGNAL ;
    PORT
      LAYER M4 ;
        RECT  0 16.176 0.084 16.2 ;
    END
  END wd[24]
  PIN wd[250]
    DIRECTION OUTPUT ;
    USE SIGNAL ;
    PORT
      LAYER M4 ;
        RECT  0 28.656 0.084 28.68 ;
    END
  END wd[250]
  PIN wd[251]
    DIRECTION OUTPUT ;
    USE SIGNAL ;
    PORT
      LAYER M4 ;
        RECT  0 28.752 0.084 28.776 ;
    END
  END wd[251]
  PIN wd[252]
    DIRECTION OUTPUT ;
    USE SIGNAL ;
    PORT
      LAYER M4 ;
        RECT  0 28.848 0.084 28.872 ;
    END
  END wd[252]
  PIN wd[253]
    DIRECTION OUTPUT ;
    USE SIGNAL ;
    PORT
      LAYER M4 ;
        RECT  0 28.944 0.084 28.968 ;
    END
  END wd[253]
  PIN wd[254]
    DIRECTION OUTPUT ;
    USE SIGNAL ;
    PORT
      LAYER M4 ;
        RECT  0 29.04 0.084 29.064 ;
    END
  END wd[254]
  PIN wd[255]
    DIRECTION OUTPUT ;
    USE SIGNAL ;
    PORT
      LAYER M4 ;
        RECT  0 29.136 0.084 29.16 ;
    END
  END wd[255]
  PIN wd[256]
    DIRECTION OUTPUT ;
    USE SIGNAL ;
    PORT
      LAYER M4 ;
        RECT  0 16.944 0.084 16.968 ;
    END
  END wd[256]
  PIN wd[257]
    DIRECTION OUTPUT ;
    USE SIGNAL ;
    PORT
      LAYER M4 ;
        RECT  0 17.04 0.084 17.064 ;
    END
  END wd[257]
  PIN wd[258]
    DIRECTION OUTPUT ;
    USE SIGNAL ;
    PORT
      LAYER M4 ;
        RECT  0 17.136 0.084 17.16 ;
    END
  END wd[258]
  PIN wd[259]
    DIRECTION OUTPUT ;
    USE SIGNAL ;
    PORT
      LAYER M4 ;
        RECT  0 17.232 0.084 17.256 ;
    END
  END wd[259]
  PIN wd[25]
    DIRECTION OUTPUT ;
    USE SIGNAL ;
    PORT
      LAYER M4 ;
        RECT  0 16.272 0.084 16.296 ;
    END
  END wd[25]
  PIN wd[260]
    DIRECTION OUTPUT ;
    USE SIGNAL ;
    PORT
      LAYER M4 ;
        RECT  0 17.328 0.084 17.352 ;
    END
  END wd[260]
  PIN wd[261]
    DIRECTION OUTPUT ;
    USE SIGNAL ;
    PORT
      LAYER M4 ;
        RECT  0 17.424 0.084 17.448 ;
    END
  END wd[261]
  PIN wd[262]
    DIRECTION OUTPUT ;
    USE SIGNAL ;
    PORT
      LAYER M4 ;
        RECT  0 17.52 0.084 17.544 ;
    END
  END wd[262]
  PIN wd[263]
    DIRECTION OUTPUT ;
    USE SIGNAL ;
    PORT
      LAYER M4 ;
        RECT  0 17.616 0.084 17.64 ;
    END
  END wd[263]
  PIN wd[264]
    DIRECTION OUTPUT ;
    USE SIGNAL ;
    PORT
      LAYER M4 ;
        RECT  0 17.712 0.084 17.736 ;
    END
  END wd[264]
  PIN wd[265]
    DIRECTION OUTPUT ;
    USE SIGNAL ;
    PORT
      LAYER M4 ;
        RECT  0 17.808 0.084 17.832 ;
    END
  END wd[265]
  PIN wd[266]
    DIRECTION OUTPUT ;
    USE SIGNAL ;
    PORT
      LAYER M4 ;
        RECT  0 17.904 0.084 17.928 ;
    END
  END wd[266]
  PIN wd[267]
    DIRECTION OUTPUT ;
    USE SIGNAL ;
    PORT
      LAYER M4 ;
        RECT  0 18 0.084 18.024 ;
    END
  END wd[267]
  PIN wd[268]
    DIRECTION OUTPUT ;
    USE SIGNAL ;
    PORT
      LAYER M4 ;
        RECT  0 18.096 0.084 18.12 ;
    END
  END wd[268]
  PIN wd[269]
    DIRECTION OUTPUT ;
    USE SIGNAL ;
    PORT
      LAYER M4 ;
        RECT  0 18.192 0.084 18.216 ;
    END
  END wd[269]
  PIN wd[26]
    DIRECTION OUTPUT ;
    USE SIGNAL ;
    PORT
      LAYER M4 ;
        RECT  0 16.368 0.084 16.392 ;
    END
  END wd[26]
  PIN wd[270]
    DIRECTION OUTPUT ;
    USE SIGNAL ;
    PORT
      LAYER M4 ;
        RECT  0 18.288 0.084 18.312 ;
    END
  END wd[270]
  PIN wd[271]
    DIRECTION OUTPUT ;
    USE SIGNAL ;
    PORT
      LAYER M4 ;
        RECT  0 18.384 0.084 18.408 ;
    END
  END wd[271]
  PIN wd[272]
    DIRECTION OUTPUT ;
    USE SIGNAL ;
    PORT
      LAYER M4 ;
        RECT  0 18.48 0.084 18.504 ;
    END
  END wd[272]
  PIN wd[273]
    DIRECTION OUTPUT ;
    USE SIGNAL ;
    PORT
      LAYER M4 ;
        RECT  0 18.576 0.084 18.6 ;
    END
  END wd[273]
  PIN wd[274]
    DIRECTION OUTPUT ;
    USE SIGNAL ;
    PORT
      LAYER M4 ;
        RECT  0 18.672 0.084 18.696 ;
    END
  END wd[274]
  PIN wd[275]
    DIRECTION OUTPUT ;
    USE SIGNAL ;
    PORT
      LAYER M4 ;
        RECT  0 18.768 0.084 18.792 ;
    END
  END wd[275]
  PIN wd[276]
    DIRECTION OUTPUT ;
    USE SIGNAL ;
    PORT
      LAYER M4 ;
        RECT  0 18.864 0.084 18.888 ;
    END
  END wd[276]
  PIN wd[277]
    DIRECTION OUTPUT ;
    USE SIGNAL ;
    PORT
      LAYER M4 ;
        RECT  0 18.96 0.084 18.984 ;
    END
  END wd[277]
  PIN wd[278]
    DIRECTION OUTPUT ;
    USE SIGNAL ;
    PORT
      LAYER M4 ;
        RECT  0 19.056 0.084 19.08 ;
    END
  END wd[278]
  PIN wd[279]
    DIRECTION OUTPUT ;
    USE SIGNAL ;
    PORT
      LAYER M4 ;
        RECT  0 19.152 0.084 19.176 ;
    END
  END wd[279]
  PIN wd[27]
    DIRECTION OUTPUT ;
    USE SIGNAL ;
    PORT
      LAYER M4 ;
        RECT  0 16.464 0.084 16.488 ;
    END
  END wd[27]
  PIN wd[280]
    DIRECTION OUTPUT ;
    USE SIGNAL ;
    PORT
      LAYER M4 ;
        RECT  0 19.248 0.084 19.272 ;
    END
  END wd[280]
  PIN wd[281]
    DIRECTION OUTPUT ;
    USE SIGNAL ;
    PORT
      LAYER M4 ;
        RECT  0 19.344 0.084 19.368 ;
    END
  END wd[281]
  PIN wd[282]
    DIRECTION OUTPUT ;
    USE SIGNAL ;
    PORT
      LAYER M4 ;
        RECT  0 19.44 0.084 19.464 ;
    END
  END wd[282]
  PIN wd[283]
    DIRECTION OUTPUT ;
    USE SIGNAL ;
    PORT
      LAYER M4 ;
        RECT  0 19.536 0.084 19.56 ;
    END
  END wd[283]
  PIN wd[284]
    DIRECTION OUTPUT ;
    USE SIGNAL ;
    PORT
      LAYER M4 ;
        RECT  0 19.632 0.084 19.656 ;
    END
  END wd[284]
  PIN wd[285]
    DIRECTION OUTPUT ;
    USE SIGNAL ;
    PORT
      LAYER M4 ;
        RECT  0 19.728 0.084 19.752 ;
    END
  END wd[285]
  PIN wd[286]
    DIRECTION OUTPUT ;
    USE SIGNAL ;
    PORT
      LAYER M4 ;
        RECT  0 19.824 0.084 19.848 ;
    END
  END wd[286]
  PIN wd[287]
    DIRECTION OUTPUT ;
    USE SIGNAL ;
    PORT
      LAYER M4 ;
        RECT  0 19.92 0.084 19.944 ;
    END
  END wd[287]
  PIN wd[288]
    DIRECTION OUTPUT ;
    USE SIGNAL ;
    PORT
      LAYER M4 ;
        RECT  0 29.904 0.084 29.928 ;
    END
  END wd[288]
  PIN wd[28]
    DIRECTION OUTPUT ;
    USE SIGNAL ;
    PORT
      LAYER M4 ;
        RECT  0 16.56 0.084 16.584 ;
    END
  END wd[28]
  PIN wd[29]
    DIRECTION OUTPUT ;
    USE SIGNAL ;
    PORT
      LAYER M4 ;
        RECT  0 16.656 0.084 16.68 ;
    END
  END wd[29]
  PIN wd[2]
    DIRECTION OUTPUT ;
    USE SIGNAL ;
    PORT
      LAYER M4 ;
        RECT  0 14.064 0.084 14.088 ;
    END
  END wd[2]
  PIN wd[30]
    DIRECTION OUTPUT ;
    USE SIGNAL ;
    PORT
      LAYER M4 ;
        RECT  0 16.752 0.084 16.776 ;
    END
  END wd[30]
  PIN wd[31]
    DIRECTION OUTPUT ;
    USE SIGNAL ;
    PORT
      LAYER M4 ;
        RECT  0 16.848 0.084 16.872 ;
    END
  END wd[31]
  PIN wd[32]
    DIRECTION OUTPUT ;
    USE SIGNAL ;
    PORT
      LAYER M4 ;
        RECT  0 30 0.084 30.024 ;
    END
  END wd[32]
  PIN wd[33]
    DIRECTION OUTPUT ;
    USE SIGNAL ;
    PORT
      LAYER M4 ;
        RECT  0 30.096 0.084 30.12 ;
    END
  END wd[33]
  PIN wd[34]
    DIRECTION OUTPUT ;
    USE SIGNAL ;
    PORT
      LAYER M4 ;
        RECT  0 30.192 0.084 30.216 ;
    END
  END wd[34]
  PIN wd[35]
    DIRECTION OUTPUT ;
    USE SIGNAL ;
    PORT
      LAYER M4 ;
        RECT  0 30.288 0.084 30.312 ;
    END
  END wd[35]
  PIN wd[36]
    DIRECTION OUTPUT ;
    USE SIGNAL ;
    PORT
      LAYER M4 ;
        RECT  0 30.384 0.084 30.408 ;
    END
  END wd[36]
  PIN wd[37]
    DIRECTION OUTPUT ;
    USE SIGNAL ;
    PORT
      LAYER M4 ;
        RECT  0 30.48 0.084 30.504 ;
    END
  END wd[37]
  PIN wd[38]
    DIRECTION OUTPUT ;
    USE SIGNAL ;
    PORT
      LAYER M4 ;
        RECT  0 30.576 0.084 30.6 ;
    END
  END wd[38]
  PIN wd[39]
    DIRECTION OUTPUT ;
    USE SIGNAL ;
    PORT
      LAYER M4 ;
        RECT  0 30.672 0.084 30.696 ;
    END
  END wd[39]
  PIN wd[3]
    DIRECTION OUTPUT ;
    USE SIGNAL ;
    PORT
      LAYER M4 ;
        RECT  0 14.16 0.084 14.184 ;
    END
  END wd[3]
  PIN wd[40]
    DIRECTION OUTPUT ;
    USE SIGNAL ;
    PORT
      LAYER M4 ;
        RECT  0 30.768 0.084 30.792 ;
    END
  END wd[40]
  PIN wd[41]
    DIRECTION OUTPUT ;
    USE SIGNAL ;
    PORT
      LAYER M4 ;
        RECT  0 30.864 0.084 30.888 ;
    END
  END wd[41]
  PIN wd[42]
    DIRECTION OUTPUT ;
    USE SIGNAL ;
    PORT
      LAYER M4 ;
        RECT  0 30.96 0.084 30.984 ;
    END
  END wd[42]
  PIN wd[43]
    DIRECTION OUTPUT ;
    USE SIGNAL ;
    PORT
      LAYER M4 ;
        RECT  0 31.056 0.084 31.08 ;
    END
  END wd[43]
  PIN wd[44]
    DIRECTION OUTPUT ;
    USE SIGNAL ;
    PORT
      LAYER M4 ;
        RECT  0 31.152 0.084 31.176 ;
    END
  END wd[44]
  PIN wd[45]
    DIRECTION OUTPUT ;
    USE SIGNAL ;
    PORT
      LAYER M4 ;
        RECT  0 31.248 0.084 31.272 ;
    END
  END wd[45]
  PIN wd[46]
    DIRECTION OUTPUT ;
    USE SIGNAL ;
    PORT
      LAYER M4 ;
        RECT  0 31.344 0.084 31.368 ;
    END
  END wd[46]
  PIN wd[47]
    DIRECTION OUTPUT ;
    USE SIGNAL ;
    PORT
      LAYER M4 ;
        RECT  0 31.44 0.084 31.464 ;
    END
  END wd[47]
  PIN wd[48]
    DIRECTION OUTPUT ;
    USE SIGNAL ;
    PORT
      LAYER M4 ;
        RECT  0 31.536 0.084 31.56 ;
    END
  END wd[48]
  PIN wd[49]
    DIRECTION OUTPUT ;
    USE SIGNAL ;
    PORT
      LAYER M4 ;
        RECT  0 31.632 0.084 31.656 ;
    END
  END wd[49]
  PIN wd[4]
    DIRECTION OUTPUT ;
    USE SIGNAL ;
    PORT
      LAYER M4 ;
        RECT  0 14.256 0.084 14.28 ;
    END
  END wd[4]
  PIN wd[50]
    DIRECTION OUTPUT ;
    USE SIGNAL ;
    PORT
      LAYER M4 ;
        RECT  0 31.728 0.084 31.752 ;
    END
  END wd[50]
  PIN wd[51]
    DIRECTION OUTPUT ;
    USE SIGNAL ;
    PORT
      LAYER M4 ;
        RECT  0 31.824 0.084 31.848 ;
    END
  END wd[51]
  PIN wd[52]
    DIRECTION OUTPUT ;
    USE SIGNAL ;
    PORT
      LAYER M4 ;
        RECT  0 31.92 0.084 31.944 ;
    END
  END wd[52]
  PIN wd[53]
    DIRECTION OUTPUT ;
    USE SIGNAL ;
    PORT
      LAYER M4 ;
        RECT  0 32.016 0.084 32.04 ;
    END
  END wd[53]
  PIN wd[54]
    DIRECTION OUTPUT ;
    USE SIGNAL ;
    PORT
      LAYER M4 ;
        RECT  0 32.112 0.084 32.136 ;
    END
  END wd[54]
  PIN wd[55]
    DIRECTION OUTPUT ;
    USE SIGNAL ;
    PORT
      LAYER M4 ;
        RECT  0 32.208 0.084 32.232 ;
    END
  END wd[55]
  PIN wd[56]
    DIRECTION OUTPUT ;
    USE SIGNAL ;
    PORT
      LAYER M4 ;
        RECT  0 32.304 0.084 32.328 ;
    END
  END wd[56]
  PIN wd[57]
    DIRECTION OUTPUT ;
    USE SIGNAL ;
    PORT
      LAYER M4 ;
        RECT  0 32.4 0.084 32.424 ;
    END
  END wd[57]
  PIN wd[58]
    DIRECTION OUTPUT ;
    USE SIGNAL ;
    PORT
      LAYER M4 ;
        RECT  0 32.496 0.084 32.52 ;
    END
  END wd[58]
  PIN wd[59]
    DIRECTION OUTPUT ;
    USE SIGNAL ;
    PORT
      LAYER M4 ;
        RECT  0 32.592 0.084 32.616 ;
    END
  END wd[59]
  PIN wd[5]
    DIRECTION OUTPUT ;
    USE SIGNAL ;
    PORT
      LAYER M4 ;
        RECT  0 14.352 0.084 14.376 ;
    END
  END wd[5]
  PIN wd[60]
    DIRECTION OUTPUT ;
    USE SIGNAL ;
    PORT
      LAYER M4 ;
        RECT  0 32.688 0.084 32.712 ;
    END
  END wd[60]
  PIN wd[61]
    DIRECTION OUTPUT ;
    USE SIGNAL ;
    PORT
      LAYER M4 ;
        RECT  0 32.784 0.084 32.808 ;
    END
  END wd[61]
  PIN wd[62]
    DIRECTION OUTPUT ;
    USE SIGNAL ;
    PORT
      LAYER M4 ;
        RECT  0 32.88 0.084 32.904 ;
    END
  END wd[62]
  PIN wd[63]
    DIRECTION OUTPUT ;
    USE SIGNAL ;
    PORT
      LAYER M4 ;
        RECT  0 32.976 0.084 33 ;
    END
  END wd[63]
  PIN wd[64]
    DIRECTION OUTPUT ;
    USE SIGNAL ;
    PORT
      LAYER M4 ;
        RECT  0 33.072 0.084 33.096 ;
    END
  END wd[64]
  PIN wd[65]
    DIRECTION OUTPUT ;
    USE SIGNAL ;
    PORT
      LAYER M4 ;
        RECT  0 33.168 0.084 33.192 ;
    END
  END wd[65]
  PIN wd[66]
    DIRECTION OUTPUT ;
    USE SIGNAL ;
    PORT
      LAYER M4 ;
        RECT  0 33.264 0.084 33.288 ;
    END
  END wd[66]
  PIN wd[67]
    DIRECTION OUTPUT ;
    USE SIGNAL ;
    PORT
      LAYER M4 ;
        RECT  0 33.36 0.084 33.384 ;
    END
  END wd[67]
  PIN wd[68]
    DIRECTION OUTPUT ;
    USE SIGNAL ;
    PORT
      LAYER M4 ;
        RECT  0 33.456 0.084 33.48 ;
    END
  END wd[68]
  PIN wd[69]
    DIRECTION OUTPUT ;
    USE SIGNAL ;
    PORT
      LAYER M4 ;
        RECT  0 33.552 0.084 33.576 ;
    END
  END wd[69]
  PIN wd[6]
    DIRECTION OUTPUT ;
    USE SIGNAL ;
    PORT
      LAYER M4 ;
        RECT  0 14.448 0.084 14.472 ;
    END
  END wd[6]
  PIN wd[70]
    DIRECTION OUTPUT ;
    USE SIGNAL ;
    PORT
      LAYER M4 ;
        RECT  0 33.648 0.084 33.672 ;
    END
  END wd[70]
  PIN wd[71]
    DIRECTION OUTPUT ;
    USE SIGNAL ;
    PORT
      LAYER M4 ;
        RECT  0 33.744 0.084 33.768 ;
    END
  END wd[71]
  PIN wd[72]
    DIRECTION OUTPUT ;
    USE SIGNAL ;
    PORT
      LAYER M4 ;
        RECT  0 33.84 0.084 33.864 ;
    END
  END wd[72]
  PIN wd[73]
    DIRECTION OUTPUT ;
    USE SIGNAL ;
    PORT
      LAYER M4 ;
        RECT  0 33.936 0.084 33.96 ;
    END
  END wd[73]
  PIN wd[74]
    DIRECTION OUTPUT ;
    USE SIGNAL ;
    PORT
      LAYER M4 ;
        RECT  0 34.032 0.084 34.056 ;
    END
  END wd[74]
  PIN wd[75]
    DIRECTION OUTPUT ;
    USE SIGNAL ;
    PORT
      LAYER M4 ;
        RECT  0 34.128 0.084 34.152 ;
    END
  END wd[75]
  PIN wd[76]
    DIRECTION OUTPUT ;
    USE SIGNAL ;
    PORT
      LAYER M4 ;
        RECT  0 34.224 0.084 34.248 ;
    END
  END wd[76]
  PIN wd[77]
    DIRECTION OUTPUT ;
    USE SIGNAL ;
    PORT
      LAYER M4 ;
        RECT  0 34.32 0.084 34.344 ;
    END
  END wd[77]
  PIN wd[78]
    DIRECTION OUTPUT ;
    USE SIGNAL ;
    PORT
      LAYER M4 ;
        RECT  0 34.416 0.084 34.44 ;
    END
  END wd[78]
  PIN wd[79]
    DIRECTION OUTPUT ;
    USE SIGNAL ;
    PORT
      LAYER M4 ;
        RECT  0 34.512 0.084 34.536 ;
    END
  END wd[79]
  PIN wd[7]
    DIRECTION OUTPUT ;
    USE SIGNAL ;
    PORT
      LAYER M4 ;
        RECT  0 14.544 0.084 14.568 ;
    END
  END wd[7]
  PIN wd[80]
    DIRECTION OUTPUT ;
    USE SIGNAL ;
    PORT
      LAYER M4 ;
        RECT  0 34.608 0.084 34.632 ;
    END
  END wd[80]
  PIN wd[81]
    DIRECTION OUTPUT ;
    USE SIGNAL ;
    PORT
      LAYER M4 ;
        RECT  0 34.704 0.084 34.728 ;
    END
  END wd[81]
  PIN wd[82]
    DIRECTION OUTPUT ;
    USE SIGNAL ;
    PORT
      LAYER M4 ;
        RECT  0 34.8 0.084 34.824 ;
    END
  END wd[82]
  PIN wd[83]
    DIRECTION OUTPUT ;
    USE SIGNAL ;
    PORT
      LAYER M4 ;
        RECT  0 34.896 0.084 34.92 ;
    END
  END wd[83]
  PIN wd[84]
    DIRECTION OUTPUT ;
    USE SIGNAL ;
    PORT
      LAYER M4 ;
        RECT  0 34.992 0.084 35.016 ;
    END
  END wd[84]
  PIN wd[85]
    DIRECTION OUTPUT ;
    USE SIGNAL ;
    PORT
      LAYER M4 ;
        RECT  0 35.088 0.084 35.112 ;
    END
  END wd[85]
  PIN wd[86]
    DIRECTION OUTPUT ;
    USE SIGNAL ;
    PORT
      LAYER M4 ;
        RECT  0 35.184 0.084 35.208 ;
    END
  END wd[86]
  PIN wd[87]
    DIRECTION OUTPUT ;
    USE SIGNAL ;
    PORT
      LAYER M4 ;
        RECT  0 35.28 0.084 35.304 ;
    END
  END wd[87]
  PIN wd[88]
    DIRECTION OUTPUT ;
    USE SIGNAL ;
    PORT
      LAYER M4 ;
        RECT  0 35.376 0.084 35.4 ;
    END
  END wd[88]
  PIN wd[89]
    DIRECTION OUTPUT ;
    USE SIGNAL ;
    PORT
      LAYER M4 ;
        RECT  0 35.472 0.084 35.496 ;
    END
  END wd[89]
  PIN wd[8]
    DIRECTION OUTPUT ;
    USE SIGNAL ;
    PORT
      LAYER M4 ;
        RECT  0 14.64 0.084 14.664 ;
    END
  END wd[8]
  PIN wd[90]
    DIRECTION OUTPUT ;
    USE SIGNAL ;
    PORT
      LAYER M4 ;
        RECT  0 35.568 0.084 35.592 ;
    END
  END wd[90]
  PIN wd[91]
    DIRECTION OUTPUT ;
    USE SIGNAL ;
    PORT
      LAYER M4 ;
        RECT  0 35.664 0.084 35.688 ;
    END
  END wd[91]
  PIN wd[92]
    DIRECTION OUTPUT ;
    USE SIGNAL ;
    PORT
      LAYER M4 ;
        RECT  0 35.76 0.084 35.784 ;
    END
  END wd[92]
  PIN wd[93]
    DIRECTION OUTPUT ;
    USE SIGNAL ;
    PORT
      LAYER M4 ;
        RECT  0 35.856 0.084 35.88 ;
    END
  END wd[93]
  PIN wd[94]
    DIRECTION OUTPUT ;
    USE SIGNAL ;
    PORT
      LAYER M4 ;
        RECT  0 35.952 0.084 35.976 ;
    END
  END wd[94]
  PIN wd[95]
    DIRECTION OUTPUT ;
    USE SIGNAL ;
    PORT
      LAYER M4 ;
        RECT  0 36.048 0.084 36.072 ;
    END
  END wd[95]
  PIN wd[96]
    DIRECTION OUTPUT ;
    USE SIGNAL ;
    PORT
      LAYER M4 ;
        RECT  0 36.144 0.084 36.168 ;
    END
  END wd[96]
  PIN wd[97]
    DIRECTION OUTPUT ;
    USE SIGNAL ;
    PORT
      LAYER M4 ;
        RECT  0 36.24 0.084 36.264 ;
    END
  END wd[97]
  PIN wd[98]
    DIRECTION OUTPUT ;
    USE SIGNAL ;
    PORT
      LAYER M4 ;
        RECT  0 36.336 0.084 36.36 ;
    END
  END wd[98]
  PIN wd[99]
    DIRECTION OUTPUT ;
    USE SIGNAL ;
    PORT
      LAYER M4 ;
        RECT  0 36.432 0.084 36.456 ;
    END
  END wd[99]
  PIN wd[9]
    DIRECTION OUTPUT ;
    USE SIGNAL ;
    PORT
      LAYER M4 ;
        RECT  0 14.736 0.084 14.76 ;
    END
  END wd[9]
  PIN write_en
    DIRECTION INPUT ;
    USE SIGNAL ;
    PORT
      LAYER M5 ;
        RECT  14.064 87.396 14.088 87.48 ;
    END
  END write_en
  PIN write_slot[0]
    DIRECTION INPUT ;
    USE SIGNAL ;
    PORT
      LAYER M5 ;
        RECT  16.464 87.396 16.488 87.48 ;
    END
  END write_slot[0]
  PIN write_slot[1]
    DIRECTION INPUT ;
    USE SIGNAL ;
    PORT
      LAYER M5 ;
        RECT  16.56 87.396 16.584 87.48 ;
    END
  END write_slot[1]
  PIN write_slot[2]
    DIRECTION INPUT ;
    USE SIGNAL ;
    PORT
      LAYER M5 ;
        RECT  16.656 87.396 16.68 87.48 ;
    END
  END write_slot[2]
  PIN write_slot[3]
    DIRECTION INPUT ;
    USE SIGNAL ;
    PORT
      LAYER M5 ;
        RECT  16.752 87.396 16.776 87.48 ;
    END
  END write_slot[3]
  PIN write_slot[4]
    DIRECTION INPUT ;
    USE SIGNAL ;
    PORT
      LAYER M5 ;
        RECT  16.848 87.396 16.872 87.48 ;
    END
  END write_slot[4]
  PIN write_slot[5]
    DIRECTION INPUT ;
    USE SIGNAL ;
    PORT
      LAYER M5 ;
        RECT  16.944 87.396 16.968 87.48 ;
    END
  END write_slot[5]
  PIN write_slot[6]
    DIRECTION INPUT ;
    USE SIGNAL ;
    PORT
      LAYER M5 ;
        RECT  17.04 87.396 17.064 87.48 ;
    END
  END write_slot[6]
  PIN VDD
    DIRECTION INOUT ;
    USE POWER ;
    PORT
      LAYER M5 ;
        RECT  137.592 2.151 137.712 85.329 ;
        RECT  132.192 2.151 132.312 85.329 ;
        RECT  126.792 2.151 126.912 85.329 ;
        RECT  121.392 2.151 121.512 85.329 ;
        RECT  115.992 2.151 116.112 85.329 ;
        RECT  110.592 2.151 110.712 85.329 ;
        RECT  105.192 2.151 105.312 85.329 ;
        RECT  99.792 2.151 99.912 85.329 ;
        RECT  94.392 2.151 94.512 85.329 ;
        RECT  88.992 2.151 89.112 85.329 ;
        RECT  83.592 2.151 83.712 85.329 ;
        RECT  78.192 2.151 78.312 85.329 ;
        RECT  72.792 2.151 72.912 85.329 ;
        RECT  67.392 2.151 67.512 85.329 ;
        RECT  61.992 2.151 62.112 85.329 ;
        RECT  56.592 2.151 56.712 85.329 ;
        RECT  51.192 2.151 51.312 85.329 ;
        RECT  45.792 2.151 45.912 85.329 ;
        RECT  40.392 2.151 40.512 85.329 ;
        RECT  34.992 2.151 35.112 85.329 ;
        RECT  29.592 2.151 29.712 85.329 ;
        RECT  24.192 2.151 24.312 85.329 ;
        RECT  18.792 2.151 18.912 85.329 ;
        RECT  13.392 2.151 13.512 85.329 ;
        RECT  7.992 2.151 8.112 85.329 ;
        RECT  2.592 2.151 2.712 85.329 ;
    END
  END VDD
  PIN VSS
    DIRECTION INOUT ;
    USE GROUND ;
    PORT
      LAYER M5 ;
        RECT  137.4 2.137 137.52 85.343 ;
        RECT  132 2.137 132.12 85.343 ;
        RECT  126.6 2.137 126.72 85.343 ;
        RECT  121.2 2.137 121.32 85.343 ;
        RECT  115.8 2.137 115.92 85.343 ;
        RECT  110.4 2.137 110.52 85.343 ;
        RECT  105 2.137 105.12 85.343 ;
        RECT  99.6 2.137 99.72 85.343 ;
        RECT  94.2 2.137 94.32 85.343 ;
        RECT  88.8 2.137 88.92 85.343 ;
        RECT  83.4 2.137 83.52 85.343 ;
        RECT  78 2.137 78.12 85.343 ;
        RECT  72.6 2.137 72.72 85.343 ;
        RECT  67.2 2.137 67.32 85.343 ;
        RECT  61.8 2.137 61.92 85.343 ;
        RECT  56.4 2.137 56.52 85.343 ;
        RECT  51 2.137 51.12 85.343 ;
        RECT  45.6 2.137 45.72 85.343 ;
        RECT  40.2 2.137 40.32 85.343 ;
        RECT  34.8 2.137 34.92 85.343 ;
        RECT  29.4 2.137 29.52 85.343 ;
        RECT  24 2.137 24.12 85.343 ;
        RECT  18.6 2.137 18.72 85.343 ;
        RECT  13.2 2.137 13.32 85.343 ;
        RECT  7.8 2.137 7.92 85.343 ;
        RECT  2.4 2.137 2.52 85.343 ;
    END
  END VSS
  OBS
    LAYER RVTN ;
     RECT  2.16 2.16 138.24 2.295 ;
     RECT  2.16 2.565 138.24 2.835 ;
     RECT  2.16 3.105 138.24 3.375 ;
     RECT  2.16 3.645 138.24 3.915 ;
     RECT  2.16 4.185 138.24 4.455 ;
     RECT  2.16 4.725 138.24 4.995 ;
     RECT  2.16 5.265 138.24 5.535 ;
     RECT  2.16 5.805 138.24 6.075 ;
     RECT  2.16 6.345 138.24 6.615 ;
     RECT  2.16 6.885 138.24 7.155 ;
     RECT  2.16 7.425 138.24 7.695 ;
     RECT  2.16 7.965 138.24 8.235 ;
     RECT  2.16 8.505 138.24 8.775 ;
     RECT  2.16 9.045 138.24 9.315 ;
     RECT  2.16 9.585 138.24 9.855 ;
     RECT  2.16 10.125 138.24 10.395 ;
     RECT  2.16 10.665 138.24 10.935 ;
     RECT  2.16 11.205 138.24 11.475 ;
     RECT  2.16 11.745 138.24 12.015 ;
     RECT  2.16 12.285 138.24 12.555 ;
     RECT  2.16 12.825 138.24 13.095 ;
     RECT  2.16 13.365 138.24 13.635 ;
     RECT  2.16 13.905 138.24 14.175 ;
     RECT  2.16 14.445 138.24 14.715 ;
     RECT  2.16 14.985 138.24 15.255 ;
     RECT  2.16 15.525 138.24 15.795 ;
     RECT  2.16 16.065 138.24 16.335 ;
     RECT  2.16 16.605 138.24 16.875 ;
     RECT  2.16 17.145 138.24 17.415 ;
     RECT  2.16 17.685 138.24 17.955 ;
     RECT  2.16 18.225 138.24 18.495 ;
     RECT  2.16 18.765 138.24 19.035 ;
     RECT  2.16 19.305 138.24 19.575 ;
     RECT  2.16 19.845 138.24 20.115 ;
     RECT  2.16 20.385 138.24 20.655 ;
     RECT  2.16 20.925 138.24 21.195 ;
     RECT  2.16 21.465 138.24 21.6 ;
     RECT  2.16 21.6 20.412 21.735 ;
     RECT  119.34 21.6 138.24 21.735 ;
     RECT  2.16 22.005 20.412 22.275 ;
     RECT  119.34 22.005 138.24 22.275 ;
     RECT  2.16 22.545 20.412 22.815 ;
     RECT  119.34 22.545 138.24 22.815 ;
     RECT  2.16 23.085 20.412 23.355 ;
     RECT  119.34 23.085 138.24 23.355 ;
     RECT  2.16 23.625 20.412 23.895 ;
     RECT  119.34 23.625 138.24 23.895 ;
     RECT  2.16 24.165 20.412 24.435 ;
     RECT  119.34 24.165 138.24 24.435 ;
     RECT  2.16 24.705 20.412 24.975 ;
     RECT  119.34 24.705 138.24 24.975 ;
     RECT  2.16 25.245 20.412 25.515 ;
     RECT  119.34 25.245 138.24 25.515 ;
     RECT  2.16 25.785 20.412 26.055 ;
     RECT  119.34 25.785 138.24 26.055 ;
     RECT  2.16 26.325 20.412 26.595 ;
     RECT  119.34 26.325 138.24 26.595 ;
     RECT  2.16 26.865 20.412 27.135 ;
     RECT  119.34 26.865 138.24 27.135 ;
     RECT  2.16 27.405 20.412 27.675 ;
     RECT  119.34 27.405 138.24 27.675 ;
     RECT  2.16 27.945 20.412 28.215 ;
     RECT  119.34 27.945 138.24 28.215 ;
     RECT  2.16 28.485 20.412 28.755 ;
     RECT  119.34 28.485 138.24 28.755 ;
     RECT  2.16 29.025 20.412 29.295 ;
     RECT  119.34 29.025 138.24 29.295 ;
     RECT  2.16 29.565 20.412 29.835 ;
     RECT  119.34 29.565 138.24 29.835 ;
     RECT  2.16 30.105 20.412 30.375 ;
     RECT  119.34 30.105 138.24 30.375 ;
     RECT  2.16 30.645 20.412 30.915 ;
     RECT  119.34 30.645 138.24 30.915 ;
     RECT  2.16 31.185 20.412 31.455 ;
     RECT  119.34 31.185 138.24 31.455 ;
     RECT  2.16 31.725 20.412 31.995 ;
     RECT  119.34 31.725 138.24 31.995 ;
     RECT  2.16 32.265 20.412 32.535 ;
     RECT  119.34 32.265 138.24 32.535 ;
     RECT  2.16 32.805 20.412 33.075 ;
     RECT  119.34 32.805 138.24 33.075 ;
     RECT  2.16 33.345 20.412 33.615 ;
     RECT  119.34 33.345 138.24 33.615 ;
     RECT  2.16 33.885 20.412 34.155 ;
     RECT  119.34 33.885 138.24 34.155 ;
     RECT  2.16 34.425 20.412 34.695 ;
     RECT  119.34 34.425 138.24 34.695 ;
     RECT  2.16 34.965 20.412 35.235 ;
     RECT  119.34 34.965 138.24 35.235 ;
     RECT  2.16 35.505 20.412 35.775 ;
     RECT  119.34 35.505 138.24 35.775 ;
     RECT  2.16 36.045 20.412 36.315 ;
     RECT  119.34 36.045 138.24 36.315 ;
     RECT  2.16 36.585 20.412 36.855 ;
     RECT  119.34 36.585 138.24 36.855 ;
     RECT  2.16 37.125 20.412 37.395 ;
     RECT  119.34 37.125 138.24 37.395 ;
     RECT  2.16 37.665 20.412 37.935 ;
     RECT  119.34 37.665 138.24 37.935 ;
     RECT  2.16 38.205 20.412 38.475 ;
     RECT  119.34 38.205 138.24 38.475 ;
     RECT  2.16 38.745 20.412 39.015 ;
     RECT  119.34 38.745 138.24 39.015 ;
     RECT  2.16 39.285 20.412 39.555 ;
     RECT  119.34 39.285 138.24 39.555 ;
     RECT  2.16 39.825 20.412 40.095 ;
     RECT  119.34 39.825 138.24 40.095 ;
     RECT  2.16 40.365 20.412 40.635 ;
     RECT  119.34 40.365 138.24 40.635 ;
     RECT  2.16 40.905 20.412 41.175 ;
     RECT  119.34 40.905 138.24 41.175 ;
     RECT  2.16 41.445 20.412 41.715 ;
     RECT  119.34 41.445 138.24 41.715 ;
     RECT  2.16 41.985 20.412 42.255 ;
     RECT  119.34 41.985 138.24 42.255 ;
     RECT  2.16 42.525 20.412 42.795 ;
     RECT  119.34 42.525 138.24 42.795 ;
     RECT  2.16 43.065 20.412 43.335 ;
     RECT  119.34 43.065 138.24 43.335 ;
     RECT  2.16 43.605 20.412 43.875 ;
     RECT  119.34 43.605 138.24 43.875 ;
     RECT  2.16 44.145 20.412 44.415 ;
     RECT  119.34 44.145 138.24 44.415 ;
     RECT  2.16 44.685 20.412 44.955 ;
     RECT  119.34 44.685 138.24 44.955 ;
     RECT  2.16 45.225 20.412 45.495 ;
     RECT  119.34 45.225 138.24 45.495 ;
     RECT  2.16 45.765 20.412 46.035 ;
     RECT  119.34 45.765 138.24 46.035 ;
     RECT  2.16 46.305 20.412 46.575 ;
     RECT  119.34 46.305 138.24 46.575 ;
     RECT  2.16 46.845 20.412 47.115 ;
     RECT  119.34 46.845 138.24 47.115 ;
     RECT  2.16 47.385 20.412 47.655 ;
     RECT  119.34 47.385 138.24 47.655 ;
     RECT  2.16 47.925 20.412 48.195 ;
     RECT  119.34 47.925 138.24 48.195 ;
     RECT  2.16 48.465 20.412 48.735 ;
     RECT  119.34 48.465 138.24 48.735 ;
     RECT  2.16 49.005 20.412 49.275 ;
     RECT  119.34 49.005 138.24 49.275 ;
     RECT  2.16 49.545 20.412 49.815 ;
     RECT  119.34 49.545 138.24 49.815 ;
     RECT  2.16 50.085 20.412 50.355 ;
     RECT  119.34 50.085 138.24 50.355 ;
     RECT  2.16 50.625 20.412 50.895 ;
     RECT  119.34 50.625 138.24 50.895 ;
     RECT  2.16 51.165 20.412 51.435 ;
     RECT  119.34 51.165 138.24 51.435 ;
     RECT  2.16 51.705 20.412 51.975 ;
     RECT  119.34 51.705 138.24 51.975 ;
     RECT  2.16 52.245 20.412 52.515 ;
     RECT  119.34 52.245 138.24 52.515 ;
     RECT  2.16 52.785 20.412 53.055 ;
     RECT  119.34 52.785 138.24 53.055 ;
     RECT  2.16 53.325 20.412 53.595 ;
     RECT  119.34 53.325 138.24 53.595 ;
     RECT  2.16 53.865 20.412 54.135 ;
     RECT  119.34 53.865 138.24 54.135 ;
     RECT  2.16 54.405 20.412 54.675 ;
     RECT  119.34 54.405 138.24 54.675 ;
     RECT  2.16 54.945 20.412 55.215 ;
     RECT  119.34 54.945 138.24 55.215 ;
     RECT  2.16 55.485 20.412 55.755 ;
     RECT  119.34 55.485 138.24 55.755 ;
     RECT  2.16 56.025 20.412 56.295 ;
     RECT  119.34 56.025 138.24 56.295 ;
     RECT  2.16 56.565 20.412 56.835 ;
     RECT  119.34 56.565 138.24 56.835 ;
     RECT  2.16 57.105 20.412 57.375 ;
     RECT  119.34 57.105 138.24 57.375 ;
     RECT  2.16 57.645 20.412 57.915 ;
     RECT  119.34 57.645 138.24 57.915 ;
     RECT  2.16 58.185 20.412 58.455 ;
     RECT  119.34 58.185 138.24 58.455 ;
     RECT  2.16 58.725 20.412 58.995 ;
     RECT  119.34 58.725 138.24 58.995 ;
     RECT  2.16 59.265 20.412 59.535 ;
     RECT  119.34 59.265 138.24 59.535 ;
     RECT  2.16 59.805 20.412 60.075 ;
     RECT  119.34 59.805 138.24 60.075 ;
     RECT  2.16 60.345 20.412 60.615 ;
     RECT  119.34 60.345 138.24 60.615 ;
     RECT  2.16 60.885 20.412 61.155 ;
     RECT  119.34 60.885 138.24 61.155 ;
     RECT  2.16 61.425 20.412 61.695 ;
     RECT  119.34 61.425 138.24 61.695 ;
     RECT  2.16 61.965 20.412 62.235 ;
     RECT  119.34 61.965 138.24 62.235 ;
     RECT  2.16 62.505 20.412 62.775 ;
     RECT  119.34 62.505 138.24 62.775 ;
     RECT  2.16 63.045 20.412 63.315 ;
     RECT  119.34 63.045 138.24 63.315 ;
     RECT  2.16 63.585 20.412 63.855 ;
     RECT  119.34 63.585 138.24 63.855 ;
     RECT  2.16 64.125 20.412 64.395 ;
     RECT  119.34 64.125 138.24 64.395 ;
     RECT  2.16 64.665 20.412 64.935 ;
     RECT  119.34 64.665 138.24 64.935 ;
     RECT  2.16 65.205 20.412 65.475 ;
     RECT  119.34 65.205 138.24 65.475 ;
     RECT  2.16 65.745 20.412 66.015 ;
     RECT  119.34 65.745 138.24 66.015 ;
     RECT  2.16 66.285 20.412 66.555 ;
     RECT  119.34 66.285 138.24 66.555 ;
     RECT  2.16 66.825 20.412 66.96 ;
     RECT  119.34 66.825 138.24 66.96 ;
     RECT  2.16 66.96 138.24 67.095 ;
     RECT  2.16 67.365 138.24 67.635 ;
     RECT  2.16 67.905 138.24 68.175 ;
     RECT  2.16 68.445 138.24 68.715 ;
     RECT  2.16 68.985 138.24 69.255 ;
     RECT  2.16 69.525 138.24 69.795 ;
     RECT  2.16 70.065 138.24 70.335 ;
     RECT  2.16 70.605 138.24 70.875 ;
     RECT  2.16 71.145 138.24 71.415 ;
     RECT  2.16 71.685 138.24 71.955 ;
     RECT  2.16 72.225 138.24 72.495 ;
     RECT  2.16 72.765 138.24 73.035 ;
     RECT  2.16 73.305 138.24 73.575 ;
     RECT  2.16 73.845 138.24 74.115 ;
     RECT  2.16 74.385 138.24 74.655 ;
     RECT  2.16 74.925 138.24 75.195 ;
     RECT  2.16 75.465 138.24 75.735 ;
     RECT  2.16 76.005 138.24 76.275 ;
     RECT  2.16 76.545 138.24 76.815 ;
     RECT  2.16 77.085 138.24 77.355 ;
     RECT  2.16 77.625 138.24 77.895 ;
     RECT  2.16 78.165 138.24 78.435 ;
     RECT  2.16 78.705 138.24 78.975 ;
     RECT  2.16 79.245 138.24 79.515 ;
     RECT  2.16 79.785 138.24 80.055 ;
     RECT  2.16 80.325 138.24 80.595 ;
     RECT  2.16 80.865 138.24 81.135 ;
     RECT  2.16 81.405 138.24 81.675 ;
     RECT  2.16 81.945 138.24 82.215 ;
     RECT  2.16 82.485 138.24 82.755 ;
     RECT  2.16 83.025 138.24 83.295 ;
     RECT  2.16 83.565 138.24 83.835 ;
     RECT  2.16 84.105 138.24 84.375 ;
     RECT  2.16 84.645 138.24 84.915 ;
     RECT  2.16 85.185 138.24 85.32 ;
    LAYER RVTP ;
     RECT  2.16 2.295 138.24 2.565 ;
     RECT  2.16 2.835 138.24 3.105 ;
     RECT  2.16 3.375 138.24 3.645 ;
     RECT  2.16 3.915 138.24 4.185 ;
     RECT  2.16 4.455 138.24 4.725 ;
     RECT  2.16 4.995 138.24 5.265 ;
     RECT  2.16 5.535 138.24 5.805 ;
     RECT  2.16 6.075 138.24 6.345 ;
     RECT  2.16 6.615 138.24 6.885 ;
     RECT  2.16 7.155 138.24 7.425 ;
     RECT  2.16 7.695 138.24 7.965 ;
     RECT  2.16 8.235 138.24 8.505 ;
     RECT  2.16 8.775 138.24 9.045 ;
     RECT  2.16 9.315 138.24 9.585 ;
     RECT  2.16 9.855 138.24 10.125 ;
     RECT  2.16 10.395 138.24 10.665 ;
     RECT  2.16 10.935 138.24 11.205 ;
     RECT  2.16 11.475 138.24 11.745 ;
     RECT  2.16 12.015 138.24 12.285 ;
     RECT  2.16 12.555 138.24 12.825 ;
     RECT  2.16 13.095 138.24 13.365 ;
     RECT  2.16 13.635 138.24 13.905 ;
     RECT  2.16 14.175 138.24 14.445 ;
     RECT  2.16 14.715 138.24 14.985 ;
     RECT  2.16 15.255 138.24 15.525 ;
     RECT  2.16 15.795 138.24 16.065 ;
     RECT  2.16 16.335 138.24 16.605 ;
     RECT  2.16 16.875 138.24 17.145 ;
     RECT  2.16 17.415 138.24 17.685 ;
     RECT  2.16 17.955 138.24 18.225 ;
     RECT  2.16 18.495 138.24 18.765 ;
     RECT  2.16 19.035 138.24 19.305 ;
     RECT  2.16 19.575 138.24 19.845 ;
     RECT  2.16 20.115 138.24 20.385 ;
     RECT  2.16 20.655 138.24 20.925 ;
     RECT  2.16 21.195 138.24 21.465 ;
     RECT  2.16 21.735 20.412 22.005 ;
     RECT  119.34 21.735 138.24 22.005 ;
     RECT  2.16 22.275 20.412 22.545 ;
     RECT  119.34 22.275 138.24 22.545 ;
     RECT  2.16 22.815 20.412 23.085 ;
     RECT  119.34 22.815 138.24 23.085 ;
     RECT  2.16 23.355 20.412 23.625 ;
     RECT  119.34 23.355 138.24 23.625 ;
     RECT  2.16 23.895 20.412 24.165 ;
     RECT  119.34 23.895 138.24 24.165 ;
     RECT  2.16 24.435 20.412 24.705 ;
     RECT  119.34 24.435 138.24 24.705 ;
     RECT  2.16 24.975 20.412 25.245 ;
     RECT  119.34 24.975 138.24 25.245 ;
     RECT  2.16 25.515 20.412 25.785 ;
     RECT  119.34 25.515 138.24 25.785 ;
     RECT  2.16 26.055 20.412 26.325 ;
     RECT  119.34 26.055 138.24 26.325 ;
     RECT  2.16 26.595 20.412 26.865 ;
     RECT  119.34 26.595 138.24 26.865 ;
     RECT  2.16 27.135 20.412 27.405 ;
     RECT  119.34 27.135 138.24 27.405 ;
     RECT  2.16 27.675 20.412 27.945 ;
     RECT  119.34 27.675 138.24 27.945 ;
     RECT  2.16 28.215 20.412 28.485 ;
     RECT  119.34 28.215 138.24 28.485 ;
     RECT  2.16 28.755 20.412 29.025 ;
     RECT  119.34 28.755 138.24 29.025 ;
     RECT  2.16 29.295 20.412 29.565 ;
     RECT  119.34 29.295 138.24 29.565 ;
     RECT  2.16 29.835 20.412 30.105 ;
     RECT  119.34 29.835 138.24 30.105 ;
     RECT  2.16 30.375 20.412 30.645 ;
     RECT  119.34 30.375 138.24 30.645 ;
     RECT  2.16 30.915 20.412 31.185 ;
     RECT  119.34 30.915 138.24 31.185 ;
     RECT  2.16 31.455 20.412 31.725 ;
     RECT  119.34 31.455 138.24 31.725 ;
     RECT  2.16 31.995 20.412 32.265 ;
     RECT  119.34 31.995 138.24 32.265 ;
     RECT  2.16 32.535 20.412 32.805 ;
     RECT  119.34 32.535 138.24 32.805 ;
     RECT  2.16 33.075 20.412 33.345 ;
     RECT  119.34 33.075 138.24 33.345 ;
     RECT  2.16 33.615 20.412 33.885 ;
     RECT  119.34 33.615 138.24 33.885 ;
     RECT  2.16 34.155 20.412 34.425 ;
     RECT  119.34 34.155 138.24 34.425 ;
     RECT  2.16 34.695 20.412 34.965 ;
     RECT  119.34 34.695 138.24 34.965 ;
     RECT  2.16 35.235 20.412 35.505 ;
     RECT  119.34 35.235 138.24 35.505 ;
     RECT  2.16 35.775 20.412 36.045 ;
     RECT  119.34 35.775 138.24 36.045 ;
     RECT  2.16 36.315 20.412 36.585 ;
     RECT  119.34 36.315 138.24 36.585 ;
     RECT  2.16 36.855 20.412 37.125 ;
     RECT  119.34 36.855 138.24 37.125 ;
     RECT  2.16 37.395 20.412 37.665 ;
     RECT  119.34 37.395 138.24 37.665 ;
     RECT  2.16 37.935 20.412 38.205 ;
     RECT  119.34 37.935 138.24 38.205 ;
     RECT  2.16 38.475 20.412 38.745 ;
     RECT  119.34 38.475 138.24 38.745 ;
     RECT  2.16 39.015 20.412 39.285 ;
     RECT  119.34 39.015 138.24 39.285 ;
     RECT  2.16 39.555 20.412 39.825 ;
     RECT  119.34 39.555 138.24 39.825 ;
     RECT  2.16 40.095 20.412 40.365 ;
     RECT  119.34 40.095 138.24 40.365 ;
     RECT  2.16 40.635 20.412 40.905 ;
     RECT  119.34 40.635 138.24 40.905 ;
     RECT  2.16 41.175 20.412 41.445 ;
     RECT  119.34 41.175 138.24 41.445 ;
     RECT  2.16 41.715 20.412 41.985 ;
     RECT  119.34 41.715 138.24 41.985 ;
     RECT  2.16 42.255 20.412 42.525 ;
     RECT  119.34 42.255 138.24 42.525 ;
     RECT  2.16 42.795 20.412 43.065 ;
     RECT  119.34 42.795 138.24 43.065 ;
     RECT  2.16 43.335 20.412 43.605 ;
     RECT  119.34 43.335 138.24 43.605 ;
     RECT  2.16 43.875 20.412 44.145 ;
     RECT  119.34 43.875 138.24 44.145 ;
     RECT  2.16 44.415 20.412 44.685 ;
     RECT  119.34 44.415 138.24 44.685 ;
     RECT  2.16 44.955 20.412 45.225 ;
     RECT  119.34 44.955 138.24 45.225 ;
     RECT  2.16 45.495 20.412 45.765 ;
     RECT  119.34 45.495 138.24 45.765 ;
     RECT  2.16 46.035 20.412 46.305 ;
     RECT  119.34 46.035 138.24 46.305 ;
     RECT  2.16 46.575 20.412 46.845 ;
     RECT  119.34 46.575 138.24 46.845 ;
     RECT  2.16 47.115 20.412 47.385 ;
     RECT  119.34 47.115 138.24 47.385 ;
     RECT  2.16 47.655 20.412 47.925 ;
     RECT  119.34 47.655 138.24 47.925 ;
     RECT  2.16 48.195 20.412 48.465 ;
     RECT  119.34 48.195 138.24 48.465 ;
     RECT  2.16 48.735 20.412 49.005 ;
     RECT  119.34 48.735 138.24 49.005 ;
     RECT  2.16 49.275 20.412 49.545 ;
     RECT  119.34 49.275 138.24 49.545 ;
     RECT  2.16 49.815 20.412 50.085 ;
     RECT  119.34 49.815 138.24 50.085 ;
     RECT  2.16 50.355 20.412 50.625 ;
     RECT  119.34 50.355 138.24 50.625 ;
     RECT  2.16 50.895 20.412 51.165 ;
     RECT  119.34 50.895 138.24 51.165 ;
     RECT  2.16 51.435 20.412 51.705 ;
     RECT  119.34 51.435 138.24 51.705 ;
     RECT  2.16 51.975 20.412 52.245 ;
     RECT  119.34 51.975 138.24 52.245 ;
     RECT  2.16 52.515 20.412 52.785 ;
     RECT  119.34 52.515 138.24 52.785 ;
     RECT  2.16 53.055 20.412 53.325 ;
     RECT  119.34 53.055 138.24 53.325 ;
     RECT  2.16 53.595 20.412 53.865 ;
     RECT  119.34 53.595 138.24 53.865 ;
     RECT  2.16 54.135 20.412 54.405 ;
     RECT  119.34 54.135 138.24 54.405 ;
     RECT  2.16 54.675 20.412 54.945 ;
     RECT  119.34 54.675 138.24 54.945 ;
     RECT  2.16 55.215 20.412 55.485 ;
     RECT  119.34 55.215 138.24 55.485 ;
     RECT  2.16 55.755 20.412 56.025 ;
     RECT  119.34 55.755 138.24 56.025 ;
     RECT  2.16 56.295 20.412 56.565 ;
     RECT  119.34 56.295 138.24 56.565 ;
     RECT  2.16 56.835 20.412 57.105 ;
     RECT  119.34 56.835 138.24 57.105 ;
     RECT  2.16 57.375 20.412 57.645 ;
     RECT  119.34 57.375 138.24 57.645 ;
     RECT  2.16 57.915 20.412 58.185 ;
     RECT  119.34 57.915 138.24 58.185 ;
     RECT  2.16 58.455 20.412 58.725 ;
     RECT  119.34 58.455 138.24 58.725 ;
     RECT  2.16 58.995 20.412 59.265 ;
     RECT  119.34 58.995 138.24 59.265 ;
     RECT  2.16 59.535 20.412 59.805 ;
     RECT  119.34 59.535 138.24 59.805 ;
     RECT  2.16 60.075 20.412 60.345 ;
     RECT  119.34 60.075 138.24 60.345 ;
     RECT  2.16 60.615 20.412 60.885 ;
     RECT  119.34 60.615 138.24 60.885 ;
     RECT  2.16 61.155 20.412 61.425 ;
     RECT  119.34 61.155 138.24 61.425 ;
     RECT  2.16 61.695 20.412 61.965 ;
     RECT  119.34 61.695 138.24 61.965 ;
     RECT  2.16 62.235 20.412 62.505 ;
     RECT  119.34 62.235 138.24 62.505 ;
     RECT  2.16 62.775 20.412 63.045 ;
     RECT  119.34 62.775 138.24 63.045 ;
     RECT  2.16 63.315 20.412 63.585 ;
     RECT  119.34 63.315 138.24 63.585 ;
     RECT  2.16 63.855 20.412 64.125 ;
     RECT  119.34 63.855 138.24 64.125 ;
     RECT  2.16 64.395 20.412 64.665 ;
     RECT  119.34 64.395 138.24 64.665 ;
     RECT  2.16 64.935 20.412 65.205 ;
     RECT  119.34 64.935 138.24 65.205 ;
     RECT  2.16 65.475 20.412 65.745 ;
     RECT  119.34 65.475 138.24 65.745 ;
     RECT  2.16 66.015 20.412 66.285 ;
     RECT  119.34 66.015 138.24 66.285 ;
     RECT  2.16 66.555 20.412 66.825 ;
     RECT  119.34 66.555 138.24 66.825 ;
     RECT  2.16 67.095 138.24 67.365 ;
     RECT  2.16 67.635 138.24 67.905 ;
     RECT  2.16 68.175 138.24 68.445 ;
     RECT  2.16 68.715 138.24 68.985 ;
     RECT  2.16 69.255 138.24 69.525 ;
     RECT  2.16 69.795 138.24 70.065 ;
     RECT  2.16 70.335 138.24 70.605 ;
     RECT  2.16 70.875 138.24 71.145 ;
     RECT  2.16 71.415 138.24 71.685 ;
     RECT  2.16 71.955 138.24 72.225 ;
     RECT  2.16 72.495 138.24 72.765 ;
     RECT  2.16 73.035 138.24 73.305 ;
     RECT  2.16 73.575 138.24 73.845 ;
     RECT  2.16 74.115 138.24 74.385 ;
     RECT  2.16 74.655 138.24 74.925 ;
     RECT  2.16 75.195 138.24 75.465 ;
     RECT  2.16 75.735 138.24 76.005 ;
     RECT  2.16 76.275 138.24 76.545 ;
     RECT  2.16 76.815 138.24 77.085 ;
     RECT  2.16 77.355 138.24 77.625 ;
     RECT  2.16 77.895 138.24 78.165 ;
     RECT  2.16 78.435 138.24 78.705 ;
     RECT  2.16 78.975 138.24 79.245 ;
     RECT  2.16 79.515 138.24 79.785 ;
     RECT  2.16 80.055 138.24 80.325 ;
     RECT  2.16 80.595 138.24 80.865 ;
     RECT  2.16 81.135 138.24 81.405 ;
     RECT  2.16 81.675 138.24 81.945 ;
     RECT  2.16 82.215 138.24 82.485 ;
     RECT  2.16 82.755 138.24 83.025 ;
     RECT  2.16 83.295 138.24 83.565 ;
     RECT  2.16 83.835 138.24 84.105 ;
     RECT  2.16 84.375 138.24 84.645 ;
     RECT  2.16 84.915 138.24 85.185 ;
    LAYER M1 ;
     RECT  2.16 2.151 138.24 21.609 ;
     RECT  22.464 23.76 117.288 64.824 ;
     RECT  2.16 21.609 20.412 66.951 ;
     RECT  119.34 21.609 138.24 66.951 ;
     RECT  2.16 66.951 138.24 85.329 ;
    LAYER M2 ;
     RECT  0.103 16.236 0.139 17.289 ;
     RECT  0.103 18.126 0.139 18.828 ;
     RECT  0.103 19.62 0.139 21.294 ;
     RECT  0.103 22.05 0.139 23.724 ;
     RECT  0.103 24.48 0.139 25.812 ;
     RECT  0.103 36.756 0.139 36.774 ;
     RECT  0.103 41.076 0.139 45.486 ;
     RECT  0.103 66.492 0.139 66.51 ;
     RECT  0.103 67.842 0.139 67.86 ;
     RECT  0.103 14.526 0.175 14.544 ;
     RECT  0.103 64.368 0.175 65.232 ;
     RECT  0.139 66.492 0.175 67.86 ;
     RECT  0.139 16.236 0.203 18.828 ;
     RECT  0.139 19.62 0.203 25.812 ;
     RECT  0.103 28.53 0.203 28.548 ;
     RECT  0.103 30.078 0.203 31.446 ;
     RECT  0.103 33.93 0.203 33.948 ;
     RECT  0.103 34.776 0.203 34.794 ;
     RECT  0.103 35.55 0.203 35.568 ;
     RECT  0.103 38.412 0.203 39.114 ;
     RECT  0.103 51.516 0.203 51.849 ;
     RECT  0.103 52.956 0.203 56.79 ;
     RECT  0.203 17.046 0.239 18.144 ;
     RECT  0.139 36.756 0.239 37.494 ;
     RECT  0.203 53.838 0.239 53.856 ;
     RECT  0.203 54.801 0.239 56.79 ;
     RECT  0.139 41.076 0.247 45.558 ;
     RECT  0.203 39.096 0.347 39.114 ;
     RECT  0.247 40.68 0.347 45.558 ;
     RECT  0.203 20.088 0.499 25.812 ;
     RECT  0.103 26.568 0.499 27.324 ;
     RECT  0.103 57.888 0.499 63.612 ;
     RECT  0.175 64.368 0.499 67.86 ;
     RECT  0.175 14.454 0.535 14.544 ;
     RECT  0.347 42.3 0.535 45.558 ;
     RECT  0.103 46.512 0.535 46.53 ;
     RECT  0.103 47.736 0.535 48.15 ;
     RECT  0.239 54.882 0.535 56.79 ;
     RECT  0.535 14.22 0.563 14.544 ;
     RECT  0.103 12.996 0.571 13.014 ;
     RECT  0.563 14.22 0.571 14.472 ;
     RECT  0.571 12.996 1.111 14.472 ;
     RECT  0.499 20.088 1.147 27.324 ;
     RECT  0.535 42.3 1.147 48.15 ;
     RECT  0.103 49.176 1.147 49.464 ;
     RECT  0.203 52.956 1.147 52.974 ;
     RECT  0.499 57.888 1.147 67.86 ;
     RECT  1.147 20.016 1.183 27.324 ;
     RECT  0.103 32.976 1.183 32.994 ;
     RECT  1.147 57.888 1.219 68.4 ;
     RECT  1.183 32.976 1.283 33.174 ;
     RECT  1.147 42.264 1.399 49.464 ;
     RECT  1.111 12.798 1.723 14.472 ;
     RECT  0.239 36.756 1.723 36.774 ;
     RECT  1.399 42.264 1.723 49.572 ;
     RECT  1.723 51.606 1.759 51.624 ;
     RECT  1.219 57.888 2.155 68.67 ;
     RECT  1.723 12.798 2.16 14.706 ;
     RECT  0.203 16.236 2.16 16.254 ;
     RECT  0.239 17.046 2.16 17.064 ;
     RECT  0.239 18.126 2.16 18.144 ;
     RECT  1.147 18.936 2.16 18.954 ;
     RECT  1.183 19.746 2.16 27.324 ;
     RECT  1.147 30.006 2.16 30.024 ;
     RECT  2.155 31.698 2.16 31.716 ;
     RECT  1.283 32.976 2.16 32.994 ;
     RECT  1.147 34.596 2.16 34.614 ;
     RECT  1.723 36.288 2.16 36.774 ;
     RECT  1.147 40.266 2.16 40.284 ;
     RECT  0.347 41.076 2.16 41.094 ;
     RECT  1.723 41.922 2.16 50.076 ;
     RECT  1.759 51.606 2.16 52.164 ;
     RECT  1.147 52.956 2.16 53.694 ;
     RECT  0.535 54.882 2.16 56.862 ;
     RECT  2.155 57.654 2.16 68.67 ;
     RECT  2.16 2.151 20.412 85.329 ;
     RECT  20.412 39.294 20.435 39.78 ;
     RECT  20.412 28.962 20.471 31.446 ;
     RECT  20.412 34.326 20.471 34.92 ;
     RECT  20.412 35.676 20.471 36.144 ;
     RECT  20.412 37.836 20.471 38.304 ;
     RECT  20.412 41.49 20.471 42.354 ;
     RECT  20.471 29.376 20.507 30.294 ;
     RECT  20.412 32.616 20.507 33.138 ;
     RECT  20.412 36.936 20.507 36.954 ;
     RECT  20.471 41.49 20.507 41.814 ;
     RECT  20.412 47.628 20.507 85.329 ;
     RECT  20.507 64.566 20.795 85.329 ;
     RECT  20.507 29.376 20.831 29.934 ;
     RECT  20.471 36.054 20.903 36.144 ;
     RECT  20.507 47.628 20.903 63.774 ;
     RECT  20.435 39.294 20.975 39.654 ;
     RECT  20.412 43.614 20.975 43.632 ;
     RECT  20.975 39.294 21.011 39.384 ;
     RECT  20.903 55.926 21.011 63.774 ;
     RECT  21.011 39.294 21.047 39.312 ;
     RECT  20.903 47.628 21.047 54.864 ;
     RECT  20.412 24.876 21.083 27.666 ;
     RECT  20.471 38.016 21.083 38.304 ;
     RECT  21.011 62.136 21.083 63.774 ;
     RECT  21.083 24.876 21.119 27.054 ;
     RECT  21.119 25.182 21.299 27.054 ;
     RECT  21.299 25.326 21.371 27.054 ;
     RECT  21.011 55.926 21.371 61.344 ;
     RECT  20.412 46.008 21.407 46.026 ;
     RECT  21.047 52.83 21.443 54.594 ;
     RECT  21.047 47.628 21.479 52.074 ;
     RECT  20.507 32.616 21.659 32.634 ;
     RECT  21.083 38.016 21.659 38.034 ;
     RECT  21.479 47.628 21.659 47.646 ;
     RECT  21.479 48.708 21.659 52.074 ;
     RECT  21.443 52.911 21.659 54.594 ;
     RECT  21.371 56.034 21.659 61.344 ;
     RECT  21.083 62.244 21.659 63.504 ;
     RECT  21.659 56.034 21.695 60.984 ;
     RECT  21.659 62.244 21.695 63.144 ;
     RECT  21.371 25.326 21.731 26.622 ;
     RECT  21.695 60.966 21.731 60.984 ;
     RECT  20.903 36.054 22.135 36.072 ;
     RECT  22.135 35.982 22.279 36.072 ;
     RECT  21.659 48.708 22.279 52.002 ;
     RECT  20.412 2.151 22.464 23.886 ;
     RECT  21.731 25.956 22.464 26.622 ;
     RECT  20.831 29.376 22.464 29.394 ;
     RECT  20.471 31.428 22.464 31.446 ;
     RECT  20.471 34.326 22.464 34.884 ;
     RECT  22.279 35.982 22.464 36.144 ;
     RECT  20.507 41.49 22.464 41.508 ;
     RECT  22.279 48.402 22.464 52.002 ;
     RECT  21.659 52.911 22.464 53.964 ;
     RECT  22.135 54.72 22.464 54.738 ;
     RECT  21.695 56.034 22.464 60.174 ;
     RECT  21.695 62.586 22.464 63.144 ;
     RECT  20.795 64.908 22.464 85.329 ;
     RECT  22.464 2.151 38.687 85.329 ;
     RECT  38.687 2.151 117.288 65.7 ;
     RECT  117.288 31.536 118.075 32.409 ;
     RECT  117.288 33.318 118.075 33.336 ;
     RECT  117.288 34.128 118.075 35.496 ;
     RECT  117.288 36.666 118.075 63.774 ;
     RECT  118.075 31.536 118.111 33.336 ;
     RECT  118.075 34.128 118.111 63.774 ;
     RECT  117.288 2.151 118.435 27.666 ;
     RECT  117.288 28.458 118.435 28.944 ;
     RECT  118.435 2.151 118.471 28.944 ;
     RECT  118.111 31.536 118.795 63.774 ;
     RECT  118.471 2.151 119.34 29.052 ;
     RECT  118.795 30.816 119.34 63.774 ;
     RECT  117.288 64.98 119.34 65.7 ;
     RECT  38.687 66.951 119.34 85.329 ;
     RECT  119.34 2.151 138.24 85.329 ;
    LAYER M3 ;
     RECT  2.415 2.143 2.505 2.413 ;
     RECT  7.815 2.143 7.905 2.413 ;
     RECT  13.215 2.143 13.305 2.413 ;
     RECT  18.615 2.143 18.705 2.413 ;
     RECT  24.015 2.143 24.105 2.413 ;
     RECT  29.415 2.143 29.505 2.413 ;
     RECT  34.815 2.143 34.905 2.413 ;
     RECT  40.215 2.143 40.305 2.413 ;
     RECT  45.615 2.143 45.705 2.413 ;
     RECT  51.015 2.143 51.105 2.413 ;
     RECT  56.415 2.143 56.505 2.413 ;
     RECT  61.815 2.143 61.905 2.413 ;
     RECT  67.215 2.143 67.305 2.413 ;
     RECT  72.615 2.143 72.705 2.413 ;
     RECT  78.015 2.143 78.105 2.413 ;
     RECT  83.415 2.143 83.505 2.413 ;
     RECT  88.815 2.143 88.905 2.413 ;
     RECT  94.215 2.143 94.305 2.413 ;
     RECT  99.615 2.143 99.705 2.413 ;
     RECT  105.015 2.143 105.105 2.413 ;
     RECT  110.415 2.143 110.505 2.413 ;
     RECT  115.815 2.143 115.905 2.413 ;
     RECT  121.215 2.143 121.305 2.413 ;
     RECT  126.615 2.143 126.705 2.413 ;
     RECT  132.015 2.143 132.105 2.413 ;
     RECT  137.415 2.143 137.505 2.413 ;
     RECT  2.415 2.413 2.697 12.865 ;
     RECT  2.376 12.865 2.697 12.901 ;
     RECT  2.376 12.901 2.754 12.991 ;
     RECT  3.672 12.793 3.69 13.135 ;
     RECT  1.116 12.793 1.134 13.261 ;
     RECT  2.376 12.991 2.862 13.261 ;
     RECT  1.116 13.261 2.862 13.405 ;
     RECT  3.672 13.135 3.798 13.405 ;
     RECT  1.116 13.405 3.798 13.441 ;
     RECT  5.004 13.171 5.022 13.441 ;
     RECT  1.116 13.441 5.022 13.631 ;
     RECT  0.108 12.991 0.126 13.639 ;
     RECT  1.116 13.631 4.266 13.639 ;
     RECT  7.815 2.413 8.097 13.711 ;
     RECT  0.108 13.639 4.266 13.901 ;
     RECT  6.012 13.261 6.03 13.909 ;
     RECT  7.308 13.711 8.097 13.909 ;
     RECT  7.236 13.909 8.097 13.981 ;
     RECT  9.36 13.909 9.378 13.981 ;
     RECT  7.2 13.981 8.097 14.071 ;
     RECT  11.304 13.981 11.322 14.099 ;
     RECT  5.94 13.909 6.03 14.215 ;
     RECT  9.252 13.981 9.378 14.251 ;
     RECT  21.924 14.107 21.942 14.341 ;
     RECT  10.332 14.203 10.35 14.449 ;
     RECT  13.215 2.413 13.497 14.449 ;
     RECT  2.34 13.901 4.266 14.521 ;
     RECT  5.004 13.631 5.022 14.521 ;
     RECT  12.96 14.449 13.497 14.521 ;
     RECT  21.528 14.341 21.942 14.611 ;
     RECT  5.94 14.215 6.246 14.639 ;
     RECT  12.96 14.521 14.058 14.639 ;
     RECT  21.456 14.611 21.942 14.647 ;
     RECT  0.108 13.901 1.134 14.669 ;
     RECT  0.576 14.669 1.134 14.683 ;
     RECT  2.34 14.521 5.022 14.683 ;
     RECT  6.228 14.639 6.246 14.719 ;
     RECT  7.128 14.071 8.097 14.719 ;
     RECT  9.108 14.251 9.378 14.719 ;
     RECT  10.332 14.449 10.818 14.719 ;
     RECT  6.228 14.719 8.097 14.765 ;
     RECT  6.984 14.765 8.097 14.791 ;
     RECT  9.108 14.719 10.818 14.791 ;
     RECT  12.024 14.755 12.042 14.813 ;
     RECT  14.868 14.611 14.886 14.819 ;
     RECT  0.576 14.683 5.022 14.861 ;
     RECT  1.728 14.861 5.022 14.875 ;
     RECT  6.984 14.791 10.818 14.917 ;
     RECT  20.304 14.143 20.322 14.989 ;
     RECT  21.348 14.647 21.942 14.989 ;
     RECT  1.728 14.875 5.13 15.053 ;
     RECT  2.304 15.053 5.13 15.115 ;
     RECT  6.984 14.917 10.926 15.179 ;
     RECT  14.364 14.881 14.382 15.179 ;
     RECT  6.984 15.179 10.206 15.251 ;
     RECT  10.944 15.295 10.962 15.331 ;
     RECT  10.944 15.331 11.106 15.355 ;
     RECT  11.88 15.025 11.898 15.355 ;
     RECT  2.304 15.115 5.166 15.421 ;
     RECT  0.576 14.861 0.594 15.437 ;
     RECT  6.228 14.765 6.246 15.493 ;
     RECT  10.944 15.355 11.898 15.601 ;
     RECT  13.104 14.639 13.59 15.601 ;
     RECT  20.304 14.989 21.942 15.871 ;
     RECT  0.144 15.547 0.234 15.917 ;
     RECT  2.304 15.421 5.49 15.961 ;
     RECT  6.228 15.493 6.426 15.961 ;
     RECT  7.164 15.251 10.206 16.105 ;
     RECT  10.944 15.601 13.59 16.105 ;
     RECT  20.232 15.871 21.942 16.105 ;
     RECT  2.304 15.961 6.426 16.141 ;
     RECT  7.164 16.105 13.59 16.141 ;
     RECT  20.232 16.105 21.978 16.267 ;
     RECT  2.304 16.141 13.59 16.681 ;
     RECT  0.108 16.075 0.126 16.771 ;
     RECT  20.232 16.267 22.05 16.807 ;
     RECT  2.304 16.681 14.31 17.069 ;
     RECT  2.304 17.069 5.958 17.105 ;
     RECT  6.768 17.069 14.31 17.105 ;
     RECT  1.116 17.083 1.134 17.309 ;
     RECT  0.108 16.771 0.198 17.323 ;
     RECT  2.304 17.105 5.85 17.339 ;
     RECT  20.16 16.807 22.05 17.383 ;
     RECT  20.088 17.383 22.05 17.491 ;
     RECT  6.768 17.105 13.734 17.609 ;
     RECT  2.304 17.339 5.742 17.761 ;
     RECT  2.268 17.761 5.742 17.837 ;
     RECT  6.768 17.609 13.626 17.923 ;
     RECT  2.304 17.837 5.742 18.091 ;
     RECT  6.516 17.923 13.626 18.091 ;
     RECT  0.108 17.323 0.342 18.221 ;
     RECT  2.304 18.091 13.626 18.329 ;
     RECT  18.615 2.413 18.897 18.535 ;
     RECT  20.016 17.491 22.05 18.571 ;
     RECT  2.376 18.329 13.626 18.661 ;
     RECT  1.152 17.899 1.17 18.667 ;
     RECT  17.964 18.535 18.897 18.667 ;
     RECT  17.964 18.667 19.098 18.715 ;
     RECT  17.712 18.715 19.098 18.733 ;
     RECT  121.215 2.413 121.497 18.733 ;
     RECT  2.376 18.661 14.274 18.763 ;
     RECT  120.96 18.733 121.497 18.769 ;
     RECT  0.108 18.221 0.198 18.833 ;
     RECT  16.2 18.769 16.218 19.237 ;
     RECT  17.424 18.733 19.098 19.237 ;
     RECT  2.376 18.763 14.418 19.273 ;
     RECT  120.384 18.769 121.497 19.273 ;
     RECT  117.756 19.237 117.774 19.309 ;
     RECT  0.144 18.833 0.162 19.612 ;
     RECT  56.415 2.413 56.697 19.741 ;
     RECT  78.015 2.413 78.297 19.741 ;
     RECT  99.615 2.413 99.897 19.741 ;
     RECT  20.016 18.571 22.194 19.777 ;
     RECT  24.015 2.413 24.297 19.777 ;
     RECT  34.815 2.413 35.097 19.777 ;
     RECT  45.615 2.413 45.897 19.777 ;
     RECT  61.815 2.413 62.097 19.777 ;
     RECT  67.215 2.413 67.497 19.777 ;
     RECT  88.815 2.413 89.097 19.777 ;
     RECT  110.415 2.413 110.697 19.777 ;
     RECT  1.152 18.667 1.206 19.813 ;
     RECT  2.376 19.273 14.67 19.813 ;
     RECT  119.412 19.531 119.43 19.813 ;
     RECT  20.016 19.777 22.842 19.849 ;
     RECT  30.888 19.777 30.906 19.849 ;
     RECT  42.768 19.777 42.786 19.849 ;
     RECT  54.72 19.741 54.738 19.849 ;
     RECT  61.815 19.777 62.802 19.849 ;
     RECT  74.664 19.741 74.682 19.849 ;
     RECT  86.652 19.777 86.67 19.849 ;
     RECT  98.604 19.741 98.622 19.849 ;
     RECT  106.704 19.777 106.722 19.849 ;
     RECT  119.412 19.813 119.466 19.849 ;
     RECT  120.276 19.273 121.497 19.849 ;
     RECT  24.015 19.777 24.354 19.877 ;
     RECT  30.888 19.849 30.978 19.877 ;
     RECT  34.815 19.777 35.154 19.877 ;
     RECT  42.768 19.849 42.858 19.877 ;
     RECT  45.615 19.777 45.954 19.877 ;
     RECT  54.72 19.849 54.81 19.877 ;
     RECT  56.415 19.741 56.754 19.877 ;
     RECT  61.815 19.849 62.874 19.877 ;
     RECT  67.215 19.777 67.554 19.877 ;
     RECT  74.664 19.849 74.754 19.877 ;
     RECT  78.015 19.741 78.354 19.877 ;
     RECT  86.652 19.849 86.742 19.877 ;
     RECT  88.815 19.777 89.154 19.877 ;
     RECT  98.604 19.849 98.694 19.877 ;
     RECT  99.615 19.741 99.954 19.877 ;
     RECT  106.704 19.849 106.794 19.877 ;
     RECT  110.415 19.777 110.79 19.877 ;
     RECT  1.152 19.813 14.67 19.885 ;
     RECT  24.015 19.877 24.297 19.912 ;
     RECT  34.815 19.877 35.097 19.912 ;
     RECT  45.615 19.877 45.897 19.912 ;
     RECT  56.415 19.877 56.697 19.912 ;
     RECT  67.215 19.877 67.497 19.912 ;
     RECT  78.015 19.877 78.297 19.912 ;
     RECT  88.815 19.877 89.097 19.912 ;
     RECT  99.615 19.877 99.897 19.912 ;
     RECT  110.415 19.877 110.718 19.912 ;
     RECT  117.756 19.309 118.494 19.921 ;
     RECT  119.412 19.849 121.497 19.921 ;
     RECT  20.016 19.849 22.914 19.949 ;
     RECT  23.904 19.912 24.297 19.949 ;
     RECT  30.96 19.877 30.978 19.949 ;
     RECT  34.704 19.912 35.097 19.949 ;
     RECT  42.84 19.877 42.858 19.949 ;
     RECT  45.504 19.912 45.897 19.949 ;
     RECT  54.792 19.877 54.81 19.949 ;
     RECT  56.304 19.912 56.697 19.949 ;
     RECT  62.856 19.877 62.874 19.949 ;
     RECT  67.104 19.912 67.497 19.949 ;
     RECT  74.736 19.877 74.754 19.949 ;
     RECT  77.904 19.912 78.297 19.949 ;
     RECT  86.724 19.877 86.742 19.949 ;
     RECT  88.704 19.912 89.097 19.949 ;
     RECT  98.676 19.877 98.694 19.949 ;
     RECT  99.504 19.912 99.897 19.949 ;
     RECT  106.776 19.877 106.794 19.949 ;
     RECT  110.304 19.912 110.718 19.949 ;
     RECT  1.152 19.885 14.706 20.045 ;
     RECT  0.108 19.612 0.198 20.083 ;
     RECT  1.152 20.045 1.17 20.083 ;
     RECT  114.408 20.281 114.426 20.317 ;
     RECT  2.304 20.045 14.706 20.347 ;
     RECT  2.304 20.347 15.354 20.353 ;
     RECT  16.2 19.237 19.098 20.353 ;
     RECT  115.815 2.413 116.097 20.353 ;
     RECT  0.108 20.083 1.17 20.525 ;
     RECT  117.756 19.921 121.497 20.821 ;
     RECT  2.304 20.353 19.098 21.001 ;
     RECT  34.815 19.949 35.097 21.001 ;
     RECT  1.152 20.525 1.17 21.067 ;
     RECT  20.016 19.949 22.338 21.067 ;
     RECT  24.015 19.949 24.297 21.091 ;
     RECT  115.704 20.353 116.097 21.091 ;
     RECT  23.94 21.091 24.297 21.115 ;
     RECT  32.4 21.091 32.49 21.115 ;
     RECT  110.415 19.949 110.697 21.115 ;
     RECT  20.016 21.067 22.986 21.119 ;
     RECT  23.796 21.115 24.297 21.127 ;
     RECT  30.78 21.091 30.798 21.127 ;
     RECT  115.704 21.091 116.298 21.163 ;
     RECT  31.716 21.115 32.49 21.199 ;
     RECT  34.815 21.001 35.37 21.199 ;
     RECT  37.584 20.191 37.602 21.199 ;
     RECT  117.432 20.821 121.497 21.199 ;
     RECT  34.668 21.199 35.37 21.235 ;
     RECT  114.408 20.317 114.786 21.235 ;
     RECT  30.78 21.127 30.87 21.263 ;
     RECT  31.716 21.199 32.85 21.271 ;
     RECT  34.02 21.235 35.37 21.271 ;
     RECT  117.36 21.199 121.497 21.271 ;
     RECT  29.415 2.413 29.697 21.347 ;
     RECT  40.215 2.413 40.497 21.347 ;
     RECT  45.615 19.949 45.897 21.347 ;
     RECT  51.015 2.413 51.297 21.347 ;
     RECT  56.415 19.949 56.697 21.347 ;
     RECT  61.815 19.877 62.097 21.347 ;
     RECT  67.215 19.949 67.497 21.347 ;
     RECT  72.615 2.413 72.897 21.347 ;
     RECT  78.015 19.949 78.297 21.347 ;
     RECT  83.415 2.413 83.697 21.347 ;
     RECT  88.815 19.949 89.097 21.347 ;
     RECT  94.215 2.413 94.497 21.347 ;
     RECT  99.615 19.949 99.897 21.347 ;
     RECT  105.015 2.413 105.297 21.347 ;
     RECT  0.108 20.525 0.126 21.355 ;
     RECT  1.152 21.067 1.35 21.355 ;
     RECT  31.716 21.271 35.37 21.361 ;
     RECT  26.784 21.271 26.874 21.389 ;
     RECT  31.464 21.361 35.37 21.389 ;
     RECT  37.584 21.199 37.674 21.389 ;
     RECT  112.824 21.091 112.95 21.389 ;
     RECT  114.408 21.235 114.894 21.389 ;
     RECT  115.704 21.163 116.478 21.389 ;
     RECT  110.415 21.115 111.006 21.397 ;
     RECT  37.656 21.389 37.674 21.425 ;
     RECT  34.164 21.389 35.37 21.497 ;
     RECT  36.54 21.361 36.63 21.497 ;
     RECT  36.54 21.497 36.558 21.505 ;
     RECT  115.815 21.389 116.478 21.505 ;
     RECT  117.324 21.271 121.497 21.505 ;
     RECT  26.784 21.389 26.802 21.533 ;
     RECT  31.464 21.389 32.166 21.533 ;
     RECT  35.928 21.505 36.558 21.533 ;
     RECT  115.815 21.505 121.497 21.569 ;
     RECT  29.415 21.347 29.505 21.617 ;
     RECT  34.164 21.497 34.905 21.617 ;
     RECT  40.215 21.347 40.305 21.617 ;
     RECT  45.615 21.347 45.705 21.617 ;
     RECT  51.015 21.347 51.105 21.617 ;
     RECT  56.415 21.347 56.505 21.617 ;
     RECT  61.815 21.347 61.905 21.617 ;
     RECT  67.215 21.347 67.305 21.617 ;
     RECT  72.615 21.347 72.705 21.617 ;
     RECT  78.015 21.347 78.105 21.617 ;
     RECT  83.415 21.347 83.505 21.617 ;
     RECT  88.815 21.347 88.905 21.617 ;
     RECT  94.215 21.347 94.305 21.617 ;
     RECT  99.615 21.347 99.705 21.617 ;
     RECT  105.015 21.347 105.105 21.617 ;
     RECT  110.415 21.397 111.114 21.617 ;
     RECT  115.815 21.569 115.905 21.617 ;
     RECT  114.408 21.389 114.678 21.631 ;
     RECT  35.928 21.533 35.946 21.659 ;
     RECT  111.096 21.617 111.114 21.659 ;
     RECT  114.012 21.631 114.678 21.725 ;
     RECT  0.108 21.355 1.35 21.767 ;
     RECT  0.108 21.767 1.17 21.803 ;
     RECT  2.304 21.001 19.134 21.803 ;
     RECT  39.348 20.659 39.366 21.917 ;
     RECT  34.164 21.617 34.182 21.929 ;
     RECT  20.016 21.119 22.806 21.931 ;
     RECT  23.796 21.127 24.534 21.931 ;
     RECT  32.148 21.533 32.166 21.965 ;
     RECT  2.304 21.803 5.454 22.123 ;
     RECT  20.016 21.931 24.534 22.343 ;
     RECT  20.016 22.343 23.958 22.379 ;
     RECT  28.512 21.001 28.53 22.397 ;
     RECT  2.268 22.123 5.454 22.585 ;
     RECT  6.192 21.803 19.134 22.585 ;
     RECT  2.268 22.585 19.134 22.603 ;
     RECT  20.016 22.379 23.346 22.829 ;
     RECT  2.232 22.603 19.134 22.891 ;
     RECT  20.016 22.829 22.338 22.891 ;
     RECT  2.232 22.891 22.338 22.919 ;
     RECT  5.436 22.919 22.338 23.009 ;
     RECT  23.328 22.829 23.346 23.009 ;
     RECT  114.012 21.725 114.03 23.161 ;
     RECT  0.108 21.803 0.558 23.213 ;
     RECT  5.508 23.009 22.338 23.279 ;
     RECT  5.652 23.279 22.338 23.76 ;
     RECT  114.012 23.161 114.642 23.76 ;
     RECT  116.856 21.569 121.497 23.76 ;
     RECT  5.652 23.76 121.497 23.819 ;
     RECT  2.268 22.919 4.59 24.061 ;
     RECT  2.268 24.061 4.878 24.197 ;
     RECT  0.108 23.213 0.342 24.235 ;
     RECT  1.152 23.659 1.17 24.235 ;
     RECT  2.304 24.197 4.878 24.637 ;
     RECT  5.796 23.819 121.497 24.637 ;
     RECT  2.304 24.637 121.497 24.701 ;
     RECT  2.304 24.701 5.346 24.809 ;
     RECT  2.304 24.809 5.166 25.051 ;
     RECT  2.268 25.051 5.166 25.325 ;
     RECT  0.108 24.235 1.17 25.387 ;
     RECT  6.084 24.701 121.497 25.519 ;
     RECT  2.304 25.325 5.166 25.591 ;
     RECT  5.904 25.519 121.497 25.591 ;
     RECT  0.108 25.387 1.206 25.817 ;
     RECT  0.324 25.817 1.206 26.321 ;
     RECT  0.324 26.321 1.17 26.539 ;
     RECT  0.108 26.539 1.17 26.765 ;
     RECT  0.108 26.765 0.342 27.149 ;
     RECT  0.108 27.149 0.234 27.239 ;
     RECT  1.152 26.765 1.17 27.239 ;
     RECT  0.108 27.239 0.162 27.248 ;
     RECT  0.108 27.248 0.126 27.329 ;
     RECT  2.304 25.591 121.497 27.355 ;
     RECT  2.268 27.355 121.497 27.533 ;
     RECT  2.304 27.533 121.497 28.109 ;
     RECT  2.304 28.109 21.402 28.205 ;
     RECT  0.108 28.363 0.126 28.411 ;
     RECT  0.108 28.411 0.198 28.556 ;
     RECT  0.144 28.556 0.198 28.651 ;
     RECT  0.144 28.651 0.342 28.781 ;
     RECT  0.144 28.781 0.162 29.021 ;
     RECT  2.304 28.205 21.366 29.165 ;
     RECT  22.212 28.109 121.497 29.399 ;
     RECT  22.284 29.399 121.497 29.597 ;
     RECT  1.152 29.035 1.17 30.029 ;
     RECT  2.34 29.165 21.366 30.283 ;
     RECT  2.304 30.283 21.366 30.335 ;
     RECT  22.356 29.597 121.497 30.475 ;
     RECT  2.34 30.335 21.366 31.147 ;
     RECT  2.304 31.147 21.366 31.243 ;
     RECT  22.284 30.475 121.497 31.243 ;
     RECT  0.108 30.073 0.198 31.517 ;
     RECT  0.108 31.517 0.162 31.565 ;
     RECT  2.304 31.243 121.497 31.693 ;
     RECT  0.144 31.565 0.162 31.805 ;
     RECT  2.16 31.693 121.497 31.853 ;
     RECT  2.268 31.853 121.497 32.531 ;
     RECT  2.304 32.531 121.497 32.639 ;
     RECT  0.108 32.587 0.342 32.717 ;
     RECT  0.108 32.717 0.162 32.909 ;
     RECT  0.108 32.909 0.126 32.999 ;
     RECT  1.152 33.067 1.17 33.115 ;
     RECT  1.152 33.115 1.278 33.179 ;
     RECT  1.152 33.179 1.206 33.197 ;
     RECT  2.304 32.639 21.366 33.421 ;
     RECT  2.268 33.421 21.366 33.485 ;
     RECT  22.176 32.639 121.497 33.643 ;
     RECT  0.144 33.739 0.162 33.916 ;
     RECT  1.152 33.197 1.17 34.619 ;
     RECT  2.304 33.485 21.366 34.655 ;
     RECT  0.108 33.916 0.198 34.799 ;
     RECT  22.14 33.643 121.497 34.889 ;
     RECT  0.144 34.799 0.198 35.419 ;
     RECT  0.144 35.419 0.234 35.545 ;
     RECT  2.34 34.655 21.366 35.545 ;
     RECT  0.108 35.545 0.234 35.693 ;
     RECT  0.108 35.693 0.198 35.837 ;
     RECT  0.108 35.837 0.162 35.885 ;
     RECT  2.304 35.545 21.366 35.941 ;
     RECT  22.212 34.889 121.497 35.947 ;
     RECT  22.176 35.947 121.497 35.977 ;
     RECT  22.14 35.977 121.497 35.995 ;
     RECT  2.268 35.941 21.366 36.283 ;
     RECT  1.728 36.283 21.366 36.523 ;
     RECT  22.104 35.995 121.497 36.523 ;
     RECT  1.728 36.523 121.497 36.653 ;
     RECT  0.144 35.885 0.162 36.715 ;
     RECT  0.108 36.715 0.162 36.779 ;
     RECT  2.304 36.653 121.497 36.893 ;
     RECT  0.144 36.779 0.162 37.291 ;
     RECT  0.144 37.291 0.342 37.421 ;
     RECT  0.144 37.421 0.234 37.499 ;
     RECT  2.304 36.893 21.654 38.039 ;
     RECT  0.144 37.499 0.162 38.407 ;
     RECT  22.464 36.893 121.497 38.827 ;
     RECT  2.304 38.039 21.366 38.849 ;
     RECT  0.108 38.407 0.198 38.923 ;
     RECT  0.108 38.923 0.342 39.115 ;
     RECT  22.356 38.827 121.497 39.115 ;
     RECT  0.108 39.115 0.414 39.293 ;
     RECT  22.284 39.115 121.497 39.307 ;
     RECT  22.212 39.307 121.497 39.499 ;
     RECT  22.176 39.499 121.497 39.629 ;
     RECT  2.304 38.849 19.422 40.019 ;
     RECT  1.152 39.067 1.17 40.289 ;
     RECT  0.108 39.293 0.234 40.459 ;
     RECT  0.108 40.459 0.45 40.637 ;
     RECT  0.108 40.637 0.378 40.685 ;
     RECT  20.16 38.849 21.366 40.747 ;
     RECT  22.212 39.629 121.497 40.747 ;
     RECT  2.415 40.019 19.422 40.843 ;
     RECT  20.16 40.747 121.497 40.843 ;
     RECT  0.108 40.685 0.342 40.877 ;
     RECT  2.415 40.843 121.497 40.981 ;
     RECT  2.304 40.981 121.497 41.512 ;
     RECT  0.108 40.877 0.198 41.611 ;
     RECT  2.268 41.512 121.497 41.711 ;
     RECT  1.152 41.131 1.17 41.917 ;
     RECT  2.268 41.711 120.438 41.917 ;
     RECT  0.108 41.611 0.342 41.933 ;
     RECT  0.108 41.933 0.27 42.125 ;
     RECT  1.152 41.917 120.438 42.317 ;
     RECT  2.34 42.317 120.438 42.359 ;
     RECT  2.34 42.359 117.774 42.485 ;
     RECT  0.108 42.125 0.162 42.859 ;
     RECT  1.152 42.317 1.242 42.859 ;
     RECT  118.584 42.359 120.438 42.899 ;
     RECT  2.34 42.485 117.414 43.085 ;
     RECT  0.108 42.859 1.242 43.097 ;
     RECT  2.34 43.085 117.378 43.147 ;
     RECT  2.304 43.147 117.378 43.243 ;
     RECT  118.584 42.899 119.934 43.295 ;
     RECT  1.224 43.097 1.242 43.367 ;
     RECT  2.268 43.243 117.378 43.723 ;
     RECT  118.584 43.295 119.862 43.835 ;
     RECT  2.232 43.723 117.378 43.907 ;
     RECT  2.268 43.907 117.378 43.951 ;
     RECT  0.108 43.097 0.162 44.011 ;
     RECT  0.108 44.011 0.558 44.213 ;
     RECT  118.584 43.835 119.754 44.213 ;
     RECT  1.152 44.395 1.17 44.443 ;
     RECT  1.152 44.443 1.278 44.519 ;
     RECT  1.152 44.519 1.206 44.528 ;
     RECT  118.62 44.213 119.754 44.581 ;
     RECT  2.268 43.951 117.414 44.717 ;
     RECT  118.62 44.581 119.898 44.717 ;
     RECT  118.62 44.717 119.754 44.789 ;
     RECT  0.108 44.213 0.162 45.067 ;
     RECT  1.152 44.528 1.17 45.067 ;
     RECT  0.108 45.067 1.17 45.185 ;
     RECT  2.304 44.717 117.414 45.293 ;
     RECT  118.62 44.789 119.61 45.419 ;
     RECT  0.108 45.185 0.558 45.491 ;
     RECT  119.088 45.419 119.61 45.661 ;
     RECT  119.088 45.661 119.79 45.677 ;
     RECT  4.572 45.293 117.414 45.689 ;
     RECT  2.304 45.293 3.798 46.139 ;
     RECT  5.148 45.689 117.414 46.201 ;
     RECT  119.268 45.677 119.79 46.201 ;
     RECT  0.144 45.491 0.558 46.219 ;
     RECT  119.268 46.201 120.006 46.337 ;
     RECT  5.148 46.201 117.45 46.445 ;
     RECT  0.108 46.219 0.558 46.535 ;
     RECT  5.148 46.445 117.414 46.535 ;
     RECT  119.268 46.337 119.646 46.741 ;
     RECT  2.304 46.139 3.546 47.011 ;
     RECT  2.304 47.011 3.798 47.083 ;
     RECT  118.584 46.741 119.646 47.155 ;
     RECT  2.304 47.083 3.978 47.191 ;
     RECT  5.148 46.535 5.166 47.191 ;
     RECT  2.304 47.191 5.166 47.309 ;
     RECT  118.584 47.155 119.79 47.309 ;
     RECT  5.976 46.535 117.414 47.389 ;
     RECT  1.332 46.699 1.35 47.417 ;
     RECT  0.324 46.535 0.558 47.467 ;
     RECT  5.796 47.389 117.414 47.489 ;
     RECT  0.324 47.467 1.17 47.563 ;
     RECT  6.372 47.489 117.414 47.659 ;
     RECT  6.372 47.659 117.45 47.722 ;
     RECT  118.584 47.309 119.754 47.723 ;
     RECT  6.372 47.722 117.486 47.789 ;
     RECT  118.584 47.723 119.646 47.849 ;
     RECT  0.108 47.563 1.17 47.933 ;
     RECT  2.304 47.309 4.878 48.119 ;
     RECT  0.108 47.933 0.342 48.173 ;
     RECT  1.152 47.933 1.17 48.331 ;
     RECT  6.372 47.789 117.414 48.361 ;
     RECT  6.264 48.361 117.414 48.541 ;
     RECT  1.152 48.331 1.422 48.695 ;
     RECT  118.584 47.849 119.61 48.775 ;
     RECT  2.304 48.119 4.626 48.901 ;
     RECT  2.304 48.901 4.914 49.009 ;
     RECT  2.232 49.009 5.202 49.243 ;
     RECT  2.16 49.243 5.202 49.351 ;
     RECT  118.584 48.775 119.754 49.441 ;
     RECT  0.108 49.171 0.126 49.517 ;
     RECT  2.16 49.351 5.238 49.541 ;
     RECT  1.404 48.695 1.422 49.577 ;
     RECT  6.228 48.541 117.414 49.621 ;
     RECT  0.144 49.627 0.162 49.675 ;
     RECT  0.144 49.675 0.342 49.805 ;
     RECT  6.192 49.621 117.414 50.045 ;
     RECT  2.16 49.541 5.202 50.053 ;
     RECT  6.228 50.045 117.414 50.081 ;
     RECT  118.584 49.441 119.898 50.117 ;
     RECT  1.728 50.053 5.202 50.189 ;
     RECT  0.216 49.805 0.342 50.251 ;
     RECT  6.372 50.081 117.414 50.284 ;
     RECT  2.304 50.189 5.202 50.359 ;
     RECT  0.216 50.251 0.378 50.381 ;
     RECT  0.216 50.381 0.234 50.477 ;
     RECT  6.372 50.284 117.45 50.477 ;
     RECT  2.304 50.359 5.418 50.779 ;
     RECT  118.584 50.117 119.61 50.863 ;
     RECT  2.304 50.779 5.634 50.971 ;
     RECT  6.372 50.477 117.414 50.971 ;
     RECT  118.584 50.863 119.898 51.061 ;
     RECT  118.584 51.061 120.114 51.161 ;
     RECT  119.088 51.161 120.114 51.269 ;
     RECT  0.144 50.731 0.162 51.511 ;
     RECT  2.304 50.971 117.414 51.601 ;
     RECT  119.088 51.269 119.862 51.773 ;
     RECT  0.108 51.511 0.198 51.854 ;
     RECT  119.088 51.773 119.79 51.907 ;
     RECT  118.656 51.907 119.79 51.979 ;
     RECT  0.324 51.883 0.342 52.075 ;
     RECT  118.584 51.979 119.79 52.079 ;
     RECT  0.324 52.075 0.414 52.253 ;
     RECT  118.62 52.079 119.79 52.277 ;
     RECT  118.62 52.277 119.718 52.583 ;
     RECT  1.728 51.601 117.45 52.589 ;
     RECT  118.692 52.583 119.718 52.781 ;
     RECT  2.304 52.589 117.45 52.877 ;
     RECT  0.108 52.651 0.162 53.329 ;
     RECT  119.052 52.781 119.718 53.527 ;
     RECT  1.152 52.747 1.17 53.699 ;
     RECT  0.108 53.329 0.198 53.707 ;
     RECT  118.584 53.527 119.718 53.833 ;
     RECT  118.584 53.833 119.862 54.091 ;
     RECT  118.584 54.091 120.294 54.131 ;
     RECT  2.304 52.877 117.414 54.472 ;
     RECT  2.304 54.472 117.45 54.509 ;
     RECT  0.108 53.707 0.342 54.893 ;
     RECT  2.304 54.509 117.414 54.949 ;
     RECT  1.764 54.949 117.414 54.955 ;
     RECT  118.584 54.131 119.898 54.985 ;
     RECT  118.584 54.985 120.078 55.175 ;
     RECT  0.108 54.893 0.234 55.229 ;
     RECT  1.152 54.955 117.414 55.751 ;
     RECT  118.584 55.175 119.862 55.787 ;
     RECT  1.152 55.751 18.954 55.949 ;
     RECT  1.152 55.949 1.17 56.129 ;
     RECT  118.584 55.787 119.646 56.129 ;
     RECT  2.304 55.949 18.954 56.497 ;
     RECT  19.692 55.751 117.414 56.497 ;
     RECT  118.62 56.129 119.646 56.641 ;
     RECT  0.108 55.229 0.198 56.683 ;
     RECT  2.304 56.497 117.414 56.731 ;
     RECT  0.108 56.683 0.558 56.795 ;
     RECT  2.232 56.731 117.414 56.795 ;
     RECT  0.144 56.795 0.558 56.867 ;
     RECT  0.144 56.867 0.45 56.909 ;
     RECT  5.148 56.795 117.414 57.029 ;
     RECT  2.232 56.795 4.338 57.209 ;
     RECT  118.62 56.641 119.862 57.271 ;
     RECT  118.62 57.271 119.97 57.307 ;
     RECT  0.36 56.909 0.45 57.341 ;
     RECT  118.584 57.307 119.97 57.371 ;
     RECT  0.36 57.341 0.378 57.389 ;
     RECT  3.888 57.209 4.338 57.541 ;
     RECT  2.232 57.209 3.114 57.547 ;
     RECT  5.328 57.029 117.414 57.569 ;
     RECT  2.16 57.547 3.114 57.677 ;
     RECT  5.328 57.569 5.346 57.821 ;
     RECT  118.584 57.371 119.862 57.947 ;
     RECT  6.3 57.569 117.414 57.965 ;
     RECT  3.888 57.541 4.446 58.027 ;
     RECT  2.232 57.677 3.114 58.075 ;
     RECT  3.888 58.027 4.554 58.075 ;
     RECT  2.232 58.075 4.554 58.109 ;
     RECT  0.108 57.643 0.342 58.123 ;
     RECT  118.584 57.947 119.826 58.157 ;
     RECT  2.232 58.109 4.338 58.217 ;
     RECT  118.62 58.157 119.826 58.253 ;
     RECT  0.108 58.123 0.558 58.487 ;
     RECT  5.112 58.123 5.274 58.651 ;
     RECT  6.3 57.965 117.378 58.651 ;
     RECT  5.112 58.651 117.378 58.829 ;
     RECT  2.268 58.217 4.338 58.963 ;
     RECT  5.76 58.829 117.378 59.071 ;
     RECT  119.016 58.253 119.826 59.161 ;
     RECT  119.016 59.161 120.006 59.233 ;
     RECT  118.584 59.233 120.006 59.261 ;
     RECT  0.108 58.487 0.162 59.269 ;
     RECT  5.76 59.071 117.414 59.459 ;
     RECT  2.268 58.963 4.446 59.495 ;
     RECT  118.584 59.261 119.862 59.495 ;
     RECT  118.584 59.495 119.61 59.603 ;
     RECT  2.304 59.495 4.446 59.701 ;
     RECT  2.304 59.701 5.166 60.035 ;
     RECT  2.304 60.035 4.77 60.077 ;
     RECT  6.264 59.459 117.414 60.241 ;
     RECT  118.62 59.603 119.61 60.341 ;
     RECT  0.108 59.269 0.558 60.413 ;
     RECT  118.692 60.341 119.61 60.413 ;
     RECT  119.088 60.413 119.61 60.619 ;
     RECT  2.304 60.077 4.554 60.647 ;
     RECT  0.108 60.413 0.342 60.653 ;
     RECT  119.088 60.619 120.078 60.719 ;
     RECT  0.108 60.653 0.234 60.881 ;
     RECT  2.415 60.647 4.554 61.051 ;
     RECT  5.544 60.241 117.414 61.051 ;
     RECT  119.088 60.719 119.898 61.259 ;
     RECT  119.088 61.259 119.646 61.321 ;
     RECT  118.62 61.321 119.646 61.457 ;
     RECT  0.108 60.881 0.198 61.469 ;
     RECT  2.415 61.051 117.414 61.483 ;
     RECT  2.304 61.483 117.414 61.727 ;
     RECT  4.86 61.727 117.414 61.901 ;
     RECT  5.256 61.901 117.414 62.003 ;
     RECT  5.472 62.003 117.414 62.195 ;
     RECT  0.108 61.469 0.126 62.251 ;
     RECT  119.268 61.457 119.646 62.275 ;
     RECT  118.584 62.275 119.862 62.537 ;
     RECT  118.62 62.537 119.862 62.671 ;
     RECT  2.304 61.727 4.086 62.699 ;
     RECT  118.62 62.671 119.898 62.861 ;
     RECT  5.472 62.195 5.49 62.969 ;
     RECT  118.62 62.861 119.754 63.077 ;
     RECT  6.372 62.195 117.414 63.121 ;
     RECT  6.3 63.121 117.414 63.163 ;
     RECT  119.268 63.077 119.754 63.239 ;
     RECT  5.076 63.211 5.094 63.247 ;
     RECT  4.392 63.247 5.094 63.509 ;
     RECT  6.228 63.163 117.414 63.595 ;
     RECT  6.228 63.595 117.45 63.653 ;
     RECT  2.304 62.699 3.51 63.691 ;
     RECT  2.268 63.691 3.51 63.751 ;
     RECT  4.392 63.509 4.662 63.751 ;
     RECT  6.228 63.653 117.378 63.779 ;
     RECT  119.268 63.239 119.682 63.779 ;
     RECT  6.228 63.779 117.288 63.787 ;
     RECT  5.976 63.787 117.288 63.824 ;
     RECT  0.108 62.251 0.558 64.013 ;
     RECT  0.108 64.013 0.522 64.109 ;
     RECT  2.268 63.751 4.662 64.319 ;
     RECT  6.372 63.824 117.288 64.561 ;
     RECT  5.796 64.561 117.288 64.589 ;
     RECT  5.796 64.589 20.106 64.661 ;
     RECT  21.384 64.589 117.288 64.824 ;
     RECT  21.384 64.824 22.014 64.931 ;
     RECT  21.384 64.931 21.942 65.003 ;
     RECT  0.108 64.109 0.198 65.173 ;
     RECT  0.108 65.173 0.558 65.237 ;
     RECT  119.268 63.779 119.646 65.237 ;
     RECT  2.268 64.319 4.446 65.507 ;
     RECT  119.484 65.237 119.646 65.579 ;
     RECT  4.428 65.507 4.446 65.641 ;
     RECT  4.428 65.641 5.166 65.677 ;
     RECT  119.628 65.579 119.646 65.705 ;
     RECT  4.428 65.677 5.238 65.741 ;
     RECT  2.268 65.507 3.618 65.777 ;
     RECT  5.148 65.741 5.238 65.777 ;
     RECT  0.18 65.237 0.558 65.813 ;
     RECT  6.228 64.661 20.106 65.821 ;
     RECT  5.22 65.777 5.238 65.849 ;
     RECT  6.048 65.821 20.106 65.939 ;
     RECT  2.304 65.777 3.618 66.289 ;
     RECT  6.372 65.939 20.106 66.389 ;
     RECT  0.18 65.813 0.342 66.475 ;
     RECT  2.304 66.289 4.338 66.479 ;
     RECT  6.372 66.389 15.462 66.479 ;
     RECT  0.108 66.475 0.342 66.509 ;
     RECT  6.372 66.479 15.318 66.757 ;
     RECT  5.832 66.757 15.318 66.865 ;
     RECT  24.015 66.943 24.105 66.991 ;
     RECT  29.415 66.943 29.505 66.991 ;
     RECT  2.304 66.479 3.978 67.019 ;
     RECT  5.688 66.865 15.318 67.019 ;
     RECT  23.904 66.991 24.21 67.037 ;
     RECT  1.152 66.955 1.17 67.147 ;
     RECT  28.908 66.991 29.505 67.171 ;
     RECT  24.015 67.037 24.21 67.213 ;
     RECT  28.8 67.171 29.505 67.213 ;
     RECT  34.815 66.943 34.905 67.213 ;
     RECT  40.215 66.943 40.305 67.213 ;
     RECT  45.615 66.943 45.705 67.213 ;
     RECT  51.015 66.943 51.105 67.213 ;
     RECT  56.415 66.943 56.505 67.213 ;
     RECT  61.815 66.943 61.905 67.213 ;
     RECT  67.215 66.943 67.305 67.213 ;
     RECT  72.615 66.943 72.705 67.213 ;
     RECT  78.015 66.943 78.105 67.213 ;
     RECT  83.415 66.943 83.505 67.213 ;
     RECT  88.815 66.943 88.905 67.213 ;
     RECT  94.215 66.943 94.305 67.213 ;
     RECT  99.615 66.943 99.705 67.213 ;
     RECT  105.015 66.943 105.105 67.213 ;
     RECT  110.415 66.943 110.505 67.213 ;
     RECT  115.815 66.943 115.905 67.213 ;
     RECT  3.924 67.019 3.978 67.261 ;
     RECT  16.236 66.389 20.106 67.297 ;
     RECT  0.108 66.509 0.162 67.435 ;
     RECT  1.152 67.147 1.206 67.531 ;
     RECT  5.688 67.019 15.282 67.559 ;
     RECT  16.02 67.297 20.106 67.559 ;
     RECT  36.144 65.821 36.162 67.559 ;
     RECT  38.664 66.361 38.682 67.559 ;
     RECT  3.924 67.261 4.482 67.567 ;
     RECT  0.108 67.435 0.198 67.613 ;
     RECT  6.372 67.559 15.282 67.703 ;
     RECT  7.815 67.703 15.282 67.837 ;
     RECT  16.02 67.559 20.07 67.837 ;
     RECT  0.108 67.613 0.126 67.865 ;
     RECT  2.304 67.019 3.15 67.873 ;
     RECT  3.924 67.567 4.518 67.873 ;
     RECT  2.304 67.873 4.518 67.901 ;
     RECT  2.304 67.901 3.87 68.099 ;
     RECT  39.024 67.711 39.042 68.107 ;
     RECT  40.215 67.213 40.497 68.107 ;
     RECT  2.304 68.099 3.51 68.135 ;
     RECT  2.415 68.135 3.51 68.369 ;
     RECT  27.072 68.251 27.09 68.369 ;
     RECT  1.152 67.531 1.242 68.405 ;
     RECT  2.415 68.369 3.402 68.639 ;
     RECT  1.224 68.405 1.242 68.675 ;
     RECT  7.815 67.837 20.07 68.981 ;
     RECT  21.456 65.003 21.942 69.719 ;
     RECT  38.124 69.223 38.142 69.799 ;
     RECT  39.024 68.107 40.497 69.799 ;
     RECT  22.212 70.141 22.23 70.259 ;
     RECT  21.456 69.719 21.474 70.529 ;
     RECT  7.815 68.981 16.542 70.709 ;
     RECT  38.124 69.799 40.497 71.069 ;
     RECT  6.372 67.703 6.894 71.375 ;
     RECT  22.212 71.419 22.23 71.609 ;
     RECT  21.348 70.645 21.366 71.689 ;
     RECT  21.348 71.689 21.906 71.741 ;
     RECT  42.444 70.951 42.462 72.661 ;
     RECT  40.215 71.069 40.497 73.237 ;
     RECT  9.216 70.709 16.542 73.265 ;
     RECT  40.215 73.237 40.842 73.813 ;
     RECT  41.76 72.661 42.462 73.813 ;
     RECT  17.316 68.981 20.07 74.849 ;
     RECT  17.316 74.849 20.034 75.929 ;
     RECT  38.124 71.069 39.474 76.081 ;
     RECT  40.215 73.813 42.462 76.081 ;
     RECT  9.216 73.265 12.006 76.109 ;
     RECT  37.368 72.121 37.386 76.621 ;
     RECT  6.876 71.375 6.894 76.739 ;
     RECT  37.332 76.621 37.386 77.323 ;
     RECT  9.216 76.109 11.646 77.351 ;
     RECT  21.348 71.741 21.366 77.819 ;
     RECT  9.216 77.351 11.61 77.891 ;
     RECT  28.8 67.213 29.697 78.395 ;
     RECT  37.044 77.323 37.386 78.701 ;
     RECT  12.816 73.265 16.542 80.087 ;
     RECT  23.076 70.411 23.094 80.663 ;
     RECT  34.815 67.213 35.097 81.211 ;
     RECT  37.116 78.701 37.386 81.211 ;
     RECT  38.124 76.081 42.462 81.211 ;
     RECT  10.332 77.891 11.61 81.239 ;
     RECT  36.036 67.711 36.054 81.239 ;
     RECT  34.776 81.211 35.097 81.401 ;
     RECT  37.116 81.211 42.462 81.499 ;
     RECT  17.316 75.929 19.854 81.509 ;
     RECT  37.08 81.499 42.462 81.635 ;
     RECT  10.332 81.239 10.998 81.751 ;
     RECT  10.224 81.751 10.998 81.869 ;
     RECT  34.815 81.401 35.097 82.183 ;
     RECT  9.216 77.891 9.234 82.211 ;
     RECT  34.776 82.183 35.097 82.319 ;
     RECT  37.116 81.635 42.462 82.525 ;
     RECT  37.044 82.525 42.462 82.723 ;
     RECT  36.468 82.723 42.462 83.065 ;
     RECT  13.215 80.087 16.542 83.101 ;
     RECT  17.64 81.509 19.854 83.101 ;
     RECT  13.215 83.101 19.854 83.219 ;
     RECT  16.524 83.219 19.854 83.489 ;
     RECT  10.98 81.869 10.998 83.569 ;
     RECT  10.98 83.569 11.394 83.669 ;
     RECT  26.208 71.491 26.226 83.669 ;
     RECT  34.815 82.319 35.097 83.875 ;
     RECT  16.56 83.489 19.854 84.029 ;
     RECT  36.108 83.065 42.462 84.029 ;
     RECT  34.812 83.875 35.097 84.037 ;
     RECT  36.108 84.029 41.994 84.037 ;
     RECT  34.776 84.037 35.097 84.145 ;
     RECT  35.892 84.037 41.994 84.145 ;
     RECT  16.56 84.029 19.818 84.209 ;
     RECT  26.964 68.377 26.982 84.209 ;
     RECT  34.776 84.145 41.994 84.209 ;
     RECT  34.815 84.209 41.994 84.335 ;
     RECT  16.56 84.209 19.53 84.569 ;
     RECT  16.56 84.569 18.99 84.685 ;
     RECT  13.215 83.219 15.714 84.721 ;
     RECT  16.524 84.685 18.99 84.721 ;
     RECT  13.215 84.721 18.99 84.839 ;
     RECT  36 84.335 41.994 84.839 ;
     RECT  2.415 68.639 2.697 85.067 ;
     RECT  7.815 70.709 8.097 85.067 ;
     RECT  13.215 84.839 14.778 85.067 ;
     RECT  24.015 67.213 24.297 85.067 ;
     RECT  29.415 78.395 29.697 85.067 ;
     RECT  34.815 84.335 35.097 85.067 ;
     RECT  45.615 67.213 45.897 85.067 ;
     RECT  51.015 67.213 51.297 85.067 ;
     RECT  56.415 67.213 56.697 85.067 ;
     RECT  61.815 67.213 62.097 85.067 ;
     RECT  67.215 67.213 67.497 85.067 ;
     RECT  72.615 67.213 72.897 85.067 ;
     RECT  78.015 67.213 78.297 85.067 ;
     RECT  83.415 67.213 83.697 85.067 ;
     RECT  88.815 67.213 89.097 85.067 ;
     RECT  94.215 67.213 94.497 85.067 ;
     RECT  99.615 67.213 99.897 85.067 ;
     RECT  105.015 67.213 105.297 85.067 ;
     RECT  110.415 67.213 110.697 85.067 ;
     RECT  115.815 67.213 116.097 85.067 ;
     RECT  121.215 41.711 121.497 85.067 ;
     RECT  126.615 2.413 126.897 85.067 ;
     RECT  132.015 2.413 132.297 85.067 ;
     RECT  137.415 2.413 137.697 85.067 ;
     RECT  10.44 83.767 10.458 85.081 ;
     RECT  10.08 85.081 10.458 85.109 ;
     RECT  11.376 83.669 11.394 85.109 ;
     RECT  16.236 84.839 18.99 85.109 ;
     RECT  27.756 84.991 27.774 85.109 ;
     RECT  36.288 84.839 41.742 85.109 ;
     RECT  18.54 85.109 18.705 85.145 ;
     RECT  27.612 85.144 27.63 85.181 ;
     RECT  34.02 85.081 34.038 85.181 ;
     RECT  13.215 85.067 13.374 85.225 ;
     RECT  33.876 85.189 33.894 85.229 ;
     RECT  10.08 85.109 10.098 85.253 ;
     RECT  36.54 85.109 41.022 85.253 ;
     RECT  16.236 85.109 17.55 85.277 ;
     RECT  14.184 85.067 14.778 85.289 ;
     RECT  17.46 85.277 17.55 85.289 ;
     RECT  38.628 85.253 41.022 85.289 ;
     RECT  2.415 85.067 2.505 85.337 ;
     RECT  7.815 85.067 7.974 85.337 ;
     RECT  18.615 85.145 18.705 85.337 ;
     RECT  24.015 85.067 24.105 85.337 ;
     RECT  29.415 85.067 29.505 85.337 ;
     RECT  34.815 85.067 34.905 85.337 ;
     RECT  38.628 85.289 40.986 85.337 ;
     RECT  45.615 85.067 45.705 85.337 ;
     RECT  51.015 85.067 51.105 85.337 ;
     RECT  56.415 85.067 56.505 85.337 ;
     RECT  61.815 85.067 61.905 85.337 ;
     RECT  67.215 85.067 67.305 85.337 ;
     RECT  72.615 85.067 72.705 85.337 ;
     RECT  78.015 85.067 78.105 85.337 ;
     RECT  83.415 85.067 83.505 85.337 ;
     RECT  88.815 85.067 88.905 85.337 ;
     RECT  94.215 85.067 94.305 85.337 ;
     RECT  99.615 85.067 99.705 85.337 ;
     RECT  105.015 85.067 105.105 85.337 ;
     RECT  110.415 85.067 110.505 85.337 ;
     RECT  115.815 85.067 115.905 85.337 ;
     RECT  121.215 85.067 121.305 85.337 ;
     RECT  126.615 85.067 126.705 85.337 ;
     RECT  132.015 85.067 132.105 85.337 ;
     RECT  137.415 85.067 137.505 85.337 ;
     RECT  9.216 85.117 9.234 85.469 ;
     RECT  13.14 85.225 13.374 85.469 ;
     RECT  7.956 85.337 7.974 85.517 ;
     RECT  13.356 85.469 13.374 85.517 ;
     RECT  14.4 85.289 14.778 85.517 ;
     RECT  16.236 85.277 16.506 85.517 ;
     RECT  17.46 85.289 17.478 85.517 ;
     RECT  36.54 85.253 37.854 85.517 ;
     RECT  38.628 85.337 39.618 85.517 ;
     RECT  40.968 85.337 40.986 85.517 ;
     RECT  14.76 85.517 14.778 85.565 ;
     RECT  36.576 85.517 37.53 86.045 ;
     RECT  39.312 85.517 39.546 86.045 ;
     RECT  36.576 86.045 36.918 86.093 ;
     RECT  16.488 85.517 16.506 86.669 ;
     RECT  36.9 86.093 36.918 86.669 ;
     RECT  39.528 86.045 39.546 86.669 ;
    LAYER M4 ;
     RECT  0.06 13.872 0.169 67.56 ;
     RECT  0.169 13.872 1.433 67.608 ;
     RECT  1.433 13.872 2.408 48.264 ;
     RECT  1.433 49.248 2.408 67.608 ;
     RECT  2.408 2.148 2.512 85.332 ;
     RECT  2.512 2.418 2.704 85.062 ;
     RECT  2.704 13.92 2.765 21.48 ;
     RECT  2.704 64.176 2.801 66.504 ;
     RECT  2.704 67.584 2.801 67.608 ;
     RECT  2.704 23.568 2.837 48.264 ;
     RECT  2.704 49.248 2.837 62.76 ;
     RECT  2.801 64.32 2.837 66.504 ;
     RECT  2.837 64.32 3.269 65.448 ;
     RECT  2.765 13.92 3.449 20.904 ;
     RECT  2.837 66.48 3.449 66.504 ;
     RECT  2.837 23.568 3.557 46.584 ;
     RECT  3.557 24.432 3.593 46.584 ;
     RECT  3.593 24.432 3.629 45 ;
     RECT  3.593 45.984 3.737 46.584 ;
     RECT  3.629 24.624 3.881 45 ;
     RECT  3.449 14.4 3.917 20.904 ;
     RECT  3.917 14.496 4.133 20.904 ;
     RECT  3.881 24.624 4.169 24.936 ;
     RECT  4.133 14.88 4.313 20.904 ;
     RECT  2.837 49.584 4.381 62.76 ;
     RECT  3.269 64.32 4.381 64.344 ;
     RECT  4.169 24.912 4.385 24.936 ;
     RECT  4.381 49.584 4.417 64.344 ;
     RECT  3.269 65.424 4.417 65.448 ;
     RECT  3.881 25.968 4.457 45 ;
     RECT  4.417 49.584 4.457 65.736 ;
     RECT  3.737 46.56 4.525 46.584 ;
     RECT  2.837 47.712 4.525 47.736 ;
     RECT  4.525 46.56 4.7 47.736 ;
     RECT  4.7 46.56 4.741 47.784 ;
     RECT  4.457 50.208 4.889 65.736 ;
     RECT  4.457 26.64 5.033 45 ;
     RECT  4.957 21.696 5.065 21.72 ;
     RECT  4.741 46.56 5.137 48.168 ;
     RECT  4.313 14.88 5.141 20.376 ;
     RECT  5.141 15.12 5.177 20.376 ;
     RECT  5.137 46.32 5.177 48.168 ;
     RECT  5.033 26.64 5.357 28.872 ;
     RECT  5.177 15.456 5.681 20.376 ;
     RECT  5.357 26.64 5.681 28.824 ;
     RECT  5.681 15.456 5.753 18.12 ;
     RECT  5.033 29.856 5.753 45 ;
     RECT  5.641 23.664 5.857 23.688 ;
     RECT  5.681 19.2 5.965 20.376 ;
     RECT  5.065 21.696 5.965 22.056 ;
     RECT  5.965 19.2 6.145 22.056 ;
     RECT  5.857 23.568 6.145 23.688 ;
     RECT  5.177 46.32 6.253 46.344 ;
     RECT  5.177 47.328 6.253 48.168 ;
     RECT  5.753 18.096 6.257 18.12 ;
     RECT  6.145 19.2 6.325 23.688 ;
     RECT  6.253 46.32 6.325 48.408 ;
     RECT  5.753 15.456 6.365 17.064 ;
     RECT  5.681 26.64 6.397 26.76 ;
     RECT  5.753 30.72 6.545 45 ;
     RECT  6.365 16.512 6.617 17.064 ;
     RECT  6.545 30.72 6.793 44.952 ;
     RECT  5.681 27.888 6.829 28.824 ;
     RECT  6.793 29.856 6.829 44.952 ;
     RECT  4.889 50.304 6.829 65.736 ;
     RECT  5.965 67.152 6.829 67.176 ;
     RECT  6.829 27.888 6.833 44.952 ;
     RECT  6.365 15.456 6.901 15.48 ;
     RECT  6.829 50.304 7.045 67.176 ;
     RECT  6.325 46.32 7.189 48.456 ;
     RECT  6.721 25.296 7.225 25.32 ;
     RECT  6.397 26.304 7.225 26.76 ;
     RECT  6.937 18.192 7.297 18.216 ;
     RECT  6.325 19.2 7.477 24.312 ;
     RECT  7.225 25.296 7.477 26.76 ;
     RECT  7.477 19.2 7.513 26.76 ;
     RECT  6.833 27.888 7.513 27.912 ;
     RECT  6.833 28.944 7.669 44.952 ;
     RECT  7.189 46.32 7.669 49.32 ;
     RECT  6.901 14.736 7.808 15.48 ;
     RECT  6.617 16.512 7.808 16.92 ;
     RECT  7.297 18.144 7.808 18.216 ;
     RECT  7.513 19.2 7.808 27.912 ;
     RECT  7.669 28.944 7.808 49.32 ;
     RECT  7.045 50.304 7.808 67.32 ;
     RECT  5.893 85.488 7.808 85.512 ;
     RECT  7.808 2.148 7.912 85.512 ;
     RECT  7.912 2.418 7.985 85.512 ;
     RECT  7.985 2.418 8.104 85.464 ;
     RECT  8.104 14.832 8.165 65.736 ;
     RECT  8.165 24.48 8.381 65.736 ;
     RECT  8.165 14.832 8.561 23.064 ;
     RECT  8.381 25.104 8.633 65.736 ;
     RECT  8.633 25.104 8.675 50.856 ;
     RECT  8.561 14.832 8.705 17.688 ;
     RECT  8.675 27.888 8.849 50.856 ;
     RECT  8.705 14.832 8.957 17.64 ;
     RECT  8.104 85.44 9.245 85.464 ;
     RECT  8.957 14.832 9.269 17.352 ;
     RECT  8.633 51.936 9.353 65.736 ;
     RECT  8.675 25.104 9.673 26.664 ;
     RECT  8.849 27.888 9.673 48.792 ;
     RECT  9.353 51.936 9.683 65.592 ;
     RECT  9.269 14.736 9.785 17.352 ;
     RECT  9.673 25.104 9.889 48.792 ;
     RECT  9.785 14.736 9.925 15.144 ;
     RECT  9.889 24.144 9.932 48.792 ;
     RECT  8.849 49.776 9.932 50.856 ;
     RECT  8.561 18.672 10.001 23.064 ;
     RECT  8.104 67.248 10.001 67.32 ;
     RECT  9.683 51.936 10.069 65.16 ;
     RECT  9.932 24.144 10.141 50.856 ;
     RECT  10.069 51.888 10.141 65.16 ;
     RECT  10.001 18.672 10.165 22.248 ;
     RECT  9.785 16.416 10.213 17.352 ;
     RECT  10.165 18.576 10.213 22.248 ;
     RECT  10.141 24.144 10.217 65.16 ;
     RECT  10.217 26.496 10.325 65.16 ;
     RECT  9.925 14.208 10.361 15.144 ;
     RECT  10.213 16.416 10.577 22.248 ;
     RECT  10.217 24.144 10.577 25.464 ;
     RECT  10.577 17.328 10.613 22.248 ;
     RECT  10.325 26.496 10.613 27.144 ;
     RECT  10.325 28.752 10.825 65.16 ;
     RECT  10.001 67.248 10.825 67.272 ;
     RECT  10.361 15.12 10.829 15.144 ;
     RECT  10.613 17.328 11.009 22.2 ;
     RECT  11.009 17.616 11.081 22.2 ;
     RECT  10.825 28.752 11.297 65.256 ;
     RECT  10.825 66.384 11.405 67.272 ;
     RECT  10.577 25.44 11.509 25.464 ;
     RECT  10.613 26.496 11.509 26.664 ;
     RECT  11.297 28.752 11.725 50.424 ;
     RECT  11.297 51.936 11.873 65.256 ;
     RECT  11.725 16.608 11.909 16.632 ;
     RECT  10.933 15.36 11.941 15.384 ;
     RECT  11.941 14.784 11.987 15.384 ;
     RECT  11.509 25.44 12.049 26.664 ;
     RECT  12.049 25.44 12.161 26.808 ;
     RECT  11.081 22.176 12.193 22.2 ;
     RECT  11.869 23.376 12.193 23.4 ;
     RECT  11.725 28.224 12.409 50.424 ;
     RECT  11.873 51.936 12.409 56.232 ;
     RECT  11.081 17.616 12.553 21.048 ;
     RECT  12.193 22.176 12.553 23.4 ;
     RECT  12.161 25.44 12.661 26.76 ;
     RECT  12.553 17.616 13.093 23.4 ;
     RECT  12.661 25.152 13.093 26.76 ;
     RECT  13.093 24.48 13.129 26.76 ;
     RECT  12.409 28.224 13.129 56.232 ;
     RECT  11.987 14.784 13.208 14.808 ;
     RECT  13.093 17.088 13.208 23.4 ;
     RECT  13.129 24.48 13.208 56.232 ;
     RECT  11.873 57.264 13.208 65.256 ;
     RECT  11.405 66.432 13.208 67.272 ;
     RECT  11.509 75.408 13.208 75.432 ;
     RECT  13.129 85.44 13.208 85.464 ;
     RECT  13.208 2.148 13.312 85.464 ;
     RECT  13.312 2.418 13.345 85.464 ;
     RECT  13.345 2.418 13.504 85.512 ;
     RECT  13.504 52.992 13.637 54.744 ;
     RECT  13.504 58.512 13.709 67.032 ;
     RECT  13.504 57.408 13.817 57.432 ;
     RECT  13.504 25.296 13.925 51.96 ;
     RECT  13.637 54.384 13.925 54.744 ;
     RECT  13.504 83.76 13.957 85.512 ;
     RECT  13.504 18.48 13.997 23.304 ;
     RECT  13.925 54.384 13.997 54.456 ;
     RECT  13.709 66.048 13.997 67.032 ;
     RECT  13.957 83.76 14.033 85.56 ;
     RECT  13.709 58.512 14.069 64.968 ;
     RECT  14.069 64.32 14.177 64.968 ;
     RECT  14.033 85.248 14.249 85.56 ;
     RECT  14.249 85.488 14.429 85.56 ;
     RECT  13.925 51.264 14.483 51.96 ;
     RECT  14.033 83.76 14.497 83.784 ;
     RECT  13.997 54.384 14.501 54.408 ;
     RECT  13.997 18.48 14.609 23.112 ;
     RECT  14.497 83.52 14.681 83.784 ;
     RECT  13.925 25.296 14.753 50.04 ;
     RECT  14.429 85.536 14.789 85.56 ;
     RECT  14.069 58.512 14.821 63.24 ;
     RECT  14.821 57.888 14.933 63.24 ;
     RECT  14.753 42.336 15.077 50.04 ;
     RECT  14.753 25.296 15.217 41.256 ;
     RECT  14.681 83.52 15.349 83.544 ;
     RECT  15.349 82.8 15.436 83.544 ;
     RECT  15.637 84.576 15.725 84.6 ;
     RECT  14.933 58.32 15.793 63.24 ;
     RECT  15.793 58.32 15.833 63.816 ;
     RECT  13.997 67.008 16.009 67.032 ;
     RECT  15.833 62.016 16.013 63.816 ;
     RECT  15.833 58.32 16.049 60.792 ;
     RECT  16.049 58.32 16.121 60.648 ;
     RECT  13.637 52.992 16.405 53.016 ;
     RECT  16.121 58.32 16.477 60.36 ;
     RECT  16.405 52.992 16.481 53.496 ;
     RECT  15.436 83.52 16.585 83.544 ;
     RECT  16.013 62.016 16.589 63.24 ;
     RECT  16.585 83.52 16.589 83.784 ;
     RECT  16.477 86.64 16.595 86.664 ;
     RECT  15.217 24.912 16.765 41.256 ;
     RECT  15.077 42.432 16.765 50.04 ;
     RECT  16.765 24.912 16.837 50.04 ;
     RECT  16.589 62.016 16.837 62.184 ;
     RECT  16.225 84.96 16.924 85.512 ;
     RECT  16.924 85.248 17.093 85.512 ;
     RECT  16.589 63.168 17.123 63.24 ;
     RECT  16.481 53.472 17.165 53.496 ;
     RECT  16.837 61.824 17.413 62.184 ;
     RECT  16.477 58.128 17.489 60.36 ;
     RECT  17.093 85.488 17.489 85.512 ;
     RECT  17.123 63.216 17.593 63.24 ;
     RECT  16.837 24.912 17.989 50.376 ;
     RECT  17.413 61.632 18.097 62.184 ;
     RECT  17.593 63.216 18.097 63.864 ;
     RECT  18.061 54.624 18.169 54.648 ;
     RECT  16.589 83.76 18.241 83.784 ;
     RECT  14.609 18.48 18.277 22.872 ;
     RECT  18.169 54.096 18.421 54.648 ;
     RECT  17.489 58.128 18.457 59.832 ;
     RECT  18.457 57.408 18.529 59.832 ;
     RECT  18.277 18.48 18.608 23.304 ;
     RECT  17.989 24.72 18.608 50.376 ;
     RECT  14.483 51.936 18.608 51.96 ;
     RECT  18.421 54.096 18.608 55.8 ;
     RECT  18.529 56.784 18.608 59.832 ;
     RECT  18.097 61.632 18.608 64.68 ;
     RECT  16.009 67.008 18.608 67.368 ;
     RECT  18.421 71.424 18.608 71.448 ;
     RECT  13.504 75.408 18.608 75.432 ;
     RECT  18.241 83.76 18.608 84.36 ;
     RECT  18.608 2.148 18.712 85.332 ;
     RECT  18.712 2.418 18.904 85.062 ;
     RECT  18.904 24.72 19.037 60.552 ;
     RECT  19.037 51.168 19.433 60.552 ;
     RECT  19.433 60.048 19.933 60.552 ;
     RECT  18.904 61.632 19.933 63.624 ;
     RECT  19.037 24.72 19.957 50.184 ;
     RECT  19.957 24.528 20.041 50.184 ;
     RECT  19.433 51.168 20.041 58.824 ;
     RECT  20.041 24.528 20.473 58.824 ;
     RECT  19.933 60.048 20.473 63.624 ;
     RECT  20.473 24.528 20.513 63.624 ;
     RECT  20.513 24.624 20.725 63.624 ;
     RECT  18.904 71.424 21.836 71.448 ;
     RECT  21.836 71.424 21.923 71.736 ;
     RECT  21.637 87.36 21.923 87.384 ;
     RECT  20.725 24.624 22.165 63.816 ;
     RECT  21.923 71.424 22.241 71.448 ;
     RECT  18.904 18.48 22.536 23.304 ;
     RECT  22.165 24.528 22.536 63.816 ;
     RECT  22.536 18.48 24.008 64.824 ;
     RECT  18.904 67.008 24.008 67.368 ;
     RECT  18.904 75.408 24.008 75.432 ;
     RECT  18.904 83.76 24.008 83.784 ;
     RECT  24.008 2.148 24.112 64.824 ;
     RECT  24.008 66.948 24.112 85.332 ;
     RECT  24.112 2.418 24.304 64.824 ;
     RECT  24.112 67.008 24.304 85.062 ;
     RECT  24.304 18.48 29.408 64.824 ;
     RECT  24.304 67.008 29.408 67.368 ;
     RECT  24.304 75.408 29.408 75.432 ;
     RECT  24.304 83.76 29.408 83.784 ;
     RECT  27.601 85.152 29.408 85.176 ;
     RECT  29.408 2.148 29.512 64.824 ;
     RECT  29.408 66.948 29.512 85.332 ;
     RECT  29.512 2.418 29.704 64.824 ;
     RECT  29.512 67.218 29.704 85.176 ;
     RECT  29.704 85.152 33.865 85.176 ;
     RECT  29.704 18.48 34.808 64.824 ;
     RECT  29.704 67.344 34.808 67.368 ;
     RECT  29.704 75.408 34.808 75.432 ;
     RECT  29.704 83.76 34.808 83.784 ;
     RECT  33.865 85.152 34.808 85.224 ;
     RECT  34.808 2.148 34.912 64.824 ;
     RECT  34.808 66.948 34.912 85.332 ;
     RECT  34.912 2.418 35.104 64.824 ;
     RECT  34.912 67.218 35.104 85.224 ;
     RECT  35.104 85.2 36.529 85.224 ;
     RECT  36.529 85.2 36.565 85.512 ;
     RECT  36.565 85.2 36.889 86.088 ;
     RECT  36.889 85.2 37.331 86.664 ;
     RECT  37.331 85.2 37.381 86.04 ;
     RECT  37.069 81.504 37.645 81.528 ;
     RECT  37.381 84.96 37.715 86.04 ;
     RECT  35.104 83.76 37.765 83.784 ;
     RECT  37.715 84.96 37.765 85.512 ;
     RECT  37.765 84.912 37.861 85.512 ;
     RECT  37.765 83.76 37.907 83.832 ;
     RECT  37.645 81.456 37.964 81.528 ;
     RECT  37.907 83.808 37.969 83.832 ;
     RECT  37.861 84.816 37.969 85.512 ;
     RECT  35.104 67.344 38.051 67.368 ;
     RECT  37.964 81.264 38.051 81.528 ;
     RECT  37.969 83.808 38.725 85.512 ;
     RECT  38.473 82.08 39.053 82.104 ;
     RECT  38.725 83.808 39.341 86.04 ;
     RECT  39.517 86.64 39.923 86.664 ;
     RECT  35.104 18.48 40.208 64.824 ;
     RECT  35.104 75.408 40.208 75.432 ;
     RECT  39.341 83.808 40.208 85.512 ;
     RECT  40.208 2.148 40.312 64.824 ;
     RECT  40.208 66.948 40.312 85.512 ;
     RECT  40.312 2.418 40.504 64.824 ;
     RECT  40.312 67.218 40.504 85.512 ;
     RECT  40.504 84.192 40.997 85.512 ;
     RECT  40.997 84.192 41.555 84.936 ;
     RECT  41.555 84.72 41.681 84.936 ;
     RECT  41.681 84.72 42.005 84.744 ;
     RECT  40.504 18.48 45.608 64.824 ;
     RECT  45.608 2.148 45.712 64.824 ;
     RECT  45.608 66.948 45.712 85.332 ;
     RECT  45.712 2.418 45.904 64.824 ;
     RECT  45.712 67.218 45.904 85.062 ;
     RECT  45.904 18.48 51.008 64.824 ;
     RECT  51.008 2.148 51.112 64.824 ;
     RECT  51.008 66.948 51.112 85.332 ;
     RECT  51.112 2.418 51.304 64.824 ;
     RECT  51.112 67.218 51.304 85.062 ;
     RECT  51.304 18.48 56.408 64.824 ;
     RECT  56.408 2.148 56.512 64.824 ;
     RECT  56.408 66.948 56.512 85.332 ;
     RECT  56.512 2.418 56.704 64.824 ;
     RECT  56.512 67.218 56.704 85.062 ;
     RECT  56.704 18.48 61.808 64.824 ;
     RECT  61.808 2.148 61.912 64.824 ;
     RECT  61.808 66.948 61.912 85.332 ;
     RECT  61.912 2.418 62.104 64.824 ;
     RECT  61.912 67.218 62.104 85.062 ;
     RECT  62.104 18.48 67.208 64.824 ;
     RECT  67.208 2.148 67.312 64.824 ;
     RECT  67.208 66.948 67.312 85.332 ;
     RECT  67.312 2.418 67.504 64.824 ;
     RECT  67.312 67.218 67.504 85.062 ;
     RECT  67.504 18.48 72.608 64.824 ;
     RECT  72.608 2.148 72.712 64.824 ;
     RECT  72.608 66.948 72.712 85.332 ;
     RECT  72.712 2.418 72.904 64.824 ;
     RECT  72.712 67.218 72.904 85.062 ;
     RECT  72.904 18.48 78.008 64.824 ;
     RECT  78.008 2.148 78.112 64.824 ;
     RECT  78.008 66.948 78.112 85.332 ;
     RECT  78.112 2.418 78.304 64.824 ;
     RECT  78.112 67.218 78.304 85.062 ;
     RECT  78.304 18.48 83.408 64.824 ;
     RECT  83.408 2.148 83.512 64.824 ;
     RECT  83.408 66.948 83.512 85.332 ;
     RECT  83.512 2.418 83.704 64.824 ;
     RECT  83.512 67.218 83.704 85.062 ;
     RECT  83.704 18.48 88.808 64.824 ;
     RECT  88.808 2.148 88.912 64.824 ;
     RECT  88.808 66.948 88.912 85.332 ;
     RECT  88.912 2.418 89.104 64.824 ;
     RECT  88.912 67.218 89.104 85.062 ;
     RECT  89.104 18.48 94.208 64.824 ;
     RECT  94.208 2.148 94.312 64.824 ;
     RECT  94.208 66.948 94.312 85.332 ;
     RECT  94.312 2.418 94.504 64.824 ;
     RECT  94.312 67.218 94.504 85.062 ;
     RECT  94.504 18.48 99.608 64.824 ;
     RECT  99.608 2.148 99.712 64.824 ;
     RECT  99.608 66.948 99.712 85.332 ;
     RECT  99.712 2.418 99.904 64.824 ;
     RECT  99.712 67.218 99.904 85.062 ;
     RECT  99.904 18.48 105.008 64.824 ;
     RECT  105.008 2.148 105.112 64.824 ;
     RECT  105.008 66.948 105.112 85.332 ;
     RECT  105.112 2.418 105.304 64.824 ;
     RECT  105.112 67.218 105.304 85.062 ;
     RECT  105.304 18.48 110.408 64.824 ;
     RECT  110.408 2.148 110.512 64.824 ;
     RECT  110.408 66.948 110.512 85.332 ;
     RECT  110.512 2.418 110.704 64.824 ;
     RECT  110.512 67.218 110.704 85.062 ;
     RECT  110.704 18.48 115.808 64.824 ;
     RECT  115.808 2.148 115.912 64.824 ;
     RECT  115.808 66.948 115.912 85.332 ;
     RECT  115.912 2.418 116.104 64.824 ;
     RECT  115.912 67.218 116.104 85.062 ;
     RECT  116.104 18.48 117.216 64.824 ;
     RECT  117.216 18.48 117.389 63.72 ;
     RECT  117.389 18.48 117.395 63.624 ;
     RECT  117.395 24.528 117.425 63.624 ;
     RECT  117.425 41.616 117.461 61.032 ;
     RECT  117.425 62.064 117.461 63.624 ;
     RECT  117.395 18.48 118.573 23.304 ;
     RECT  117.425 24.528 118.573 40.536 ;
     RECT  117.461 41.616 118.609 41.64 ;
     RECT  117.461 42.768 118.609 45.672 ;
     RECT  117.461 46.704 118.613 51.336 ;
     RECT  118.609 41.616 118.721 45.672 ;
     RECT  117.461 53.04 118.721 61.032 ;
     RECT  118.573 18.48 118.835 40.536 ;
     RECT  118.721 53.04 119.081 54.696 ;
     RECT  118.835 18.768 119.117 40.536 ;
     RECT  118.721 41.616 119.117 44.52 ;
     RECT  118.721 45.648 119.117 45.672 ;
     RECT  118.613 47.952 119.117 49.128 ;
     RECT  118.613 50.16 119.117 51.336 ;
     RECT  119.081 53.04 119.117 53.064 ;
     RECT  118.721 55.92 119.117 61.032 ;
     RECT  119.117 18.768 119.123 37.656 ;
     RECT  119.117 38.784 119.293 40.536 ;
     RECT  119.117 41.616 119.293 43.752 ;
     RECT  119.117 56.4 119.297 57 ;
     RECT  119.123 18.768 119.315 23.256 ;
     RECT  119.293 38.784 119.333 43.752 ;
     RECT  119.333 38.784 119.405 42.888 ;
     RECT  117.461 62.064 119.405 63.336 ;
     RECT  119.315 18.768 119.411 23.208 ;
     RECT  119.123 24.528 119.513 37.656 ;
     RECT  119.405 38.784 119.513 39.432 ;
     RECT  119.405 40.512 119.513 42.888 ;
     RECT  119.405 62.736 119.549 63.336 ;
     RECT  119.411 18.768 119.555 23.16 ;
     RECT  119.117 58.704 119.585 58.728 ;
     RECT  119.513 25.872 119.621 37.656 ;
     RECT  119.513 38.832 119.621 39.432 ;
     RECT  119.555 19.344 119.657 23.16 ;
     RECT  119.621 25.872 119.657 30.024 ;
     RECT  119.621 31.056 119.657 37.656 ;
     RECT  119.621 39.36 119.657 39.432 ;
     RECT  119.513 40.8 119.657 42.888 ;
     RECT  118.613 46.704 119.657 46.728 ;
     RECT  119.081 54.096 119.657 54.696 ;
     RECT  119.297 56.4 119.657 56.424 ;
     RECT  119.117 60.912 119.657 60.936 ;
     RECT  119.657 25.872 119.693 28.776 ;
     RECT  119.657 30 119.693 30.024 ;
     RECT  119.693 25.872 119.729 28.392 ;
     RECT  119.657 40.8 119.729 42.6 ;
     RECT  119.729 25.872 119.765 28.008 ;
     RECT  119.549 62.736 119.765 62.856 ;
     RECT  119.657 19.344 119.795 22.776 ;
     RECT  119.765 26.64 119.873 28.008 ;
     RECT  119.657 31.344 119.873 37.224 ;
     RECT  119.795 19.344 119.891 20.328 ;
     RECT  119.873 31.344 119.891 31.56 ;
     RECT  119.873 26.784 119.909 27.912 ;
     RECT  119.873 33.072 119.909 37.224 ;
     RECT  119.729 41.616 119.909 42.6 ;
     RECT  119.765 62.832 119.909 62.856 ;
     RECT  119.909 41.616 119.939 41.64 ;
     RECT  119.891 31.536 119.945 31.56 ;
     RECT  119.909 34.704 119.981 37.224 ;
     RECT  119.909 26.784 120.025 26.808 ;
     RECT  119.909 27.792 120.053 27.912 ;
     RECT  119.981 34.704 120.053 35.352 ;
     RECT  120.053 27.792 120.089 27.816 ;
     RECT  119.981 36.336 120.089 37.224 ;
     RECT  120.089 36.576 120.125 37.032 ;
     RECT  120.125 36.576 120.161 36.84 ;
     RECT  119.891 19.344 121.208 19.656 ;
     RECT  119.795 21.504 121.208 22.776 ;
     RECT  119.909 33.072 121.208 33.096 ;
     RECT  120.053 35.328 121.208 35.352 ;
     RECT  120.161 36.576 121.208 36.744 ;
     RECT  119.657 39.408 121.208 39.432 ;
     RECT  119.657 54.096 121.208 54.12 ;
     RECT  121.208 2.148 121.312 85.332 ;
     RECT  121.312 2.418 121.504 85.062 ;
     RECT  126.608 2.148 126.712 85.332 ;
     RECT  126.712 2.418 126.904 85.062 ;
     RECT  132.008 2.148 132.112 85.332 ;
     RECT  132.112 2.418 132.304 85.062 ;
     RECT  137.408 2.148 137.512 85.332 ;
     RECT  137.512 2.418 137.704 85.062 ;
    LAYER M5 ;
     RECT  2.4 2.137 2.52 2.151 ;
     RECT  7.8 2.137 7.92 2.151 ;
     RECT  13.2 2.137 13.32 2.151 ;
     RECT  18.6 2.137 18.72 2.151 ;
     RECT  24 2.137 24.12 2.151 ;
     RECT  29.4 2.137 29.52 2.151 ;
     RECT  34.8 2.137 34.92 2.151 ;
     RECT  40.2 2.137 40.32 2.151 ;
     RECT  45.6 2.137 45.72 2.151 ;
     RECT  51 2.137 51.12 2.151 ;
     RECT  56.4 2.137 56.52 2.151 ;
     RECT  61.8 2.137 61.92 2.151 ;
     RECT  67.2 2.137 67.32 2.151 ;
     RECT  72.6 2.137 72.72 2.151 ;
     RECT  78 2.137 78.12 2.151 ;
     RECT  83.4 2.137 83.52 2.151 ;
     RECT  88.8 2.137 88.92 2.151 ;
     RECT  94.2 2.137 94.32 2.151 ;
     RECT  99.6 2.137 99.72 2.151 ;
     RECT  105 2.137 105.12 2.151 ;
     RECT  110.4 2.137 110.52 2.151 ;
     RECT  115.8 2.137 115.92 2.151 ;
     RECT  121.2 2.137 121.32 2.151 ;
     RECT  126.6 2.137 126.72 2.151 ;
     RECT  132 2.137 132.12 2.151 ;
     RECT  137.4 2.137 137.52 2.151 ;
     RECT  2.4 2.151 2.712 14.389 ;
     RECT  2.4 14.389 3 14.531 ;
     RECT  9.936 14.197 9.96 14.725 ;
     RECT  9.312 14.725 9.96 14.867 ;
     RECT  9.936 14.867 9.96 14.915 ;
     RECT  11.952 14.773 11.976 15.395 ;
     RECT  13.2 2.151 13.512 17.077 ;
     RECT  7.8 2.151 8.112 17.605 ;
     RECT  2.4 14.531 2.712 17.941 ;
     RECT  2.4 17.941 2.808 18.083 ;
     RECT  0.144 17.269 0.168 18.227 ;
     RECT  13.104 17.077 13.512 18.275 ;
     RECT  117.648 18.661 117.672 18.709 ;
     RECT  118.8 18.469 118.824 18.757 ;
     RECT  117.648 18.709 117.768 19.237 ;
     RECT  118.8 18.757 119.544 19.237 ;
     RECT  13.2 18.275 13.512 19.333 ;
     RECT  117.648 19.237 119.544 19.333 ;
     RECT  121.2 2.151 121.512 19.333 ;
     RECT  21.552 19.525 21.576 19.573 ;
     RECT  7.8 17.605 8.808 19.669 ;
     RECT  7.104 19.669 8.808 20.195 ;
     RECT  11.184 19.909 11.208 20.197 ;
     RECT  12.288 19.333 13.512 20.197 ;
     RECT  7.104 20.195 8.112 20.579 ;
     RECT  21.552 19.573 22.056 20.821 ;
     RECT  24 2.151 24.312 21.109 ;
     RECT  20.208 20.677 20.232 21.205 ;
     RECT  21.456 20.821 22.056 21.589 ;
     RECT  23.904 21.109 24.312 21.683 ;
     RECT  117.648 19.333 121.512 21.685 ;
     RECT  7.68 20.579 8.112 22.213 ;
     RECT  20.208 21.205 20.328 22.501 ;
     RECT  21.36 21.589 22.056 22.501 ;
     RECT  20.208 22.501 22.056 22.789 ;
     RECT  7.68 22.213 8.904 23.075 ;
     RECT  14.496 22.837 14.52 23.075 ;
     RECT  117.408 21.685 121.512 23.653 ;
     RECT  20.208 22.789 22.2 24.517 ;
     RECT  19.968 24.517 22.2 24.563 ;
     RECT  117.36 23.653 121.512 25.139 ;
     RECT  7.68 23.075 8.112 25.475 ;
     RECT  19.968 24.563 22.056 25.859 ;
     RECT  7.8 25.475 8.112 26.293 ;
     RECT  7.8 26.293 8.664 26.725 ;
     RECT  0.144 26.869 0.168 27.155 ;
     RECT  6.816 26.725 8.664 27.203 ;
     RECT  6.816 27.203 8.568 27.923 ;
     RECT  11.184 20.197 13.512 28.453 ;
     RECT  0.192 28.501 0.216 28.787 ;
     RECT  11.184 28.453 14.088 30.275 ;
     RECT  10.176 18.565 10.2 30.325 ;
     RECT  10.128 30.325 10.2 30.659 ;
     RECT  10.176 30.659 10.2 30.661 ;
     RECT  11.184 30.275 13.512 30.661 ;
     RECT  117.648 25.139 121.512 30.757 ;
     RECT  117.36 30.757 121.512 31.043 ;
     RECT  10.176 30.661 13.512 31.139 ;
     RECT  5.856 30.709 5.88 31.235 ;
     RECT  7.8 27.923 8.568 31.235 ;
     RECT  117.648 31.043 121.512 31.379 ;
     RECT  0.192 31.189 0.216 31.427 ;
     RECT  2.4 18.083 2.712 31.669 ;
     RECT  2.304 31.669 2.712 31.859 ;
     RECT  117.696 31.379 121.512 32.291 ;
     RECT  7.8 31.235 8.112 32.293 ;
     RECT  10.176 31.139 10.2 32.437 ;
     RECT  11.184 31.139 13.512 32.437 ;
     RECT  10.176 32.437 13.608 33.157 ;
     RECT  10.176 33.157 13.656 33.251 ;
     RECT  117.792 32.291 121.512 33.395 ;
     RECT  117.84 33.395 121.512 33.731 ;
     RECT  117.936 33.731 121.512 33.923 ;
     RECT  2.4 31.859 2.712 34.261 ;
     RECT  11.184 33.251 13.656 34.355 ;
     RECT  2.4 34.261 2.904 34.451 ;
     RECT  10.176 33.251 10.2 34.501 ;
     RECT  11.184 34.355 13.512 34.501 ;
     RECT  7.68 32.293 8.112 34.787 ;
     RECT  10.176 34.501 13.512 34.787 ;
     RECT  10.176 34.787 10.2 34.837 ;
     RECT  19.968 25.859 22.008 34.883 ;
     RECT  10.032 34.837 10.2 35.027 ;
     RECT  3.792 34.693 3.816 35.555 ;
     RECT  2.4 34.451 2.712 35.893 ;
     RECT  20.112 34.883 22.008 36.229 ;
     RECT  2.4 35.893 2.952 36.371 ;
     RECT  20.112 36.229 22.344 36.419 ;
     RECT  11.184 34.787 13.512 36.661 ;
     RECT  0.144 37.381 0.168 37.571 ;
     RECT  10.176 35.027 10.2 37.573 ;
     RECT  18.6 2.151 18.912 37.621 ;
     RECT  20.112 36.419 22.008 37.621 ;
     RECT  118.224 33.923 121.512 37.667 ;
     RECT  18.6 37.621 22.008 38.051 ;
     RECT  11.184 36.661 14.424 38.147 ;
     RECT  2.4 36.371 2.712 38.389 ;
     RECT  9.888 37.573 10.2 38.675 ;
     RECT  2.4 38.389 2.904 39.059 ;
     RECT  118.224 37.667 118.344 39.395 ;
     RECT  119.904 37.667 121.512 39.443 ;
     RECT  14.784 39.013 14.808 39.493 ;
     RECT  20.112 38.051 22.008 39.589 ;
     RECT  14.784 39.493 15 39.635 ;
     RECT  20.112 39.589 22.344 39.637 ;
     RECT  14.784 39.635 14.856 39.827 ;
     RECT  20.064 39.637 22.344 39.827 ;
     RECT  20.064 39.827 20.232 39.875 ;
     RECT  21.36 39.827 22.344 39.875 ;
     RECT  18.6 38.051 18.912 39.877 ;
     RECT  14.784 39.827 14.808 40.355 ;
     RECT  21.36 39.875 21.912 40.547 ;
     RECT  118.32 39.395 118.344 40.547 ;
     RECT  2.4 39.059 2.712 40.549 ;
     RECT  20.064 39.875 20.136 40.739 ;
     RECT  2.4 40.549 2.904 40.883 ;
     RECT  7.8 34.787 8.112 40.981 ;
     RECT  0.144 40.837 0.168 41.027 ;
     RECT  4.56 40.933 4.584 41.075 ;
     RECT  20.112 40.739 20.136 41.171 ;
     RECT  10.176 38.675 10.2 41.557 ;
     RECT  11.184 38.147 13.512 41.557 ;
     RECT  7.8 40.981 8.568 41.651 ;
     RECT  119.904 39.443 119.928 41.651 ;
     RECT  3.888 41.509 3.912 41.747 ;
     RECT  3.792 42.037 3.816 42.227 ;
     RECT  21.36 40.547 21.384 42.467 ;
     RECT  7.8 41.651 8.52 42.709 ;
     RECT  10.176 41.557 13.512 42.709 ;
     RECT  7.8 42.709 13.512 43.379 ;
     RECT  7.8 43.379 9.384 43.955 ;
     RECT  11.088 43.379 13.512 44.197 ;
     RECT  11.088 44.197 13.848 44.627 ;
     RECT  7.8 43.955 8.112 45.445 ;
     RECT  9.36 43.955 9.384 45.491 ;
     RECT  11.52 44.627 13.848 45.587 ;
     RECT  11.52 45.587 13.512 46.211 ;
     RECT  0.144 47.077 0.168 47.267 ;
     RECT  7.68 45.445 8.112 47.269 ;
     RECT  0.528 47.701 0.552 47.939 ;
     RECT  10.224 46.645 10.248 48.131 ;
     RECT  4.752 47.749 4.776 48.179 ;
     RECT  7.296 47.269 8.112 49.091 ;
     RECT  21.072 49.093 21.096 49.235 ;
     RECT  14.928 49.765 14.952 49.907 ;
     RECT  9.984 49.477 10.008 50.051 ;
     RECT  20.256 49.429 20.28 50.195 ;
     RECT  7.8 49.091 8.112 50.389 ;
     RECT  12.96 46.211 13.512 50.389 ;
     RECT  0.144 50.341 0.168 50.627 ;
     RECT  4.464 50.869 4.488 51.107 ;
     RECT  12.528 50.389 13.512 51.253 ;
     RECT  12.528 51.253 14.472 51.347 ;
     RECT  0.144 51.973 0.168 52.163 ;
     RECT  2.4 40.883 2.712 52.261 ;
     RECT  1.824 52.261 2.712 52.403 ;
     RECT  11.52 46.211 11.544 52.405 ;
     RECT  12.96 51.347 14.472 52.981 ;
     RECT  7.8 50.389 8.232 53.027 ;
     RECT  12.96 52.981 14.568 53.027 ;
     RECT  10.848 52.405 11.544 53.125 ;
     RECT  10.848 53.125 11.736 53.365 ;
     RECT  10.8 53.365 11.736 53.891 ;
     RECT  10.8 53.891 11.544 54.179 ;
     RECT  7.8 53.027 8.112 54.421 ;
     RECT  0.144 53.557 0.168 54.707 ;
     RECT  6.816 54.421 8.112 55.907 ;
     RECT  10.032 55.189 10.056 57.011 ;
     RECT  7.584 55.907 8.112 57.061 ;
     RECT  7.392 57.061 8.112 57.109 ;
     RECT  0.24 57.349 0.264 57.539 ;
     RECT  6.816 57.109 8.112 57.635 ;
     RECT  4.464 57.541 4.488 57.875 ;
     RECT  18.432 39.877 18.912 57.877 ;
     RECT  7.392 57.635 8.112 58.021 ;
     RECT  5.664 57.541 5.688 58.163 ;
     RECT  7.392 58.021 8.52 58.163 ;
     RECT  7.44 58.163 8.52 58.259 ;
     RECT  14.544 53.027 14.568 58.643 ;
     RECT  9.696 57.973 9.72 58.739 ;
     RECT  18.432 57.877 19.8 58.835 ;
     RECT  7.44 58.259 8.112 59.843 ;
     RECT  3.792 60.277 3.816 60.659 ;
     RECT  7.8 59.843 8.112 61.189 ;
     RECT  5.664 60.949 5.688 61.333 ;
     RECT  5.664 61.333 6.648 61.619 ;
     RECT  18.432 58.835 18.912 61.621 ;
     RECT  7.68 61.189 8.112 61.669 ;
     RECT  9.648 60.949 9.672 61.669 ;
     RECT  16.848 38.149 16.872 61.859 ;
     RECT  12.96 53.027 13.512 62.005 ;
     RECT  12.528 62.005 13.512 62.053 ;
     RECT  6.624 61.619 6.648 62.195 ;
     RECT  7.68 61.669 9.672 62.195 ;
     RECT  17.088 62.101 17.112 63.157 ;
     RECT  16.848 63.157 17.112 63.203 ;
     RECT  7.8 62.195 9.672 63.299 ;
     RECT  12.528 62.053 13.992 63.539 ;
     RECT  18.432 61.621 19.416 63.635 ;
     RECT  12.96 63.539 13.992 64.019 ;
     RECT  7.8 63.299 8.76 64.261 ;
     RECT  11.52 54.179 11.544 64.357 ;
     RECT  7.8 64.261 9.144 65.125 ;
     RECT  11.088 64.357 11.544 65.171 ;
     RECT  7.8 65.125 9.672 65.603 ;
     RECT  12.96 64.019 13.512 66.085 ;
     RECT  12.96 66.085 13.608 66.803 ;
     RECT  12.96 66.803 13.512 66.899 ;
     RECT  7.8 65.603 8.76 67.283 ;
     RECT  18.432 63.635 18.912 71.459 ;
     RECT  11.52 65.171 11.544 75.443 ;
     RECT  38.016 67.333 38.04 81.299 ;
     RECT  15.36 82.789 15.384 83.509 ;
     RECT  15.36 83.509 15.672 83.555 ;
     RECT  16.848 63.203 16.872 83.795 ;
     RECT  37.872 81.445 37.896 83.797 ;
     RECT  40.2 2.151 40.512 83.797 ;
     RECT  13.2 66.899 13.512 84.325 ;
     RECT  15.648 83.555 15.672 84.611 ;
     RECT  41.52 84.181 41.544 84.755 ;
     RECT  37.776 83.797 40.512 84.949 ;
     RECT  13.2 84.325 13.896 85.237 ;
     RECT  16.656 84.949 16.872 85.237 ;
     RECT  2.4 52.403 2.712 85.329 ;
     RECT  7.8 67.283 8.112 85.329 ;
     RECT  18.6 71.459 18.912 85.329 ;
     RECT  24 21.683 24.312 85.329 ;
     RECT  29.4 2.151 29.712 85.329 ;
     RECT  34.8 2.151 35.112 85.329 ;
     RECT  37.392 84.949 40.512 85.329 ;
     RECT  45.6 2.151 45.912 85.329 ;
     RECT  51 2.151 51.312 85.329 ;
     RECT  56.4 2.151 56.712 85.329 ;
     RECT  61.8 2.151 62.112 85.329 ;
     RECT  67.2 2.151 67.512 85.329 ;
     RECT  72.6 2.151 72.912 85.329 ;
     RECT  78 2.151 78.312 85.329 ;
     RECT  83.4 2.151 83.712 85.329 ;
     RECT  88.8 2.151 89.112 85.329 ;
     RECT  94.2 2.151 94.512 85.329 ;
     RECT  99.6 2.151 99.912 85.329 ;
     RECT  105 2.151 105.312 85.329 ;
     RECT  110.4 2.151 110.712 85.329 ;
     RECT  115.8 2.151 116.112 85.329 ;
     RECT  121.2 39.443 121.512 85.329 ;
     RECT  126.6 2.151 126.912 85.329 ;
     RECT  132 2.151 132.312 85.329 ;
     RECT  137.4 2.151 137.712 85.329 ;
     RECT  2.4 85.329 2.52 85.343 ;
     RECT  7.8 85.329 7.944 85.343 ;
     RECT  13.2 85.237 14.088 85.343 ;
     RECT  18.6 85.329 18.72 85.343 ;
     RECT  24 85.329 24.12 85.343 ;
     RECT  29.4 85.329 29.52 85.343 ;
     RECT  34.8 85.329 34.92 85.343 ;
     RECT  37.392 85.329 40.32 85.343 ;
     RECT  45.6 85.329 45.72 85.343 ;
     RECT  51 85.329 51.12 85.343 ;
     RECT  56.4 85.329 56.52 85.343 ;
     RECT  61.8 85.329 61.92 85.343 ;
     RECT  67.2 85.329 67.32 85.343 ;
     RECT  72.6 85.329 72.72 85.343 ;
     RECT  78 85.329 78.12 85.343 ;
     RECT  83.4 85.329 83.52 85.343 ;
     RECT  88.8 85.329 88.92 85.343 ;
     RECT  94.2 85.329 94.32 85.343 ;
     RECT  99.6 85.329 99.72 85.343 ;
     RECT  105 85.329 105.12 85.343 ;
     RECT  110.4 85.329 110.52 85.343 ;
     RECT  115.8 85.329 115.92 85.343 ;
     RECT  121.2 85.329 121.32 85.343 ;
     RECT  126.6 85.329 126.72 85.343 ;
     RECT  132 85.329 132.12 85.343 ;
     RECT  137.4 85.329 137.52 85.343 ;
     RECT  37.392 85.343 40.104 85.429 ;
     RECT  16.656 85.237 16.968 85.477 ;
     RECT  37.104 85.429 40.104 85.477 ;
     RECT  21.888 49.525 21.912 87.349 ;
     RECT  21.648 87.349 21.912 87.395 ;
     RECT  5.904 85.477 5.928 87.44 ;
     RECT  7.92 85.343 7.944 87.44 ;
     RECT  13.392 85.343 14.088 87.44 ;
     RECT  16.464 85.477 17.064 87.44 ;
     RECT  21.648 87.395 21.672 87.44 ;
     RECT  37.008 85.477 40.104 87.44 ;
  END
END ot_hgi_dma_back_landing_bank
END LIBRARY
